VERSION 5.8 ;
BUSBITCHARS "[]" ;
DIVIDERCHAR "/" ;
UNITS
    DATABASE MICRONS 1000 ;
END UNITS

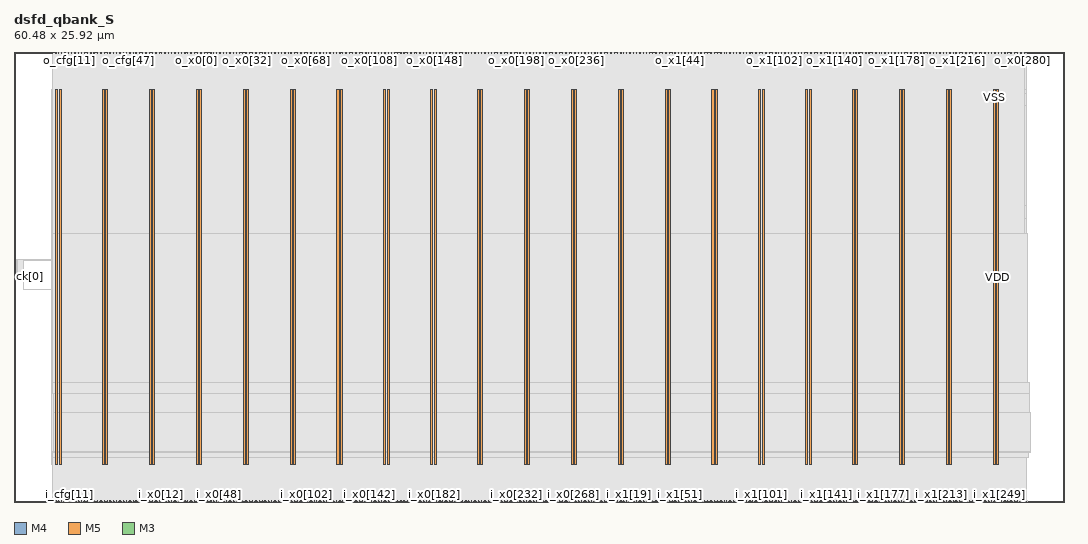
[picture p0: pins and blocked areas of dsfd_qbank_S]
MACRO dsfd_qbank_S
  FOREIGN dsfd_qbank_S 0 0 ;
  CLASS BLOCK ;
  SIZE 60.48 BY 25.92 ;
  PIN ck[0]
    DIRECTION INPUT ;
    USE SIGNAL ;
    PORT
      LAYER M4 ;
        RECT  0 12.96 0.084 12.984 ;
    END
  END ck[0]
  PIN i_cfg[0]
    DIRECTION INPUT ;
    USE SIGNAL ;
    PORT
      LAYER M5 ;
        RECT  2.208 0 2.232 0.084 ;
    END
  END i_cfg[0]
  PIN i_cfg[10]
    DIRECTION INPUT ;
    USE SIGNAL ;
    PORT
      LAYER M5 ;
        RECT  3.12 0 3.144 0.084 ;
    END
  END i_cfg[10]
  PIN i_cfg[11]
    DIRECTION INPUT ;
    USE SIGNAL ;
    PORT
      LAYER M3 ;
        RECT  3.204 0 3.222 0.038 ;
    END
  END i_cfg[11]
  PIN i_cfg[12]
    DIRECTION INPUT ;
    USE SIGNAL ;
    PORT
      LAYER M5 ;
        RECT  3.312 0 3.336 0.084 ;
    END
  END i_cfg[12]
  PIN i_cfg[13]
    DIRECTION INPUT ;
    USE SIGNAL ;
    PORT
      LAYER M3 ;
        RECT  3.42 0 3.438 0.038 ;
    END
  END i_cfg[13]
  PIN i_cfg[14]
    DIRECTION INPUT ;
    USE SIGNAL ;
    PORT
      LAYER M5 ;
        RECT  3.504 0 3.528 0.084 ;
    END
  END i_cfg[14]
  PIN i_cfg[15]
    DIRECTION INPUT ;
    USE SIGNAL ;
    PORT
      LAYER M3 ;
        RECT  3.6 0 3.618 0.038 ;
    END
  END i_cfg[15]
  PIN i_cfg[16]
    DIRECTION INPUT ;
    USE SIGNAL ;
    PORT
      LAYER M5 ;
        RECT  3.696 0 3.72 0.084 ;
    END
  END i_cfg[16]
  PIN i_cfg[17]
    DIRECTION INPUT ;
    USE SIGNAL ;
    PORT
      LAYER M3 ;
        RECT  3.78 0 3.798 0.038 ;
    END
  END i_cfg[17]
  PIN i_cfg[18]
    DIRECTION INPUT ;
    USE SIGNAL ;
    PORT
      LAYER M5 ;
        RECT  3.888 0 3.912 0.084 ;
    END
  END i_cfg[18]
  PIN i_cfg[19]
    DIRECTION INPUT ;
    USE SIGNAL ;
    PORT
      LAYER M3 ;
        RECT  3.996 0 4.014 0.038 ;
    END
  END i_cfg[19]
  PIN i_cfg[1]
    DIRECTION INPUT ;
    USE SIGNAL ;
    PORT
      LAYER M3 ;
        RECT  2.304 0 2.322 0.038 ;
    END
  END i_cfg[1]
  PIN i_cfg[20]
    DIRECTION INPUT ;
    USE SIGNAL ;
    PORT
      LAYER M5 ;
        RECT  4.032 0 4.056 0.084 ;
    END
  END i_cfg[20]
  PIN i_cfg[21]
    DIRECTION INPUT ;
    USE SIGNAL ;
    PORT
      LAYER M3 ;
        RECT  4.14 0 4.158 0.038 ;
    END
  END i_cfg[21]
  PIN i_cfg[22]
    DIRECTION INPUT ;
    USE SIGNAL ;
    PORT
      LAYER M5 ;
        RECT  4.224 0 4.248 0.084 ;
    END
  END i_cfg[22]
  PIN i_cfg[23]
    DIRECTION INPUT ;
    USE SIGNAL ;
    PORT
      LAYER M3 ;
        RECT  4.32 0 4.338 0.038 ;
    END
  END i_cfg[23]
  PIN i_cfg[24]
    DIRECTION INPUT ;
    USE SIGNAL ;
    PORT
      LAYER M5 ;
        RECT  4.416 0 4.44 0.084 ;
    END
  END i_cfg[24]
  PIN i_cfg[25]
    DIRECTION INPUT ;
    USE SIGNAL ;
    PORT
      LAYER M3 ;
        RECT  4.5 0 4.518 0.038 ;
    END
  END i_cfg[25]
  PIN i_cfg[26]
    DIRECTION INPUT ;
    USE SIGNAL ;
    PORT
      LAYER M5 ;
        RECT  4.608 0 4.632 0.084 ;
    END
  END i_cfg[26]
  PIN i_cfg[27]
    DIRECTION INPUT ;
    USE SIGNAL ;
    PORT
      LAYER M3 ;
        RECT  4.716 0 4.734 0.038 ;
    END
  END i_cfg[27]
  PIN i_cfg[28]
    DIRECTION INPUT ;
    USE SIGNAL ;
    PORT
      LAYER M5 ;
        RECT  4.8 0 4.824 0.084 ;
    END
  END i_cfg[28]
  PIN i_cfg[29]
    DIRECTION INPUT ;
    USE SIGNAL ;
    PORT
      LAYER M3 ;
        RECT  4.896 0 4.914 0.038 ;
    END
  END i_cfg[29]
  PIN i_cfg[2]
    DIRECTION INPUT ;
    USE SIGNAL ;
    PORT
      LAYER M5 ;
        RECT  2.4 0 2.424 0.084 ;
    END
  END i_cfg[2]
  PIN i_cfg[30]
    DIRECTION INPUT ;
    USE SIGNAL ;
    PORT
      LAYER M5 ;
        RECT  4.992 0 5.016 0.084 ;
    END
  END i_cfg[30]
  PIN i_cfg[31]
    DIRECTION INPUT ;
    USE SIGNAL ;
    PORT
      LAYER M3 ;
        RECT  5.076 0 5.094 0.038 ;
    END
  END i_cfg[31]
  PIN i_cfg[32]
    DIRECTION INPUT ;
    USE SIGNAL ;
    PORT
      LAYER M5 ;
        RECT  5.184 0 5.208 0.084 ;
    END
  END i_cfg[32]
  PIN i_cfg[33]
    DIRECTION INPUT ;
    USE SIGNAL ;
    PORT
      LAYER M3 ;
        RECT  5.292 0 5.31 0.038 ;
    END
  END i_cfg[33]
  PIN i_cfg[34]
    DIRECTION INPUT ;
    USE SIGNAL ;
    PORT
      LAYER M5 ;
        RECT  5.376 0 5.4 0.084 ;
    END
  END i_cfg[34]
  PIN i_cfg[35]
    DIRECTION INPUT ;
    USE SIGNAL ;
    PORT
      LAYER M3 ;
        RECT  5.472 0 5.49 0.038 ;
    END
  END i_cfg[35]
  PIN i_cfg[36]
    DIRECTION INPUT ;
    USE SIGNAL ;
    PORT
      LAYER M5 ;
        RECT  5.52 0 5.544 0.084 ;
    END
  END i_cfg[36]
  PIN i_cfg[37]
    DIRECTION INPUT ;
    USE SIGNAL ;
    PORT
      LAYER M3 ;
        RECT  5.616 0 5.634 0.038 ;
    END
  END i_cfg[37]
  PIN i_cfg[38]
    DIRECTION INPUT ;
    USE SIGNAL ;
    PORT
      LAYER M5 ;
        RECT  5.712 0 5.736 0.084 ;
    END
  END i_cfg[38]
  PIN i_cfg[39]
    DIRECTION INPUT ;
    USE SIGNAL ;
    PORT
      LAYER M3 ;
        RECT  5.796 0 5.814 0.038 ;
    END
  END i_cfg[39]
  PIN i_cfg[3]
    DIRECTION INPUT ;
    USE SIGNAL ;
    PORT
      LAYER M3 ;
        RECT  2.484 0 2.502 0.038 ;
    END
  END i_cfg[3]
  PIN i_cfg[40]
    DIRECTION INPUT ;
    USE SIGNAL ;
    PORT
      LAYER M5 ;
        RECT  5.904 0 5.928 0.084 ;
    END
  END i_cfg[40]
  PIN i_cfg[41]
    DIRECTION INPUT ;
    USE SIGNAL ;
    PORT
      LAYER M3 ;
        RECT  6.012 0 6.03 0.038 ;
    END
  END i_cfg[41]
  PIN i_cfg[42]
    DIRECTION INPUT ;
    USE SIGNAL ;
    PORT
      LAYER M5 ;
        RECT  6.096 0 6.12 0.084 ;
    END
  END i_cfg[42]
  PIN i_cfg[43]
    DIRECTION INPUT ;
    USE SIGNAL ;
    PORT
      LAYER M3 ;
        RECT  6.192 0 6.21 0.038 ;
    END
  END i_cfg[43]
  PIN i_cfg[44]
    DIRECTION INPUT ;
    USE SIGNAL ;
    PORT
      LAYER M5 ;
        RECT  6.288 0 6.312 0.084 ;
    END
  END i_cfg[44]
  PIN i_cfg[45]
    DIRECTION INPUT ;
    USE SIGNAL ;
    PORT
      LAYER M3 ;
        RECT  6.372 0 6.39 0.038 ;
    END
  END i_cfg[45]
  PIN i_cfg[46]
    DIRECTION INPUT ;
    USE SIGNAL ;
    PORT
      LAYER M5 ;
        RECT  6.48 0 6.504 0.084 ;
    END
  END i_cfg[46]
  PIN i_cfg[47]
    DIRECTION INPUT ;
    USE SIGNAL ;
    PORT
      LAYER M3 ;
        RECT  6.588 0 6.606 0.038 ;
    END
  END i_cfg[47]
  PIN i_cfg[48]
    DIRECTION INPUT ;
    USE SIGNAL ;
    PORT
      LAYER M5 ;
        RECT  6.672 0 6.696 0.084 ;
    END
  END i_cfg[48]
  PIN i_cfg[49]
    DIRECTION INPUT ;
    USE SIGNAL ;
    PORT
      LAYER M3 ;
        RECT  6.768 0 6.786 0.038 ;
    END
  END i_cfg[49]
  PIN i_cfg[4]
    DIRECTION INPUT ;
    USE SIGNAL ;
    PORT
      LAYER M5 ;
        RECT  2.544 0 2.568 0.084 ;
    END
  END i_cfg[4]
  PIN i_cfg[50]
    DIRECTION INPUT ;
    USE SIGNAL ;
    PORT
      LAYER M5 ;
        RECT  6.864 0 6.888 0.084 ;
    END
  END i_cfg[50]
  PIN i_cfg[51]
    DIRECTION INPUT ;
    USE SIGNAL ;
    PORT
      LAYER M3 ;
        RECT  6.948 0 6.966 0.038 ;
    END
  END i_cfg[51]
  PIN i_cfg[52]
    DIRECTION INPUT ;
    USE SIGNAL ;
    PORT
      LAYER M5 ;
        RECT  7.008 0 7.032 0.084 ;
    END
  END i_cfg[52]
  PIN i_cfg[53]
    DIRECTION INPUT ;
    USE SIGNAL ;
    PORT
      LAYER M3 ;
        RECT  7.092 0 7.11 0.038 ;
    END
  END i_cfg[53]
  PIN i_cfg[5]
    DIRECTION INPUT ;
    USE SIGNAL ;
    PORT
      LAYER M3 ;
        RECT  2.628 0 2.646 0.038 ;
    END
  END i_cfg[5]
  PIN i_cfg[6]
    DIRECTION INPUT ;
    USE SIGNAL ;
    PORT
      LAYER M5 ;
        RECT  2.736 0 2.76 0.084 ;
    END
  END i_cfg[6]
  PIN i_cfg[7]
    DIRECTION INPUT ;
    USE SIGNAL ;
    PORT
      LAYER M3 ;
        RECT  2.844 0 2.862 0.038 ;
    END
  END i_cfg[7]
  PIN i_cfg[8]
    DIRECTION INPUT ;
    USE SIGNAL ;
    PORT
      LAYER M5 ;
        RECT  2.928 0 2.952 0.084 ;
    END
  END i_cfg[8]
  PIN i_cfg[9]
    DIRECTION INPUT ;
    USE SIGNAL ;
    PORT
      LAYER M3 ;
        RECT  3.024 0 3.042 0.038 ;
    END
  END i_cfg[9]
  PIN i_go[0]
    DIRECTION INPUT ;
    USE SIGNAL ;
    PORT
      LAYER M5 ;
        RECT  7.2 0 7.224 0.084 ;
    END
  END i_go[0]
  PIN i_x0[0]
    DIRECTION INPUT ;
    USE SIGNAL ;
    PORT
      LAYER M3 ;
        RECT  7.308 0 7.326 0.038 ;
    END
  END i_x0[0]
  PIN i_x0[100]
    DIRECTION INPUT ;
    USE SIGNAL ;
    PORT
      LAYER M3 ;
        RECT  16.596 0 16.614 0.038 ;
    END
  END i_x0[100]
  PIN i_x0[101]
    DIRECTION INPUT ;
    USE SIGNAL ;
    PORT
      LAYER M5 ;
        RECT  16.704 0 16.728 0.084 ;
    END
  END i_x0[101]
  PIN i_x0[102]
    DIRECTION INPUT ;
    USE SIGNAL ;
    PORT
      LAYER M3 ;
        RECT  16.812 0 16.83 0.038 ;
    END
  END i_x0[102]
  PIN i_x0[103]
    DIRECTION INPUT ;
    USE SIGNAL ;
    PORT
      LAYER M5 ;
        RECT  16.896 0 16.92 0.084 ;
    END
  END i_x0[103]
  PIN i_x0[104]
    DIRECTION INPUT ;
    USE SIGNAL ;
    PORT
      LAYER M3 ;
        RECT  16.992 0 17.01 0.038 ;
    END
  END i_x0[104]
  PIN i_x0[105]
    DIRECTION INPUT ;
    USE SIGNAL ;
    PORT
      LAYER M5 ;
        RECT  17.088 0 17.112 0.084 ;
    END
  END i_x0[105]
  PIN i_x0[106]
    DIRECTION INPUT ;
    USE SIGNAL ;
    PORT
      LAYER M3 ;
        RECT  17.172 0 17.19 0.038 ;
    END
  END i_x0[106]
  PIN i_x0[107]
    DIRECTION INPUT ;
    USE SIGNAL ;
    PORT
      LAYER M5 ;
        RECT  17.28 0 17.304 0.084 ;
    END
  END i_x0[107]
  PIN i_x0[108]
    DIRECTION INPUT ;
    USE SIGNAL ;
    PORT
      LAYER M3 ;
        RECT  17.316 0 17.334 0.038 ;
    END
  END i_x0[108]
  PIN i_x0[109]
    DIRECTION INPUT ;
    USE SIGNAL ;
    PORT
      LAYER M5 ;
        RECT  17.424 0 17.448 0.084 ;
    END
  END i_x0[109]
  PIN i_x0[10]
    DIRECTION INPUT ;
    USE SIGNAL ;
    PORT
      LAYER M3 ;
        RECT  8.244 0 8.262 0.038 ;
    END
  END i_x0[10]
  PIN i_x0[110]
    DIRECTION INPUT ;
    USE SIGNAL ;
    PORT
      LAYER M3 ;
        RECT  17.532 0 17.55 0.038 ;
    END
  END i_x0[110]
  PIN i_x0[111]
    DIRECTION INPUT ;
    USE SIGNAL ;
    PORT
      LAYER M5 ;
        RECT  17.616 0 17.64 0.084 ;
    END
  END i_x0[111]
  PIN i_x0[112]
    DIRECTION INPUT ;
    USE SIGNAL ;
    PORT
      LAYER M3 ;
        RECT  17.712 0 17.73 0.038 ;
    END
  END i_x0[112]
  PIN i_x0[113]
    DIRECTION INPUT ;
    USE SIGNAL ;
    PORT
      LAYER M5 ;
        RECT  17.808 0 17.832 0.084 ;
    END
  END i_x0[113]
  PIN i_x0[114]
    DIRECTION INPUT ;
    USE SIGNAL ;
    PORT
      LAYER M3 ;
        RECT  17.892 0 17.91 0.038 ;
    END
  END i_x0[114]
  PIN i_x0[115]
    DIRECTION INPUT ;
    USE SIGNAL ;
    PORT
      LAYER M5 ;
        RECT  18 0 18.024 0.084 ;
    END
  END i_x0[115]
  PIN i_x0[116]
    DIRECTION INPUT ;
    USE SIGNAL ;
    PORT
      LAYER M3 ;
        RECT  18.108 0 18.126 0.038 ;
    END
  END i_x0[116]
  PIN i_x0[117]
    DIRECTION INPUT ;
    USE SIGNAL ;
    PORT
      LAYER M5 ;
        RECT  18.192 0 18.216 0.084 ;
    END
  END i_x0[117]
  PIN i_x0[118]
    DIRECTION INPUT ;
    USE SIGNAL ;
    PORT
      LAYER M3 ;
        RECT  18.288 0 18.306 0.038 ;
    END
  END i_x0[118]
  PIN i_x0[119]
    DIRECTION INPUT ;
    USE SIGNAL ;
    PORT
      LAYER M5 ;
        RECT  18.384 0 18.408 0.084 ;
    END
  END i_x0[119]
  PIN i_x0[11]
    DIRECTION INPUT ;
    USE SIGNAL ;
    PORT
      LAYER M5 ;
        RECT  8.352 0 8.376 0.084 ;
    END
  END i_x0[11]
  PIN i_x0[120]
    DIRECTION INPUT ;
    USE SIGNAL ;
    PORT
      LAYER M3 ;
        RECT  18.468 0 18.486 0.038 ;
    END
  END i_x0[120]
  PIN i_x0[121]
    DIRECTION INPUT ;
    USE SIGNAL ;
    PORT
      LAYER M5 ;
        RECT  18.576 0 18.6 0.084 ;
    END
  END i_x0[121]
  PIN i_x0[122]
    DIRECTION INPUT ;
    USE SIGNAL ;
    PORT
      LAYER M3 ;
        RECT  18.684 0 18.702 0.038 ;
    END
  END i_x0[122]
  PIN i_x0[123]
    DIRECTION INPUT ;
    USE SIGNAL ;
    PORT
      LAYER M5 ;
        RECT  18.768 0 18.792 0.084 ;
    END
  END i_x0[123]
  PIN i_x0[124]
    DIRECTION INPUT ;
    USE SIGNAL ;
    PORT
      LAYER M3 ;
        RECT  18.828 0 18.846 0.038 ;
    END
  END i_x0[124]
  PIN i_x0[125]
    DIRECTION INPUT ;
    USE SIGNAL ;
    PORT
      LAYER M5 ;
        RECT  18.912 0 18.936 0.084 ;
    END
  END i_x0[125]
  PIN i_x0[126]
    DIRECTION INPUT ;
    USE SIGNAL ;
    PORT
      LAYER M3 ;
        RECT  19.008 0 19.026 0.038 ;
    END
  END i_x0[126]
  PIN i_x0[127]
    DIRECTION INPUT ;
    USE SIGNAL ;
    PORT
      LAYER M5 ;
        RECT  19.104 0 19.128 0.084 ;
    END
  END i_x0[127]
  PIN i_x0[128]
    DIRECTION INPUT ;
    USE SIGNAL ;
    PORT
      LAYER M3 ;
        RECT  19.188 0 19.206 0.038 ;
    END
  END i_x0[128]
  PIN i_x0[129]
    DIRECTION INPUT ;
    USE SIGNAL ;
    PORT
      LAYER M5 ;
        RECT  19.296 0 19.32 0.084 ;
    END
  END i_x0[129]
  PIN i_x0[12]
    DIRECTION INPUT ;
    USE SIGNAL ;
    PORT
      LAYER M3 ;
        RECT  8.46 0 8.478 0.038 ;
    END
  END i_x0[12]
  PIN i_x0[130]
    DIRECTION INPUT ;
    USE SIGNAL ;
    PORT
      LAYER M3 ;
        RECT  19.404 0 19.422 0.038 ;
    END
  END i_x0[130]
  PIN i_x0[131]
    DIRECTION INPUT ;
    USE SIGNAL ;
    PORT
      LAYER M5 ;
        RECT  19.488 0 19.512 0.084 ;
    END
  END i_x0[131]
  PIN i_x0[132]
    DIRECTION INPUT ;
    USE SIGNAL ;
    PORT
      LAYER M3 ;
        RECT  19.584 0 19.602 0.038 ;
    END
  END i_x0[132]
  PIN i_x0[133]
    DIRECTION INPUT ;
    USE SIGNAL ;
    PORT
      LAYER M5 ;
        RECT  19.68 0 19.704 0.084 ;
    END
  END i_x0[133]
  PIN i_x0[134]
    DIRECTION INPUT ;
    USE SIGNAL ;
    PORT
      LAYER M3 ;
        RECT  19.764 0 19.782 0.038 ;
    END
  END i_x0[134]
  PIN i_x0[135]
    DIRECTION INPUT ;
    USE SIGNAL ;
    PORT
      LAYER M5 ;
        RECT  19.872 0 19.896 0.084 ;
    END
  END i_x0[135]
  PIN i_x0[136]
    DIRECTION INPUT ;
    USE SIGNAL ;
    PORT
      LAYER M3 ;
        RECT  19.98 0 19.998 0.038 ;
    END
  END i_x0[136]
  PIN i_x0[137]
    DIRECTION INPUT ;
    USE SIGNAL ;
    PORT
      LAYER M5 ;
        RECT  20.064 0 20.088 0.084 ;
    END
  END i_x0[137]
  PIN i_x0[138]
    DIRECTION INPUT ;
    USE SIGNAL ;
    PORT
      LAYER M3 ;
        RECT  20.16 0 20.178 0.038 ;
    END
  END i_x0[138]
  PIN i_x0[139]
    DIRECTION INPUT ;
    USE SIGNAL ;
    PORT
      LAYER M5 ;
        RECT  20.256 0 20.28 0.084 ;
    END
  END i_x0[139]
  PIN i_x0[13]
    DIRECTION INPUT ;
    USE SIGNAL ;
    PORT
      LAYER M5 ;
        RECT  8.496 0 8.52 0.084 ;
    END
  END i_x0[13]
  PIN i_x0[140]
    DIRECTION INPUT ;
    USE SIGNAL ;
    PORT
      LAYER M3 ;
        RECT  20.304 0 20.322 0.038 ;
    END
  END i_x0[140]
  PIN i_x0[141]
    DIRECTION INPUT ;
    USE SIGNAL ;
    PORT
      LAYER M5 ;
        RECT  20.4 0 20.424 0.084 ;
    END
  END i_x0[141]
  PIN i_x0[142]
    DIRECTION INPUT ;
    USE SIGNAL ;
    PORT
      LAYER M3 ;
        RECT  20.484 0 20.502 0.038 ;
    END
  END i_x0[142]
  PIN i_x0[143]
    DIRECTION INPUT ;
    USE SIGNAL ;
    PORT
      LAYER M5 ;
        RECT  20.592 0 20.616 0.084 ;
    END
  END i_x0[143]
  PIN i_x0[144]
    DIRECTION INPUT ;
    USE SIGNAL ;
    PORT
      LAYER M3 ;
        RECT  20.7 0 20.718 0.038 ;
    END
  END i_x0[144]
  PIN i_x0[145]
    DIRECTION INPUT ;
    USE SIGNAL ;
    PORT
      LAYER M5 ;
        RECT  20.784 0 20.808 0.084 ;
    END
  END i_x0[145]
  PIN i_x0[146]
    DIRECTION INPUT ;
    USE SIGNAL ;
    PORT
      LAYER M3 ;
        RECT  20.88 0 20.898 0.038 ;
    END
  END i_x0[146]
  PIN i_x0[147]
    DIRECTION INPUT ;
    USE SIGNAL ;
    PORT
      LAYER M5 ;
        RECT  20.976 0 21 0.084 ;
    END
  END i_x0[147]
  PIN i_x0[148]
    DIRECTION INPUT ;
    USE SIGNAL ;
    PORT
      LAYER M3 ;
        RECT  21.06 0 21.078 0.038 ;
    END
  END i_x0[148]
  PIN i_x0[149]
    DIRECTION INPUT ;
    USE SIGNAL ;
    PORT
      LAYER M5 ;
        RECT  21.168 0 21.192 0.084 ;
    END
  END i_x0[149]
  PIN i_x0[14]
    DIRECTION INPUT ;
    USE SIGNAL ;
    PORT
      LAYER M3 ;
        RECT  8.604 0 8.622 0.038 ;
    END
  END i_x0[14]
  PIN i_x0[150]
    DIRECTION INPUT ;
    USE SIGNAL ;
    PORT
      LAYER M3 ;
        RECT  21.276 0 21.294 0.038 ;
    END
  END i_x0[150]
  PIN i_x0[151]
    DIRECTION INPUT ;
    USE SIGNAL ;
    PORT
      LAYER M5 ;
        RECT  21.36 0 21.384 0.084 ;
    END
  END i_x0[151]
  PIN i_x0[152]
    DIRECTION INPUT ;
    USE SIGNAL ;
    PORT
      LAYER M3 ;
        RECT  21.456 0 21.474 0.038 ;
    END
  END i_x0[152]
  PIN i_x0[153]
    DIRECTION INPUT ;
    USE SIGNAL ;
    PORT
      LAYER M5 ;
        RECT  21.552 0 21.576 0.084 ;
    END
  END i_x0[153]
  PIN i_x0[154]
    DIRECTION INPUT ;
    USE SIGNAL ;
    PORT
      LAYER M3 ;
        RECT  21.636 0 21.654 0.038 ;
    END
  END i_x0[154]
  PIN i_x0[155]
    DIRECTION INPUT ;
    USE SIGNAL ;
    PORT
      LAYER M5 ;
        RECT  21.744 0 21.768 0.084 ;
    END
  END i_x0[155]
  PIN i_x0[156]
    DIRECTION INPUT ;
    USE SIGNAL ;
    PORT
      LAYER M3 ;
        RECT  21.78 0 21.798 0.038 ;
    END
  END i_x0[156]
  PIN i_x0[157]
    DIRECTION INPUT ;
    USE SIGNAL ;
    PORT
      LAYER M5 ;
        RECT  21.888 0 21.912 0.084 ;
    END
  END i_x0[157]
  PIN i_x0[158]
    DIRECTION INPUT ;
    USE SIGNAL ;
    PORT
      LAYER M3 ;
        RECT  21.996 0 22.014 0.038 ;
    END
  END i_x0[158]
  PIN i_x0[159]
    DIRECTION INPUT ;
    USE SIGNAL ;
    PORT
      LAYER M5 ;
        RECT  22.08 0 22.104 0.084 ;
    END
  END i_x0[159]
  PIN i_x0[15]
    DIRECTION INPUT ;
    USE SIGNAL ;
    PORT
      LAYER M5 ;
        RECT  8.688 0 8.712 0.084 ;
    END
  END i_x0[15]
  PIN i_x0[160]
    DIRECTION INPUT ;
    USE SIGNAL ;
    PORT
      LAYER M3 ;
        RECT  22.176 0 22.194 0.038 ;
    END
  END i_x0[160]
  PIN i_x0[161]
    DIRECTION INPUT ;
    USE SIGNAL ;
    PORT
      LAYER M5 ;
        RECT  22.272 0 22.296 0.084 ;
    END
  END i_x0[161]
  PIN i_x0[162]
    DIRECTION INPUT ;
    USE SIGNAL ;
    PORT
      LAYER M3 ;
        RECT  22.356 0 22.374 0.038 ;
    END
  END i_x0[162]
  PIN i_x0[163]
    DIRECTION INPUT ;
    USE SIGNAL ;
    PORT
      LAYER M5 ;
        RECT  22.464 0 22.488 0.084 ;
    END
  END i_x0[163]
  PIN i_x0[164]
    DIRECTION INPUT ;
    USE SIGNAL ;
    PORT
      LAYER M3 ;
        RECT  22.572 0 22.59 0.038 ;
    END
  END i_x0[164]
  PIN i_x0[165]
    DIRECTION INPUT ;
    USE SIGNAL ;
    PORT
      LAYER M5 ;
        RECT  22.656 0 22.68 0.084 ;
    END
  END i_x0[165]
  PIN i_x0[166]
    DIRECTION INPUT ;
    USE SIGNAL ;
    PORT
      LAYER M3 ;
        RECT  22.752 0 22.77 0.038 ;
    END
  END i_x0[166]
  PIN i_x0[167]
    DIRECTION INPUT ;
    USE SIGNAL ;
    PORT
      LAYER M5 ;
        RECT  22.848 0 22.872 0.084 ;
    END
  END i_x0[167]
  PIN i_x0[168]
    DIRECTION INPUT ;
    USE SIGNAL ;
    PORT
      LAYER M3 ;
        RECT  22.932 0 22.95 0.038 ;
    END
  END i_x0[168]
  PIN i_x0[169]
    DIRECTION INPUT ;
    USE SIGNAL ;
    PORT
      LAYER M5 ;
        RECT  23.04 0 23.064 0.084 ;
    END
  END i_x0[169]
  PIN i_x0[16]
    DIRECTION INPUT ;
    USE SIGNAL ;
    PORT
      LAYER M3 ;
        RECT  8.784 0 8.802 0.038 ;
    END
  END i_x0[16]
  PIN i_x0[170]
    DIRECTION INPUT ;
    USE SIGNAL ;
    PORT
      LAYER M3 ;
        RECT  23.148 0 23.166 0.038 ;
    END
  END i_x0[170]
  PIN i_x0[171]
    DIRECTION INPUT ;
    USE SIGNAL ;
    PORT
      LAYER M5 ;
        RECT  23.184 0 23.208 0.084 ;
    END
  END i_x0[171]
  PIN i_x0[172]
    DIRECTION INPUT ;
    USE SIGNAL ;
    PORT
      LAYER M3 ;
        RECT  23.292 0 23.31 0.038 ;
    END
  END i_x0[172]
  PIN i_x0[173]
    DIRECTION INPUT ;
    USE SIGNAL ;
    PORT
      LAYER M5 ;
        RECT  23.376 0 23.4 0.084 ;
    END
  END i_x0[173]
  PIN i_x0[174]
    DIRECTION INPUT ;
    USE SIGNAL ;
    PORT
      LAYER M3 ;
        RECT  23.472 0 23.49 0.038 ;
    END
  END i_x0[174]
  PIN i_x0[175]
    DIRECTION INPUT ;
    USE SIGNAL ;
    PORT
      LAYER M5 ;
        RECT  23.568 0 23.592 0.084 ;
    END
  END i_x0[175]
  PIN i_x0[176]
    DIRECTION INPUT ;
    USE SIGNAL ;
    PORT
      LAYER M3 ;
        RECT  23.652 0 23.67 0.038 ;
    END
  END i_x0[176]
  PIN i_x0[177]
    DIRECTION INPUT ;
    USE SIGNAL ;
    PORT
      LAYER M5 ;
        RECT  23.76 0 23.784 0.084 ;
    END
  END i_x0[177]
  PIN i_x0[178]
    DIRECTION INPUT ;
    USE SIGNAL ;
    PORT
      LAYER M3 ;
        RECT  23.868 0 23.886 0.038 ;
    END
  END i_x0[178]
  PIN i_x0[179]
    DIRECTION INPUT ;
    USE SIGNAL ;
    PORT
      LAYER M5 ;
        RECT  23.952 0 23.976 0.084 ;
    END
  END i_x0[179]
  PIN i_x0[17]
    DIRECTION INPUT ;
    USE SIGNAL ;
    PORT
      LAYER M5 ;
        RECT  8.88 0 8.904 0.084 ;
    END
  END i_x0[17]
  PIN i_x0[180]
    DIRECTION INPUT ;
    USE SIGNAL ;
    PORT
      LAYER M3 ;
        RECT  24.048 0 24.066 0.038 ;
    END
  END i_x0[180]
  PIN i_x0[181]
    DIRECTION INPUT ;
    USE SIGNAL ;
    PORT
      LAYER M5 ;
        RECT  24.144 0 24.168 0.084 ;
    END
  END i_x0[181]
  PIN i_x0[182]
    DIRECTION INPUT ;
    USE SIGNAL ;
    PORT
      LAYER M3 ;
        RECT  24.228 0 24.246 0.038 ;
    END
  END i_x0[182]
  PIN i_x0[183]
    DIRECTION INPUT ;
    USE SIGNAL ;
    PORT
      LAYER M5 ;
        RECT  24.336 0 24.36 0.084 ;
    END
  END i_x0[183]
  PIN i_x0[184]
    DIRECTION INPUT ;
    USE SIGNAL ;
    PORT
      LAYER M3 ;
        RECT  24.444 0 24.462 0.038 ;
    END
  END i_x0[184]
  PIN i_x0[185]
    DIRECTION INPUT ;
    USE SIGNAL ;
    PORT
      LAYER M5 ;
        RECT  24.528 0 24.552 0.084 ;
    END
  END i_x0[185]
  PIN i_x0[186]
    DIRECTION INPUT ;
    USE SIGNAL ;
    PORT
      LAYER M3 ;
        RECT  24.624 0 24.642 0.038 ;
    END
  END i_x0[186]
  PIN i_x0[187]
    DIRECTION INPUT ;
    USE SIGNAL ;
    PORT
      LAYER M5 ;
        RECT  24.672 0 24.696 0.084 ;
    END
  END i_x0[187]
  PIN i_x0[188]
    DIRECTION INPUT ;
    USE SIGNAL ;
    PORT
      LAYER M3 ;
        RECT  24.768 0 24.786 0.038 ;
    END
  END i_x0[188]
  PIN i_x0[189]
    DIRECTION INPUT ;
    USE SIGNAL ;
    PORT
      LAYER M5 ;
        RECT  24.864 0 24.888 0.084 ;
    END
  END i_x0[189]
  PIN i_x0[18]
    DIRECTION INPUT ;
    USE SIGNAL ;
    PORT
      LAYER M3 ;
        RECT  8.964 0 8.982 0.038 ;
    END
  END i_x0[18]
  PIN i_x0[190]
    DIRECTION INPUT ;
    USE SIGNAL ;
    PORT
      LAYER M3 ;
        RECT  24.948 0 24.966 0.038 ;
    END
  END i_x0[190]
  PIN i_x0[191]
    DIRECTION INPUT ;
    USE SIGNAL ;
    PORT
      LAYER M5 ;
        RECT  25.056 0 25.08 0.084 ;
    END
  END i_x0[191]
  PIN i_x0[192]
    DIRECTION INPUT ;
    USE SIGNAL ;
    PORT
      LAYER M3 ;
        RECT  25.164 0 25.182 0.038 ;
    END
  END i_x0[192]
  PIN i_x0[193]
    DIRECTION INPUT ;
    USE SIGNAL ;
    PORT
      LAYER M5 ;
        RECT  25.248 0 25.272 0.084 ;
    END
  END i_x0[193]
  PIN i_x0[194]
    DIRECTION INPUT ;
    USE SIGNAL ;
    PORT
      LAYER M3 ;
        RECT  25.344 0 25.362 0.038 ;
    END
  END i_x0[194]
  PIN i_x0[195]
    DIRECTION INPUT ;
    USE SIGNAL ;
    PORT
      LAYER M5 ;
        RECT  25.44 0 25.464 0.084 ;
    END
  END i_x0[195]
  PIN i_x0[196]
    DIRECTION INPUT ;
    USE SIGNAL ;
    PORT
      LAYER M3 ;
        RECT  25.524 0 25.542 0.038 ;
    END
  END i_x0[196]
  PIN i_x0[197]
    DIRECTION INPUT ;
    USE SIGNAL ;
    PORT
      LAYER M5 ;
        RECT  25.632 0 25.656 0.084 ;
    END
  END i_x0[197]
  PIN i_x0[198]
    DIRECTION INPUT ;
    USE SIGNAL ;
    PORT
      LAYER M3 ;
        RECT  25.74 0 25.758 0.038 ;
    END
  END i_x0[198]
  PIN i_x0[199]
    DIRECTION INPUT ;
    USE SIGNAL ;
    PORT
      LAYER M5 ;
        RECT  25.824 0 25.848 0.084 ;
    END
  END i_x0[199]
  PIN i_x0[19]
    DIRECTION INPUT ;
    USE SIGNAL ;
    PORT
      LAYER M5 ;
        RECT  9.072 0 9.096 0.084 ;
    END
  END i_x0[19]
  PIN i_x0[1]
    DIRECTION INPUT ;
    USE SIGNAL ;
    PORT
      LAYER M5 ;
        RECT  7.392 0 7.416 0.084 ;
    END
  END i_x0[1]
  PIN i_x0[200]
    DIRECTION INPUT ;
    USE SIGNAL ;
    PORT
      LAYER M3 ;
        RECT  25.92 0 25.938 0.038 ;
    END
  END i_x0[200]
  PIN i_x0[201]
    DIRECTION INPUT ;
    USE SIGNAL ;
    PORT
      LAYER M5 ;
        RECT  26.016 0 26.04 0.084 ;
    END
  END i_x0[201]
  PIN i_x0[202]
    DIRECTION INPUT ;
    USE SIGNAL ;
    PORT
      LAYER M3 ;
        RECT  26.1 0 26.118 0.038 ;
    END
  END i_x0[202]
  PIN i_x0[203]
    DIRECTION INPUT ;
    USE SIGNAL ;
    PORT
      LAYER M5 ;
        RECT  26.16 0 26.184 0.084 ;
    END
  END i_x0[203]
  PIN i_x0[204]
    DIRECTION INPUT ;
    USE SIGNAL ;
    PORT
      LAYER M3 ;
        RECT  26.244 0 26.262 0.038 ;
    END
  END i_x0[204]
  PIN i_x0[205]
    DIRECTION INPUT ;
    USE SIGNAL ;
    PORT
      LAYER M5 ;
        RECT  26.352 0 26.376 0.084 ;
    END
  END i_x0[205]
  PIN i_x0[206]
    DIRECTION INPUT ;
    USE SIGNAL ;
    PORT
      LAYER M3 ;
        RECT  26.46 0 26.478 0.038 ;
    END
  END i_x0[206]
  PIN i_x0[207]
    DIRECTION INPUT ;
    USE SIGNAL ;
    PORT
      LAYER M5 ;
        RECT  26.544 0 26.568 0.084 ;
    END
  END i_x0[207]
  PIN i_x0[208]
    DIRECTION INPUT ;
    USE SIGNAL ;
    PORT
      LAYER M3 ;
        RECT  26.64 0 26.658 0.038 ;
    END
  END i_x0[208]
  PIN i_x0[209]
    DIRECTION INPUT ;
    USE SIGNAL ;
    PORT
      LAYER M5 ;
        RECT  26.736 0 26.76 0.084 ;
    END
  END i_x0[209]
  PIN i_x0[20]
    DIRECTION INPUT ;
    USE SIGNAL ;
    PORT
      LAYER M3 ;
        RECT  9.18 0 9.198 0.038 ;
    END
  END i_x0[20]
  PIN i_x0[210]
    DIRECTION INPUT ;
    USE SIGNAL ;
    PORT
      LAYER M3 ;
        RECT  26.82 0 26.838 0.038 ;
    END
  END i_x0[210]
  PIN i_x0[211]
    DIRECTION INPUT ;
    USE SIGNAL ;
    PORT
      LAYER M5 ;
        RECT  26.928 0 26.952 0.084 ;
    END
  END i_x0[211]
  PIN i_x0[212]
    DIRECTION INPUT ;
    USE SIGNAL ;
    PORT
      LAYER M3 ;
        RECT  27.036 0 27.054 0.038 ;
    END
  END i_x0[212]
  PIN i_x0[213]
    DIRECTION INPUT ;
    USE SIGNAL ;
    PORT
      LAYER M5 ;
        RECT  27.12 0 27.144 0.084 ;
    END
  END i_x0[213]
  PIN i_x0[214]
    DIRECTION INPUT ;
    USE SIGNAL ;
    PORT
      LAYER M3 ;
        RECT  27.216 0 27.234 0.038 ;
    END
  END i_x0[214]
  PIN i_x0[215]
    DIRECTION INPUT ;
    USE SIGNAL ;
    PORT
      LAYER M5 ;
        RECT  27.312 0 27.336 0.084 ;
    END
  END i_x0[215]
  PIN i_x0[216]
    DIRECTION INPUT ;
    USE SIGNAL ;
    PORT
      LAYER M3 ;
        RECT  27.396 0 27.414 0.038 ;
    END
  END i_x0[216]
  PIN i_x0[217]
    DIRECTION INPUT ;
    USE SIGNAL ;
    PORT
      LAYER M5 ;
        RECT  27.504 0 27.528 0.084 ;
    END
  END i_x0[217]
  PIN i_x0[218]
    DIRECTION INPUT ;
    USE SIGNAL ;
    PORT
      LAYER M3 ;
        RECT  27.612 0 27.63 0.038 ;
    END
  END i_x0[218]
  PIN i_x0[219]
    DIRECTION INPUT ;
    USE SIGNAL ;
    PORT
      LAYER M5 ;
        RECT  27.648 0 27.672 0.084 ;
    END
  END i_x0[219]
  PIN i_x0[21]
    DIRECTION INPUT ;
    USE SIGNAL ;
    PORT
      LAYER M5 ;
        RECT  9.264 0 9.288 0.084 ;
    END
  END i_x0[21]
  PIN i_x0[220]
    DIRECTION INPUT ;
    USE SIGNAL ;
    PORT
      LAYER M3 ;
        RECT  27.756 0 27.774 0.038 ;
    END
  END i_x0[220]
  PIN i_x0[221]
    DIRECTION INPUT ;
    USE SIGNAL ;
    PORT
      LAYER M5 ;
        RECT  27.84 0 27.864 0.084 ;
    END
  END i_x0[221]
  PIN i_x0[222]
    DIRECTION INPUT ;
    USE SIGNAL ;
    PORT
      LAYER M3 ;
        RECT  27.936 0 27.954 0.038 ;
    END
  END i_x0[222]
  PIN i_x0[223]
    DIRECTION INPUT ;
    USE SIGNAL ;
    PORT
      LAYER M5 ;
        RECT  28.032 0 28.056 0.084 ;
    END
  END i_x0[223]
  PIN i_x0[224]
    DIRECTION INPUT ;
    USE SIGNAL ;
    PORT
      LAYER M3 ;
        RECT  28.116 0 28.134 0.038 ;
    END
  END i_x0[224]
  PIN i_x0[225]
    DIRECTION INPUT ;
    USE SIGNAL ;
    PORT
      LAYER M5 ;
        RECT  28.224 0 28.248 0.084 ;
    END
  END i_x0[225]
  PIN i_x0[226]
    DIRECTION INPUT ;
    USE SIGNAL ;
    PORT
      LAYER M3 ;
        RECT  28.332 0 28.35 0.038 ;
    END
  END i_x0[226]
  PIN i_x0[227]
    DIRECTION INPUT ;
    USE SIGNAL ;
    PORT
      LAYER M5 ;
        RECT  28.416 0 28.44 0.084 ;
    END
  END i_x0[227]
  PIN i_x0[228]
    DIRECTION INPUT ;
    USE SIGNAL ;
    PORT
      LAYER M3 ;
        RECT  28.512 0 28.53 0.038 ;
    END
  END i_x0[228]
  PIN i_x0[229]
    DIRECTION INPUT ;
    USE SIGNAL ;
    PORT
      LAYER M5 ;
        RECT  28.608 0 28.632 0.084 ;
    END
  END i_x0[229]
  PIN i_x0[22]
    DIRECTION INPUT ;
    USE SIGNAL ;
    PORT
      LAYER M3 ;
        RECT  9.36 0 9.378 0.038 ;
    END
  END i_x0[22]
  PIN i_x0[230]
    DIRECTION INPUT ;
    USE SIGNAL ;
    PORT
      LAYER M3 ;
        RECT  28.692 0 28.71 0.038 ;
    END
  END i_x0[230]
  PIN i_x0[231]
    DIRECTION INPUT ;
    USE SIGNAL ;
    PORT
      LAYER M5 ;
        RECT  28.8 0 28.824 0.084 ;
    END
  END i_x0[231]
  PIN i_x0[232]
    DIRECTION INPUT ;
    USE SIGNAL ;
    PORT
      LAYER M3 ;
        RECT  28.908 0 28.926 0.038 ;
    END
  END i_x0[232]
  PIN i_x0[233]
    DIRECTION INPUT ;
    USE SIGNAL ;
    PORT
      LAYER M5 ;
        RECT  28.992 0 29.016 0.084 ;
    END
  END i_x0[233]
  PIN i_x0[234]
    DIRECTION INPUT ;
    USE SIGNAL ;
    PORT
      LAYER M3 ;
        RECT  29.088 0 29.106 0.038 ;
    END
  END i_x0[234]
  PIN i_x0[235]
    DIRECTION INPUT ;
    USE SIGNAL ;
    PORT
      LAYER M5 ;
        RECT  29.136 0 29.16 0.084 ;
    END
  END i_x0[235]
  PIN i_x0[236]
    DIRECTION INPUT ;
    USE SIGNAL ;
    PORT
      LAYER M3 ;
        RECT  29.232 0 29.25 0.038 ;
    END
  END i_x0[236]
  PIN i_x0[237]
    DIRECTION INPUT ;
    USE SIGNAL ;
    PORT
      LAYER M5 ;
        RECT  29.328 0 29.352 0.084 ;
    END
  END i_x0[237]
  PIN i_x0[238]
    DIRECTION INPUT ;
    USE SIGNAL ;
    PORT
      LAYER M3 ;
        RECT  29.412 0 29.43 0.038 ;
    END
  END i_x0[238]
  PIN i_x0[239]
    DIRECTION INPUT ;
    USE SIGNAL ;
    PORT
      LAYER M5 ;
        RECT  29.52 0 29.544 0.084 ;
    END
  END i_x0[239]
  PIN i_x0[23]
    DIRECTION INPUT ;
    USE SIGNAL ;
    PORT
      LAYER M5 ;
        RECT  9.456 0 9.48 0.084 ;
    END
  END i_x0[23]
  PIN i_x0[240]
    DIRECTION INPUT ;
    USE SIGNAL ;
    PORT
      LAYER M3 ;
        RECT  29.628 0 29.646 0.038 ;
    END
  END i_x0[240]
  PIN i_x0[241]
    DIRECTION INPUT ;
    USE SIGNAL ;
    PORT
      LAYER M5 ;
        RECT  29.712 0 29.736 0.084 ;
    END
  END i_x0[241]
  PIN i_x0[242]
    DIRECTION INPUT ;
    USE SIGNAL ;
    PORT
      LAYER M3 ;
        RECT  29.808 0 29.826 0.038 ;
    END
  END i_x0[242]
  PIN i_x0[243]
    DIRECTION INPUT ;
    USE SIGNAL ;
    PORT
      LAYER M5 ;
        RECT  29.904 0 29.928 0.084 ;
    END
  END i_x0[243]
  PIN i_x0[244]
    DIRECTION INPUT ;
    USE SIGNAL ;
    PORT
      LAYER M3 ;
        RECT  29.988 0 30.006 0.038 ;
    END
  END i_x0[244]
  PIN i_x0[245]
    DIRECTION INPUT ;
    USE SIGNAL ;
    PORT
      LAYER M5 ;
        RECT  30.096 0 30.12 0.084 ;
    END
  END i_x0[245]
  PIN i_x0[246]
    DIRECTION INPUT ;
    USE SIGNAL ;
    PORT
      LAYER M3 ;
        RECT  30.204 0 30.222 0.038 ;
    END
  END i_x0[246]
  PIN i_x0[247]
    DIRECTION INPUT ;
    USE SIGNAL ;
    PORT
      LAYER M5 ;
        RECT  30.288 0 30.312 0.084 ;
    END
  END i_x0[247]
  PIN i_x0[248]
    DIRECTION INPUT ;
    USE SIGNAL ;
    PORT
      LAYER M3 ;
        RECT  30.384 0 30.402 0.038 ;
    END
  END i_x0[248]
  PIN i_x0[249]
    DIRECTION INPUT ;
    USE SIGNAL ;
    PORT
      LAYER M5 ;
        RECT  30.48 0 30.504 0.084 ;
    END
  END i_x0[249]
  PIN i_x0[24]
    DIRECTION INPUT ;
    USE SIGNAL ;
    PORT
      LAYER M3 ;
        RECT  9.54 0 9.558 0.038 ;
    END
  END i_x0[24]
  PIN i_x0[250]
    DIRECTION INPUT ;
    USE SIGNAL ;
    PORT
      LAYER M3 ;
        RECT  30.564 0 30.582 0.038 ;
    END
  END i_x0[250]
  PIN i_x0[251]
    DIRECTION INPUT ;
    USE SIGNAL ;
    PORT
      LAYER M5 ;
        RECT  30.624 0 30.648 0.084 ;
    END
  END i_x0[251]
  PIN i_x0[252]
    DIRECTION INPUT ;
    USE SIGNAL ;
    PORT
      LAYER M3 ;
        RECT  30.708 0 30.726 0.038 ;
    END
  END i_x0[252]
  PIN i_x0[253]
    DIRECTION INPUT ;
    USE SIGNAL ;
    PORT
      LAYER M5 ;
        RECT  30.816 0 30.84 0.084 ;
    END
  END i_x0[253]
  PIN i_x0[254]
    DIRECTION INPUT ;
    USE SIGNAL ;
    PORT
      LAYER M3 ;
        RECT  30.924 0 30.942 0.038 ;
    END
  END i_x0[254]
  PIN i_x0[255]
    DIRECTION INPUT ;
    USE SIGNAL ;
    PORT
      LAYER M5 ;
        RECT  31.008 0 31.032 0.084 ;
    END
  END i_x0[255]
  PIN i_x0[256]
    DIRECTION INPUT ;
    USE SIGNAL ;
    PORT
      LAYER M3 ;
        RECT  31.104 0 31.122 0.038 ;
    END
  END i_x0[256]
  PIN i_x0[257]
    DIRECTION INPUT ;
    USE SIGNAL ;
    PORT
      LAYER M5 ;
        RECT  31.2 0 31.224 0.084 ;
    END
  END i_x0[257]
  PIN i_x0[258]
    DIRECTION INPUT ;
    USE SIGNAL ;
    PORT
      LAYER M3 ;
        RECT  31.284 0 31.302 0.038 ;
    END
  END i_x0[258]
  PIN i_x0[259]
    DIRECTION INPUT ;
    USE SIGNAL ;
    PORT
      LAYER M5 ;
        RECT  31.392 0 31.416 0.084 ;
    END
  END i_x0[259]
  PIN i_x0[25]
    DIRECTION INPUT ;
    USE SIGNAL ;
    PORT
      LAYER M5 ;
        RECT  9.648 0 9.672 0.084 ;
    END
  END i_x0[25]
  PIN i_x0[260]
    DIRECTION INPUT ;
    USE SIGNAL ;
    PORT
      LAYER M3 ;
        RECT  31.5 0 31.518 0.038 ;
    END
  END i_x0[260]
  PIN i_x0[261]
    DIRECTION INPUT ;
    USE SIGNAL ;
    PORT
      LAYER M5 ;
        RECT  31.584 0 31.608 0.084 ;
    END
  END i_x0[261]
  PIN i_x0[262]
    DIRECTION INPUT ;
    USE SIGNAL ;
    PORT
      LAYER M3 ;
        RECT  31.68 0 31.698 0.038 ;
    END
  END i_x0[262]
  PIN i_x0[263]
    DIRECTION INPUT ;
    USE SIGNAL ;
    PORT
      LAYER M5 ;
        RECT  31.776 0 31.8 0.084 ;
    END
  END i_x0[263]
  PIN i_x0[264]
    DIRECTION INPUT ;
    USE SIGNAL ;
    PORT
      LAYER M3 ;
        RECT  31.86 0 31.878 0.038 ;
    END
  END i_x0[264]
  PIN i_x0[265]
    DIRECTION INPUT ;
    USE SIGNAL ;
    PORT
      LAYER M5 ;
        RECT  31.968 0 31.992 0.084 ;
    END
  END i_x0[265]
  PIN i_x0[266]
    DIRECTION INPUT ;
    USE SIGNAL ;
    PORT
      LAYER M3 ;
        RECT  32.076 0 32.094 0.038 ;
    END
  END i_x0[266]
  PIN i_x0[267]
    DIRECTION INPUT ;
    USE SIGNAL ;
    PORT
      LAYER M5 ;
        RECT  32.112 0 32.136 0.084 ;
    END
  END i_x0[267]
  PIN i_x0[268]
    DIRECTION INPUT ;
    USE SIGNAL ;
    PORT
      LAYER M3 ;
        RECT  32.22 0 32.238 0.038 ;
    END
  END i_x0[268]
  PIN i_x0[269]
    DIRECTION INPUT ;
    USE SIGNAL ;
    PORT
      LAYER M5 ;
        RECT  32.304 0 32.328 0.084 ;
    END
  END i_x0[269]
  PIN i_x0[26]
    DIRECTION INPUT ;
    USE SIGNAL ;
    PORT
      LAYER M3 ;
        RECT  9.756 0 9.774 0.038 ;
    END
  END i_x0[26]
  PIN i_x0[270]
    DIRECTION INPUT ;
    USE SIGNAL ;
    PORT
      LAYER M3 ;
        RECT  32.4 0 32.418 0.038 ;
    END
  END i_x0[270]
  PIN i_x0[271]
    DIRECTION INPUT ;
    USE SIGNAL ;
    PORT
      LAYER M5 ;
        RECT  32.496 0 32.52 0.084 ;
    END
  END i_x0[271]
  PIN i_x0[272]
    DIRECTION INPUT ;
    USE SIGNAL ;
    PORT
      LAYER M3 ;
        RECT  32.58 0 32.598 0.038 ;
    END
  END i_x0[272]
  PIN i_x0[273]
    DIRECTION INPUT ;
    USE SIGNAL ;
    PORT
      LAYER M5 ;
        RECT  32.688 0 32.712 0.084 ;
    END
  END i_x0[273]
  PIN i_x0[274]
    DIRECTION INPUT ;
    USE SIGNAL ;
    PORT
      LAYER M3 ;
        RECT  32.796 0 32.814 0.038 ;
    END
  END i_x0[274]
  PIN i_x0[275]
    DIRECTION INPUT ;
    USE SIGNAL ;
    PORT
      LAYER M5 ;
        RECT  32.88 0 32.904 0.084 ;
    END
  END i_x0[275]
  PIN i_x0[276]
    DIRECTION INPUT ;
    USE SIGNAL ;
    PORT
      LAYER M3 ;
        RECT  32.976 0 32.994 0.038 ;
    END
  END i_x0[276]
  PIN i_x0[277]
    DIRECTION INPUT ;
    USE SIGNAL ;
    PORT
      LAYER M5 ;
        RECT  33.072 0 33.096 0.084 ;
    END
  END i_x0[277]
  PIN i_x0[278]
    DIRECTION INPUT ;
    USE SIGNAL ;
    PORT
      LAYER M3 ;
        RECT  33.156 0 33.174 0.038 ;
    END
  END i_x0[278]
  PIN i_x0[279]
    DIRECTION INPUT ;
    USE SIGNAL ;
    PORT
      LAYER M5 ;
        RECT  33.264 0 33.288 0.084 ;
    END
  END i_x0[279]
  PIN i_x0[27]
    DIRECTION INPUT ;
    USE SIGNAL ;
    PORT
      LAYER M5 ;
        RECT  9.84 0 9.864 0.084 ;
    END
  END i_x0[27]
  PIN i_x0[280]
    DIRECTION INPUT ;
    USE SIGNAL ;
    PORT
      LAYER M3 ;
        RECT  33.372 0 33.39 0.038 ;
    END
  END i_x0[280]
  PIN i_x0[281]
    DIRECTION INPUT ;
    USE SIGNAL ;
    PORT
      LAYER M5 ;
        RECT  33.456 0 33.48 0.084 ;
    END
  END i_x0[281]
  PIN i_x0[282]
    DIRECTION INPUT ;
    USE SIGNAL ;
    PORT
      LAYER M3 ;
        RECT  33.552 0 33.57 0.038 ;
    END
  END i_x0[282]
  PIN i_x0[28]
    DIRECTION INPUT ;
    USE SIGNAL ;
    PORT
      LAYER M3 ;
        RECT  9.9 0 9.918 0.038 ;
    END
  END i_x0[28]
  PIN i_x0[29]
    DIRECTION INPUT ;
    USE SIGNAL ;
    PORT
      LAYER M5 ;
        RECT  9.984 0 10.008 0.084 ;
    END
  END i_x0[29]
  PIN i_x0[2]
    DIRECTION INPUT ;
    USE SIGNAL ;
    PORT
      LAYER M3 ;
        RECT  7.488 0 7.506 0.038 ;
    END
  END i_x0[2]
  PIN i_x0[30]
    DIRECTION INPUT ;
    USE SIGNAL ;
    PORT
      LAYER M3 ;
        RECT  10.08 0 10.098 0.038 ;
    END
  END i_x0[30]
  PIN i_x0[31]
    DIRECTION INPUT ;
    USE SIGNAL ;
    PORT
      LAYER M5 ;
        RECT  10.176 0 10.2 0.084 ;
    END
  END i_x0[31]
  PIN i_x0[32]
    DIRECTION INPUT ;
    USE SIGNAL ;
    PORT
      LAYER M3 ;
        RECT  10.26 0 10.278 0.038 ;
    END
  END i_x0[32]
  PIN i_x0[33]
    DIRECTION INPUT ;
    USE SIGNAL ;
    PORT
      LAYER M5 ;
        RECT  10.368 0 10.392 0.084 ;
    END
  END i_x0[33]
  PIN i_x0[34]
    DIRECTION INPUT ;
    USE SIGNAL ;
    PORT
      LAYER M3 ;
        RECT  10.476 0 10.494 0.038 ;
    END
  END i_x0[34]
  PIN i_x0[35]
    DIRECTION INPUT ;
    USE SIGNAL ;
    PORT
      LAYER M5 ;
        RECT  10.56 0 10.584 0.084 ;
    END
  END i_x0[35]
  PIN i_x0[36]
    DIRECTION INPUT ;
    USE SIGNAL ;
    PORT
      LAYER M3 ;
        RECT  10.656 0 10.674 0.038 ;
    END
  END i_x0[36]
  PIN i_x0[37]
    DIRECTION INPUT ;
    USE SIGNAL ;
    PORT
      LAYER M5 ;
        RECT  10.752 0 10.776 0.084 ;
    END
  END i_x0[37]
  PIN i_x0[38]
    DIRECTION INPUT ;
    USE SIGNAL ;
    PORT
      LAYER M3 ;
        RECT  10.836 0 10.854 0.038 ;
    END
  END i_x0[38]
  PIN i_x0[39]
    DIRECTION INPUT ;
    USE SIGNAL ;
    PORT
      LAYER M5 ;
        RECT  10.944 0 10.968 0.084 ;
    END
  END i_x0[39]
  PIN i_x0[3]
    DIRECTION INPUT ;
    USE SIGNAL ;
    PORT
      LAYER M5 ;
        RECT  7.584 0 7.608 0.084 ;
    END
  END i_x0[3]
  PIN i_x0[40]
    DIRECTION INPUT ;
    USE SIGNAL ;
    PORT
      LAYER M3 ;
        RECT  11.052 0 11.07 0.038 ;
    END
  END i_x0[40]
  PIN i_x0[41]
    DIRECTION INPUT ;
    USE SIGNAL ;
    PORT
      LAYER M5 ;
        RECT  11.136 0 11.16 0.084 ;
    END
  END i_x0[41]
  PIN i_x0[42]
    DIRECTION INPUT ;
    USE SIGNAL ;
    PORT
      LAYER M3 ;
        RECT  11.232 0 11.25 0.038 ;
    END
  END i_x0[42]
  PIN i_x0[43]
    DIRECTION INPUT ;
    USE SIGNAL ;
    PORT
      LAYER M5 ;
        RECT  11.328 0 11.352 0.084 ;
    END
  END i_x0[43]
  PIN i_x0[44]
    DIRECTION INPUT ;
    USE SIGNAL ;
    PORT
      LAYER M3 ;
        RECT  11.376 0 11.394 0.038 ;
    END
  END i_x0[44]
  PIN i_x0[45]
    DIRECTION INPUT ;
    USE SIGNAL ;
    PORT
      LAYER M5 ;
        RECT  11.472 0 11.496 0.084 ;
    END
  END i_x0[45]
  PIN i_x0[46]
    DIRECTION INPUT ;
    USE SIGNAL ;
    PORT
      LAYER M3 ;
        RECT  11.556 0 11.574 0.038 ;
    END
  END i_x0[46]
  PIN i_x0[47]
    DIRECTION INPUT ;
    USE SIGNAL ;
    PORT
      LAYER M5 ;
        RECT  11.664 0 11.688 0.084 ;
    END
  END i_x0[47]
  PIN i_x0[48]
    DIRECTION INPUT ;
    USE SIGNAL ;
    PORT
      LAYER M3 ;
        RECT  11.772 0 11.79 0.038 ;
    END
  END i_x0[48]
  PIN i_x0[49]
    DIRECTION INPUT ;
    USE SIGNAL ;
    PORT
      LAYER M5 ;
        RECT  11.856 0 11.88 0.084 ;
    END
  END i_x0[49]
  PIN i_x0[4]
    DIRECTION INPUT ;
    USE SIGNAL ;
    PORT
      LAYER M3 ;
        RECT  7.668 0 7.686 0.038 ;
    END
  END i_x0[4]
  PIN i_x0[50]
    DIRECTION INPUT ;
    USE SIGNAL ;
    PORT
      LAYER M3 ;
        RECT  11.952 0 11.97 0.038 ;
    END
  END i_x0[50]
  PIN i_x0[51]
    DIRECTION INPUT ;
    USE SIGNAL ;
    PORT
      LAYER M5 ;
        RECT  12.048 0 12.072 0.084 ;
    END
  END i_x0[51]
  PIN i_x0[52]
    DIRECTION INPUT ;
    USE SIGNAL ;
    PORT
      LAYER M3 ;
        RECT  12.132 0 12.15 0.038 ;
    END
  END i_x0[52]
  PIN i_x0[53]
    DIRECTION INPUT ;
    USE SIGNAL ;
    PORT
      LAYER M5 ;
        RECT  12.24 0 12.264 0.084 ;
    END
  END i_x0[53]
  PIN i_x0[54]
    DIRECTION INPUT ;
    USE SIGNAL ;
    PORT
      LAYER M3 ;
        RECT  12.348 0 12.366 0.038 ;
    END
  END i_x0[54]
  PIN i_x0[55]
    DIRECTION INPUT ;
    USE SIGNAL ;
    PORT
      LAYER M5 ;
        RECT  12.432 0 12.456 0.084 ;
    END
  END i_x0[55]
  PIN i_x0[56]
    DIRECTION INPUT ;
    USE SIGNAL ;
    PORT
      LAYER M3 ;
        RECT  12.528 0 12.546 0.038 ;
    END
  END i_x0[56]
  PIN i_x0[57]
    DIRECTION INPUT ;
    USE SIGNAL ;
    PORT
      LAYER M5 ;
        RECT  12.624 0 12.648 0.084 ;
    END
  END i_x0[57]
  PIN i_x0[58]
    DIRECTION INPUT ;
    USE SIGNAL ;
    PORT
      LAYER M3 ;
        RECT  12.708 0 12.726 0.038 ;
    END
  END i_x0[58]
  PIN i_x0[59]
    DIRECTION INPUT ;
    USE SIGNAL ;
    PORT
      LAYER M5 ;
        RECT  12.816 0 12.84 0.084 ;
    END
  END i_x0[59]
  PIN i_x0[5]
    DIRECTION INPUT ;
    USE SIGNAL ;
    PORT
      LAYER M5 ;
        RECT  7.776 0 7.8 0.084 ;
    END
  END i_x0[5]
  PIN i_x0[60]
    DIRECTION INPUT ;
    USE SIGNAL ;
    PORT
      LAYER M3 ;
        RECT  12.852 0 12.87 0.038 ;
    END
  END i_x0[60]
  PIN i_x0[61]
    DIRECTION INPUT ;
    USE SIGNAL ;
    PORT
      LAYER M5 ;
        RECT  12.96 0 12.984 0.084 ;
    END
  END i_x0[61]
  PIN i_x0[62]
    DIRECTION INPUT ;
    USE SIGNAL ;
    PORT
      LAYER M3 ;
        RECT  13.068 0 13.086 0.038 ;
    END
  END i_x0[62]
  PIN i_x0[63]
    DIRECTION INPUT ;
    USE SIGNAL ;
    PORT
      LAYER M5 ;
        RECT  13.152 0 13.176 0.084 ;
    END
  END i_x0[63]
  PIN i_x0[64]
    DIRECTION INPUT ;
    USE SIGNAL ;
    PORT
      LAYER M3 ;
        RECT  13.248 0 13.266 0.038 ;
    END
  END i_x0[64]
  PIN i_x0[65]
    DIRECTION INPUT ;
    USE SIGNAL ;
    PORT
      LAYER M5 ;
        RECT  13.344 0 13.368 0.084 ;
    END
  END i_x0[65]
  PIN i_x0[66]
    DIRECTION INPUT ;
    USE SIGNAL ;
    PORT
      LAYER M3 ;
        RECT  13.428 0 13.446 0.038 ;
    END
  END i_x0[66]
  PIN i_x0[67]
    DIRECTION INPUT ;
    USE SIGNAL ;
    PORT
      LAYER M5 ;
        RECT  13.536 0 13.56 0.084 ;
    END
  END i_x0[67]
  PIN i_x0[68]
    DIRECTION INPUT ;
    USE SIGNAL ;
    PORT
      LAYER M3 ;
        RECT  13.644 0 13.662 0.038 ;
    END
  END i_x0[68]
  PIN i_x0[69]
    DIRECTION INPUT ;
    USE SIGNAL ;
    PORT
      LAYER M5 ;
        RECT  13.728 0 13.752 0.084 ;
    END
  END i_x0[69]
  PIN i_x0[6]
    DIRECTION INPUT ;
    USE SIGNAL ;
    PORT
      LAYER M3 ;
        RECT  7.884 0 7.902 0.038 ;
    END
  END i_x0[6]
  PIN i_x0[70]
    DIRECTION INPUT ;
    USE SIGNAL ;
    PORT
      LAYER M3 ;
        RECT  13.824 0 13.842 0.038 ;
    END
  END i_x0[70]
  PIN i_x0[71]
    DIRECTION INPUT ;
    USE SIGNAL ;
    PORT
      LAYER M5 ;
        RECT  13.92 0 13.944 0.084 ;
    END
  END i_x0[71]
  PIN i_x0[72]
    DIRECTION INPUT ;
    USE SIGNAL ;
    PORT
      LAYER M3 ;
        RECT  14.004 0 14.022 0.038 ;
    END
  END i_x0[72]
  PIN i_x0[73]
    DIRECTION INPUT ;
    USE SIGNAL ;
    PORT
      LAYER M5 ;
        RECT  14.112 0 14.136 0.084 ;
    END
  END i_x0[73]
  PIN i_x0[74]
    DIRECTION INPUT ;
    USE SIGNAL ;
    PORT
      LAYER M3 ;
        RECT  14.22 0 14.238 0.038 ;
    END
  END i_x0[74]
  PIN i_x0[75]
    DIRECTION INPUT ;
    USE SIGNAL ;
    PORT
      LAYER M5 ;
        RECT  14.304 0 14.328 0.084 ;
    END
  END i_x0[75]
  PIN i_x0[76]
    DIRECTION INPUT ;
    USE SIGNAL ;
    PORT
      LAYER M3 ;
        RECT  14.364 0 14.382 0.038 ;
    END
  END i_x0[76]
  PIN i_x0[77]
    DIRECTION INPUT ;
    USE SIGNAL ;
    PORT
      LAYER M5 ;
        RECT  14.448 0 14.472 0.084 ;
    END
  END i_x0[77]
  PIN i_x0[78]
    DIRECTION INPUT ;
    USE SIGNAL ;
    PORT
      LAYER M3 ;
        RECT  14.544 0 14.562 0.038 ;
    END
  END i_x0[78]
  PIN i_x0[79]
    DIRECTION INPUT ;
    USE SIGNAL ;
    PORT
      LAYER M5 ;
        RECT  14.64 0 14.664 0.084 ;
    END
  END i_x0[79]
  PIN i_x0[7]
    DIRECTION INPUT ;
    USE SIGNAL ;
    PORT
      LAYER M5 ;
        RECT  7.968 0 7.992 0.084 ;
    END
  END i_x0[7]
  PIN i_x0[80]
    DIRECTION INPUT ;
    USE SIGNAL ;
    PORT
      LAYER M3 ;
        RECT  14.724 0 14.742 0.038 ;
    END
  END i_x0[80]
  PIN i_x0[81]
    DIRECTION INPUT ;
    USE SIGNAL ;
    PORT
      LAYER M5 ;
        RECT  14.832 0 14.856 0.084 ;
    END
  END i_x0[81]
  PIN i_x0[82]
    DIRECTION INPUT ;
    USE SIGNAL ;
    PORT
      LAYER M3 ;
        RECT  14.94 0 14.958 0.038 ;
    END
  END i_x0[82]
  PIN i_x0[83]
    DIRECTION INPUT ;
    USE SIGNAL ;
    PORT
      LAYER M5 ;
        RECT  15.024 0 15.048 0.084 ;
    END
  END i_x0[83]
  PIN i_x0[84]
    DIRECTION INPUT ;
    USE SIGNAL ;
    PORT
      LAYER M3 ;
        RECT  15.12 0 15.138 0.038 ;
    END
  END i_x0[84]
  PIN i_x0[85]
    DIRECTION INPUT ;
    USE SIGNAL ;
    PORT
      LAYER M5 ;
        RECT  15.216 0 15.24 0.084 ;
    END
  END i_x0[85]
  PIN i_x0[86]
    DIRECTION INPUT ;
    USE SIGNAL ;
    PORT
      LAYER M3 ;
        RECT  15.3 0 15.318 0.038 ;
    END
  END i_x0[86]
  PIN i_x0[87]
    DIRECTION INPUT ;
    USE SIGNAL ;
    PORT
      LAYER M5 ;
        RECT  15.408 0 15.432 0.084 ;
    END
  END i_x0[87]
  PIN i_x0[88]
    DIRECTION INPUT ;
    USE SIGNAL ;
    PORT
      LAYER M3 ;
        RECT  15.516 0 15.534 0.038 ;
    END
  END i_x0[88]
  PIN i_x0[89]
    DIRECTION INPUT ;
    USE SIGNAL ;
    PORT
      LAYER M5 ;
        RECT  15.6 0 15.624 0.084 ;
    END
  END i_x0[89]
  PIN i_x0[8]
    DIRECTION INPUT ;
    USE SIGNAL ;
    PORT
      LAYER M3 ;
        RECT  8.064 0 8.082 0.038 ;
    END
  END i_x0[8]
  PIN i_x0[90]
    DIRECTION INPUT ;
    USE SIGNAL ;
    PORT
      LAYER M3 ;
        RECT  15.696 0 15.714 0.038 ;
    END
  END i_x0[90]
  PIN i_x0[91]
    DIRECTION INPUT ;
    USE SIGNAL ;
    PORT
      LAYER M5 ;
        RECT  15.792 0 15.816 0.084 ;
    END
  END i_x0[91]
  PIN i_x0[92]
    DIRECTION INPUT ;
    USE SIGNAL ;
    PORT
      LAYER M3 ;
        RECT  15.84 0 15.858 0.038 ;
    END
  END i_x0[92]
  PIN i_x0[93]
    DIRECTION INPUT ;
    USE SIGNAL ;
    PORT
      LAYER M5 ;
        RECT  15.936 0 15.96 0.084 ;
    END
  END i_x0[93]
  PIN i_x0[94]
    DIRECTION INPUT ;
    USE SIGNAL ;
    PORT
      LAYER M3 ;
        RECT  16.02 0 16.038 0.038 ;
    END
  END i_x0[94]
  PIN i_x0[95]
    DIRECTION INPUT ;
    USE SIGNAL ;
    PORT
      LAYER M5 ;
        RECT  16.128 0 16.152 0.084 ;
    END
  END i_x0[95]
  PIN i_x0[96]
    DIRECTION INPUT ;
    USE SIGNAL ;
    PORT
      LAYER M3 ;
        RECT  16.236 0 16.254 0.038 ;
    END
  END i_x0[96]
  PIN i_x0[97]
    DIRECTION INPUT ;
    USE SIGNAL ;
    PORT
      LAYER M5 ;
        RECT  16.32 0 16.344 0.084 ;
    END
  END i_x0[97]
  PIN i_x0[98]
    DIRECTION INPUT ;
    USE SIGNAL ;
    PORT
      LAYER M3 ;
        RECT  16.416 0 16.434 0.038 ;
    END
  END i_x0[98]
  PIN i_x0[99]
    DIRECTION INPUT ;
    USE SIGNAL ;
    PORT
      LAYER M5 ;
        RECT  16.512 0 16.536 0.084 ;
    END
  END i_x0[99]
  PIN i_x0[9]
    DIRECTION INPUT ;
    USE SIGNAL ;
    PORT
      LAYER M5 ;
        RECT  8.16 0 8.184 0.084 ;
    END
  END i_x0[9]
  PIN i_x1[0]
    DIRECTION INPUT ;
    USE SIGNAL ;
    PORT
      LAYER M5 ;
        RECT  33.6 0 33.624 0.084 ;
    END
  END i_x1[0]
  PIN i_x1[100]
    DIRECTION INPUT ;
    USE SIGNAL ;
    PORT
      LAYER M5 ;
        RECT  42.912 0 42.936 0.084 ;
    END
  END i_x1[100]
  PIN i_x1[101]
    DIRECTION INPUT ;
    USE SIGNAL ;
    PORT
      LAYER M3 ;
        RECT  43.02 0 43.038 0.038 ;
    END
  END i_x1[101]
  PIN i_x1[102]
    DIRECTION INPUT ;
    USE SIGNAL ;
    PORT
      LAYER M5 ;
        RECT  43.104 0 43.128 0.084 ;
    END
  END i_x1[102]
  PIN i_x1[103]
    DIRECTION INPUT ;
    USE SIGNAL ;
    PORT
      LAYER M3 ;
        RECT  43.2 0 43.218 0.038 ;
    END
  END i_x1[103]
  PIN i_x1[104]
    DIRECTION INPUT ;
    USE SIGNAL ;
    PORT
      LAYER M5 ;
        RECT  43.296 0 43.32 0.084 ;
    END
  END i_x1[104]
  PIN i_x1[105]
    DIRECTION INPUT ;
    USE SIGNAL ;
    PORT
      LAYER M3 ;
        RECT  43.38 0 43.398 0.038 ;
    END
  END i_x1[105]
  PIN i_x1[106]
    DIRECTION INPUT ;
    USE SIGNAL ;
    PORT
      LAYER M5 ;
        RECT  43.488 0 43.512 0.084 ;
    END
  END i_x1[106]
  PIN i_x1[107]
    DIRECTION INPUT ;
    USE SIGNAL ;
    PORT
      LAYER M3 ;
        RECT  43.596 0 43.614 0.038 ;
    END
  END i_x1[107]
  PIN i_x1[108]
    DIRECTION INPUT ;
    USE SIGNAL ;
    PORT
      LAYER M5 ;
        RECT  43.68 0 43.704 0.084 ;
    END
  END i_x1[108]
  PIN i_x1[109]
    DIRECTION INPUT ;
    USE SIGNAL ;
    PORT
      LAYER M3 ;
        RECT  43.776 0 43.794 0.038 ;
    END
  END i_x1[109]
  PIN i_x1[10]
    DIRECTION INPUT ;
    USE SIGNAL ;
    PORT
      LAYER M5 ;
        RECT  34.56 0 34.584 0.084 ;
    END
  END i_x1[10]
  PIN i_x1[110]
    DIRECTION INPUT ;
    USE SIGNAL ;
    PORT
      LAYER M5 ;
        RECT  43.872 0 43.896 0.084 ;
    END
  END i_x1[110]
  PIN i_x1[111]
    DIRECTION INPUT ;
    USE SIGNAL ;
    PORT
      LAYER M3 ;
        RECT  43.92 0 43.938 0.038 ;
    END
  END i_x1[111]
  PIN i_x1[112]
    DIRECTION INPUT ;
    USE SIGNAL ;
    PORT
      LAYER M5 ;
        RECT  44.016 0 44.04 0.084 ;
    END
  END i_x1[112]
  PIN i_x1[113]
    DIRECTION INPUT ;
    USE SIGNAL ;
    PORT
      LAYER M3 ;
        RECT  44.1 0 44.118 0.038 ;
    END
  END i_x1[113]
  PIN i_x1[114]
    DIRECTION INPUT ;
    USE SIGNAL ;
    PORT
      LAYER M5 ;
        RECT  44.208 0 44.232 0.084 ;
    END
  END i_x1[114]
  PIN i_x1[115]
    DIRECTION INPUT ;
    USE SIGNAL ;
    PORT
      LAYER M3 ;
        RECT  44.316 0 44.334 0.038 ;
    END
  END i_x1[115]
  PIN i_x1[116]
    DIRECTION INPUT ;
    USE SIGNAL ;
    PORT
      LAYER M5 ;
        RECT  44.4 0 44.424 0.084 ;
    END
  END i_x1[116]
  PIN i_x1[117]
    DIRECTION INPUT ;
    USE SIGNAL ;
    PORT
      LAYER M3 ;
        RECT  44.496 0 44.514 0.038 ;
    END
  END i_x1[117]
  PIN i_x1[118]
    DIRECTION INPUT ;
    USE SIGNAL ;
    PORT
      LAYER M5 ;
        RECT  44.592 0 44.616 0.084 ;
    END
  END i_x1[118]
  PIN i_x1[119]
    DIRECTION INPUT ;
    USE SIGNAL ;
    PORT
      LAYER M3 ;
        RECT  44.676 0 44.694 0.038 ;
    END
  END i_x1[119]
  PIN i_x1[11]
    DIRECTION INPUT ;
    USE SIGNAL ;
    PORT
      LAYER M3 ;
        RECT  34.668 0 34.686 0.038 ;
    END
  END i_x1[11]
  PIN i_x1[120]
    DIRECTION INPUT ;
    USE SIGNAL ;
    PORT
      LAYER M5 ;
        RECT  44.784 0 44.808 0.084 ;
    END
  END i_x1[120]
  PIN i_x1[121]
    DIRECTION INPUT ;
    USE SIGNAL ;
    PORT
      LAYER M3 ;
        RECT  44.892 0 44.91 0.038 ;
    END
  END i_x1[121]
  PIN i_x1[122]
    DIRECTION INPUT ;
    USE SIGNAL ;
    PORT
      LAYER M5 ;
        RECT  44.976 0 45 0.084 ;
    END
  END i_x1[122]
  PIN i_x1[123]
    DIRECTION INPUT ;
    USE SIGNAL ;
    PORT
      LAYER M3 ;
        RECT  45.072 0 45.09 0.038 ;
    END
  END i_x1[123]
  PIN i_x1[124]
    DIRECTION INPUT ;
    USE SIGNAL ;
    PORT
      LAYER M5 ;
        RECT  45.168 0 45.192 0.084 ;
    END
  END i_x1[124]
  PIN i_x1[125]
    DIRECTION INPUT ;
    USE SIGNAL ;
    PORT
      LAYER M3 ;
        RECT  45.252 0 45.27 0.038 ;
    END
  END i_x1[125]
  PIN i_x1[126]
    DIRECTION INPUT ;
    USE SIGNAL ;
    PORT
      LAYER M5 ;
        RECT  45.36 0 45.384 0.084 ;
    END
  END i_x1[126]
  PIN i_x1[127]
    DIRECTION INPUT ;
    USE SIGNAL ;
    PORT
      LAYER M3 ;
        RECT  45.396 0 45.414 0.038 ;
    END
  END i_x1[127]
  PIN i_x1[128]
    DIRECTION INPUT ;
    USE SIGNAL ;
    PORT
      LAYER M5 ;
        RECT  45.504 0 45.528 0.084 ;
    END
  END i_x1[128]
  PIN i_x1[129]
    DIRECTION INPUT ;
    USE SIGNAL ;
    PORT
      LAYER M3 ;
        RECT  45.612 0 45.63 0.038 ;
    END
  END i_x1[129]
  PIN i_x1[12]
    DIRECTION INPUT ;
    USE SIGNAL ;
    PORT
      LAYER M5 ;
        RECT  34.752 0 34.776 0.084 ;
    END
  END i_x1[12]
  PIN i_x1[130]
    DIRECTION INPUT ;
    USE SIGNAL ;
    PORT
      LAYER M5 ;
        RECT  45.696 0 45.72 0.084 ;
    END
  END i_x1[130]
  PIN i_x1[131]
    DIRECTION INPUT ;
    USE SIGNAL ;
    PORT
      LAYER M3 ;
        RECT  45.792 0 45.81 0.038 ;
    END
  END i_x1[131]
  PIN i_x1[132]
    DIRECTION INPUT ;
    USE SIGNAL ;
    PORT
      LAYER M5 ;
        RECT  45.888 0 45.912 0.084 ;
    END
  END i_x1[132]
  PIN i_x1[133]
    DIRECTION INPUT ;
    USE SIGNAL ;
    PORT
      LAYER M3 ;
        RECT  45.972 0 45.99 0.038 ;
    END
  END i_x1[133]
  PIN i_x1[134]
    DIRECTION INPUT ;
    USE SIGNAL ;
    PORT
      LAYER M5 ;
        RECT  46.08 0 46.104 0.084 ;
    END
  END i_x1[134]
  PIN i_x1[135]
    DIRECTION INPUT ;
    USE SIGNAL ;
    PORT
      LAYER M3 ;
        RECT  46.188 0 46.206 0.038 ;
    END
  END i_x1[135]
  PIN i_x1[136]
    DIRECTION INPUT ;
    USE SIGNAL ;
    PORT
      LAYER M5 ;
        RECT  46.272 0 46.296 0.084 ;
    END
  END i_x1[136]
  PIN i_x1[137]
    DIRECTION INPUT ;
    USE SIGNAL ;
    PORT
      LAYER M3 ;
        RECT  46.368 0 46.386 0.038 ;
    END
  END i_x1[137]
  PIN i_x1[138]
    DIRECTION INPUT ;
    USE SIGNAL ;
    PORT
      LAYER M5 ;
        RECT  46.464 0 46.488 0.084 ;
    END
  END i_x1[138]
  PIN i_x1[139]
    DIRECTION INPUT ;
    USE SIGNAL ;
    PORT
      LAYER M3 ;
        RECT  46.548 0 46.566 0.038 ;
    END
  END i_x1[139]
  PIN i_x1[13]
    DIRECTION INPUT ;
    USE SIGNAL ;
    PORT
      LAYER M3 ;
        RECT  34.848 0 34.866 0.038 ;
    END
  END i_x1[13]
  PIN i_x1[140]
    DIRECTION INPUT ;
    USE SIGNAL ;
    PORT
      LAYER M5 ;
        RECT  46.656 0 46.68 0.084 ;
    END
  END i_x1[140]
  PIN i_x1[141]
    DIRECTION INPUT ;
    USE SIGNAL ;
    PORT
      LAYER M3 ;
        RECT  46.764 0 46.782 0.038 ;
    END
  END i_x1[141]
  PIN i_x1[142]
    DIRECTION INPUT ;
    USE SIGNAL ;
    PORT
      LAYER M5 ;
        RECT  46.848 0 46.872 0.084 ;
    END
  END i_x1[142]
  PIN i_x1[143]
    DIRECTION INPUT ;
    USE SIGNAL ;
    PORT
      LAYER M3 ;
        RECT  46.908 0 46.926 0.038 ;
    END
  END i_x1[143]
  PIN i_x1[144]
    DIRECTION INPUT ;
    USE SIGNAL ;
    PORT
      LAYER M5 ;
        RECT  46.992 0 47.016 0.084 ;
    END
  END i_x1[144]
  PIN i_x1[145]
    DIRECTION INPUT ;
    USE SIGNAL ;
    PORT
      LAYER M3 ;
        RECT  47.088 0 47.106 0.038 ;
    END
  END i_x1[145]
  PIN i_x1[146]
    DIRECTION INPUT ;
    USE SIGNAL ;
    PORT
      LAYER M5 ;
        RECT  47.184 0 47.208 0.084 ;
    END
  END i_x1[146]
  PIN i_x1[147]
    DIRECTION INPUT ;
    USE SIGNAL ;
    PORT
      LAYER M3 ;
        RECT  47.268 0 47.286 0.038 ;
    END
  END i_x1[147]
  PIN i_x1[148]
    DIRECTION INPUT ;
    USE SIGNAL ;
    PORT
      LAYER M5 ;
        RECT  47.376 0 47.4 0.084 ;
    END
  END i_x1[148]
  PIN i_x1[149]
    DIRECTION INPUT ;
    USE SIGNAL ;
    PORT
      LAYER M3 ;
        RECT  47.484 0 47.502 0.038 ;
    END
  END i_x1[149]
  PIN i_x1[14]
    DIRECTION INPUT ;
    USE SIGNAL ;
    PORT
      LAYER M5 ;
        RECT  34.944 0 34.968 0.084 ;
    END
  END i_x1[14]
  PIN i_x1[150]
    DIRECTION INPUT ;
    USE SIGNAL ;
    PORT
      LAYER M5 ;
        RECT  47.568 0 47.592 0.084 ;
    END
  END i_x1[150]
  PIN i_x1[151]
    DIRECTION INPUT ;
    USE SIGNAL ;
    PORT
      LAYER M3 ;
        RECT  47.664 0 47.682 0.038 ;
    END
  END i_x1[151]
  PIN i_x1[152]
    DIRECTION INPUT ;
    USE SIGNAL ;
    PORT
      LAYER M5 ;
        RECT  47.76 0 47.784 0.084 ;
    END
  END i_x1[152]
  PIN i_x1[153]
    DIRECTION INPUT ;
    USE SIGNAL ;
    PORT
      LAYER M3 ;
        RECT  47.844 0 47.862 0.038 ;
    END
  END i_x1[153]
  PIN i_x1[154]
    DIRECTION INPUT ;
    USE SIGNAL ;
    PORT
      LAYER M5 ;
        RECT  47.952 0 47.976 0.084 ;
    END
  END i_x1[154]
  PIN i_x1[155]
    DIRECTION INPUT ;
    USE SIGNAL ;
    PORT
      LAYER M3 ;
        RECT  48.06 0 48.078 0.038 ;
    END
  END i_x1[155]
  PIN i_x1[156]
    DIRECTION INPUT ;
    USE SIGNAL ;
    PORT
      LAYER M5 ;
        RECT  48.144 0 48.168 0.084 ;
    END
  END i_x1[156]
  PIN i_x1[157]
    DIRECTION INPUT ;
    USE SIGNAL ;
    PORT
      LAYER M3 ;
        RECT  48.24 0 48.258 0.038 ;
    END
  END i_x1[157]
  PIN i_x1[158]
    DIRECTION INPUT ;
    USE SIGNAL ;
    PORT
      LAYER M5 ;
        RECT  48.336 0 48.36 0.084 ;
    END
  END i_x1[158]
  PIN i_x1[159]
    DIRECTION INPUT ;
    USE SIGNAL ;
    PORT
      LAYER M3 ;
        RECT  48.384 0 48.402 0.038 ;
    END
  END i_x1[159]
  PIN i_x1[15]
    DIRECTION INPUT ;
    USE SIGNAL ;
    PORT
      LAYER M3 ;
        RECT  35.028 0 35.046 0.038 ;
    END
  END i_x1[15]
  PIN i_x1[160]
    DIRECTION INPUT ;
    USE SIGNAL ;
    PORT
      LAYER M5 ;
        RECT  48.48 0 48.504 0.084 ;
    END
  END i_x1[160]
  PIN i_x1[161]
    DIRECTION INPUT ;
    USE SIGNAL ;
    PORT
      LAYER M3 ;
        RECT  48.564 0 48.582 0.038 ;
    END
  END i_x1[161]
  PIN i_x1[162]
    DIRECTION INPUT ;
    USE SIGNAL ;
    PORT
      LAYER M5 ;
        RECT  48.672 0 48.696 0.084 ;
    END
  END i_x1[162]
  PIN i_x1[163]
    DIRECTION INPUT ;
    USE SIGNAL ;
    PORT
      LAYER M3 ;
        RECT  48.78 0 48.798 0.038 ;
    END
  END i_x1[163]
  PIN i_x1[164]
    DIRECTION INPUT ;
    USE SIGNAL ;
    PORT
      LAYER M5 ;
        RECT  48.864 0 48.888 0.084 ;
    END
  END i_x1[164]
  PIN i_x1[165]
    DIRECTION INPUT ;
    USE SIGNAL ;
    PORT
      LAYER M3 ;
        RECT  48.96 0 48.978 0.038 ;
    END
  END i_x1[165]
  PIN i_x1[166]
    DIRECTION INPUT ;
    USE SIGNAL ;
    PORT
      LAYER M5 ;
        RECT  49.056 0 49.08 0.084 ;
    END
  END i_x1[166]
  PIN i_x1[167]
    DIRECTION INPUT ;
    USE SIGNAL ;
    PORT
      LAYER M3 ;
        RECT  49.14 0 49.158 0.038 ;
    END
  END i_x1[167]
  PIN i_x1[168]
    DIRECTION INPUT ;
    USE SIGNAL ;
    PORT
      LAYER M5 ;
        RECT  49.248 0 49.272 0.084 ;
    END
  END i_x1[168]
  PIN i_x1[169]
    DIRECTION INPUT ;
    USE SIGNAL ;
    PORT
      LAYER M3 ;
        RECT  49.356 0 49.374 0.038 ;
    END
  END i_x1[169]
  PIN i_x1[16]
    DIRECTION INPUT ;
    USE SIGNAL ;
    PORT
      LAYER M5 ;
        RECT  35.088 0 35.112 0.084 ;
    END
  END i_x1[16]
  PIN i_x1[170]
    DIRECTION INPUT ;
    USE SIGNAL ;
    PORT
      LAYER M5 ;
        RECT  49.44 0 49.464 0.084 ;
    END
  END i_x1[170]
  PIN i_x1[171]
    DIRECTION INPUT ;
    USE SIGNAL ;
    PORT
      LAYER M3 ;
        RECT  49.536 0 49.554 0.038 ;
    END
  END i_x1[171]
  PIN i_x1[172]
    DIRECTION INPUT ;
    USE SIGNAL ;
    PORT
      LAYER M5 ;
        RECT  49.632 0 49.656 0.084 ;
    END
  END i_x1[172]
  PIN i_x1[173]
    DIRECTION INPUT ;
    USE SIGNAL ;
    PORT
      LAYER M3 ;
        RECT  49.716 0 49.734 0.038 ;
    END
  END i_x1[173]
  PIN i_x1[174]
    DIRECTION INPUT ;
    USE SIGNAL ;
    PORT
      LAYER M5 ;
        RECT  49.824 0 49.848 0.084 ;
    END
  END i_x1[174]
  PIN i_x1[175]
    DIRECTION INPUT ;
    USE SIGNAL ;
    PORT
      LAYER M3 ;
        RECT  49.86 0 49.878 0.038 ;
    END
  END i_x1[175]
  PIN i_x1[176]
    DIRECTION INPUT ;
    USE SIGNAL ;
    PORT
      LAYER M5 ;
        RECT  49.968 0 49.992 0.084 ;
    END
  END i_x1[176]
  PIN i_x1[177]
    DIRECTION INPUT ;
    USE SIGNAL ;
    PORT
      LAYER M3 ;
        RECT  50.076 0 50.094 0.038 ;
    END
  END i_x1[177]
  PIN i_x1[178]
    DIRECTION INPUT ;
    USE SIGNAL ;
    PORT
      LAYER M5 ;
        RECT  50.16 0 50.184 0.084 ;
    END
  END i_x1[178]
  PIN i_x1[179]
    DIRECTION INPUT ;
    USE SIGNAL ;
    PORT
      LAYER M3 ;
        RECT  50.256 0 50.274 0.038 ;
    END
  END i_x1[179]
  PIN i_x1[17]
    DIRECTION INPUT ;
    USE SIGNAL ;
    PORT
      LAYER M3 ;
        RECT  35.172 0 35.19 0.038 ;
    END
  END i_x1[17]
  PIN i_x1[180]
    DIRECTION INPUT ;
    USE SIGNAL ;
    PORT
      LAYER M5 ;
        RECT  50.352 0 50.376 0.084 ;
    END
  END i_x1[180]
  PIN i_x1[181]
    DIRECTION INPUT ;
    USE SIGNAL ;
    PORT
      LAYER M3 ;
        RECT  50.436 0 50.454 0.038 ;
    END
  END i_x1[181]
  PIN i_x1[182]
    DIRECTION INPUT ;
    USE SIGNAL ;
    PORT
      LAYER M5 ;
        RECT  50.544 0 50.568 0.084 ;
    END
  END i_x1[182]
  PIN i_x1[183]
    DIRECTION INPUT ;
    USE SIGNAL ;
    PORT
      LAYER M3 ;
        RECT  50.652 0 50.67 0.038 ;
    END
  END i_x1[183]
  PIN i_x1[184]
    DIRECTION INPUT ;
    USE SIGNAL ;
    PORT
      LAYER M5 ;
        RECT  50.736 0 50.76 0.084 ;
    END
  END i_x1[184]
  PIN i_x1[185]
    DIRECTION INPUT ;
    USE SIGNAL ;
    PORT
      LAYER M3 ;
        RECT  50.832 0 50.85 0.038 ;
    END
  END i_x1[185]
  PIN i_x1[186]
    DIRECTION INPUT ;
    USE SIGNAL ;
    PORT
      LAYER M5 ;
        RECT  50.928 0 50.952 0.084 ;
    END
  END i_x1[186]
  PIN i_x1[187]
    DIRECTION INPUT ;
    USE SIGNAL ;
    PORT
      LAYER M3 ;
        RECT  51.012 0 51.03 0.038 ;
    END
  END i_x1[187]
  PIN i_x1[188]
    DIRECTION INPUT ;
    USE SIGNAL ;
    PORT
      LAYER M5 ;
        RECT  51.12 0 51.144 0.084 ;
    END
  END i_x1[188]
  PIN i_x1[189]
    DIRECTION INPUT ;
    USE SIGNAL ;
    PORT
      LAYER M3 ;
        RECT  51.228 0 51.246 0.038 ;
    END
  END i_x1[189]
  PIN i_x1[18]
    DIRECTION INPUT ;
    USE SIGNAL ;
    PORT
      LAYER M5 ;
        RECT  35.28 0 35.304 0.084 ;
    END
  END i_x1[18]
  PIN i_x1[190]
    DIRECTION INPUT ;
    USE SIGNAL ;
    PORT
      LAYER M5 ;
        RECT  51.264 0 51.288 0.084 ;
    END
  END i_x1[190]
  PIN i_x1[191]
    DIRECTION INPUT ;
    USE SIGNAL ;
    PORT
      LAYER M3 ;
        RECT  51.372 0 51.39 0.038 ;
    END
  END i_x1[191]
  PIN i_x1[192]
    DIRECTION INPUT ;
    USE SIGNAL ;
    PORT
      LAYER M5 ;
        RECT  51.456 0 51.48 0.084 ;
    END
  END i_x1[192]
  PIN i_x1[193]
    DIRECTION INPUT ;
    USE SIGNAL ;
    PORT
      LAYER M3 ;
        RECT  51.552 0 51.57 0.038 ;
    END
  END i_x1[193]
  PIN i_x1[194]
    DIRECTION INPUT ;
    USE SIGNAL ;
    PORT
      LAYER M5 ;
        RECT  51.648 0 51.672 0.084 ;
    END
  END i_x1[194]
  PIN i_x1[195]
    DIRECTION INPUT ;
    USE SIGNAL ;
    PORT
      LAYER M3 ;
        RECT  51.732 0 51.75 0.038 ;
    END
  END i_x1[195]
  PIN i_x1[196]
    DIRECTION INPUT ;
    USE SIGNAL ;
    PORT
      LAYER M5 ;
        RECT  51.84 0 51.864 0.084 ;
    END
  END i_x1[196]
  PIN i_x1[197]
    DIRECTION INPUT ;
    USE SIGNAL ;
    PORT
      LAYER M3 ;
        RECT  51.948 0 51.966 0.038 ;
    END
  END i_x1[197]
  PIN i_x1[198]
    DIRECTION INPUT ;
    USE SIGNAL ;
    PORT
      LAYER M5 ;
        RECT  52.032 0 52.056 0.084 ;
    END
  END i_x1[198]
  PIN i_x1[199]
    DIRECTION INPUT ;
    USE SIGNAL ;
    PORT
      LAYER M3 ;
        RECT  52.128 0 52.146 0.038 ;
    END
  END i_x1[199]
  PIN i_x1[19]
    DIRECTION INPUT ;
    USE SIGNAL ;
    PORT
      LAYER M3 ;
        RECT  35.388 0 35.406 0.038 ;
    END
  END i_x1[19]
  PIN i_x1[1]
    DIRECTION INPUT ;
    USE SIGNAL ;
    PORT
      LAYER M3 ;
        RECT  33.696 0 33.714 0.038 ;
    END
  END i_x1[1]
  PIN i_x1[200]
    DIRECTION INPUT ;
    USE SIGNAL ;
    PORT
      LAYER M5 ;
        RECT  52.224 0 52.248 0.084 ;
    END
  END i_x1[200]
  PIN i_x1[201]
    DIRECTION INPUT ;
    USE SIGNAL ;
    PORT
      LAYER M3 ;
        RECT  52.308 0 52.326 0.038 ;
    END
  END i_x1[201]
  PIN i_x1[202]
    DIRECTION INPUT ;
    USE SIGNAL ;
    PORT
      LAYER M5 ;
        RECT  52.416 0 52.44 0.084 ;
    END
  END i_x1[202]
  PIN i_x1[203]
    DIRECTION INPUT ;
    USE SIGNAL ;
    PORT
      LAYER M3 ;
        RECT  52.524 0 52.542 0.038 ;
    END
  END i_x1[203]
  PIN i_x1[204]
    DIRECTION INPUT ;
    USE SIGNAL ;
    PORT
      LAYER M5 ;
        RECT  52.608 0 52.632 0.084 ;
    END
  END i_x1[204]
  PIN i_x1[205]
    DIRECTION INPUT ;
    USE SIGNAL ;
    PORT
      LAYER M3 ;
        RECT  52.704 0 52.722 0.038 ;
    END
  END i_x1[205]
  PIN i_x1[206]
    DIRECTION INPUT ;
    USE SIGNAL ;
    PORT
      LAYER M5 ;
        RECT  52.752 0 52.776 0.084 ;
    END
  END i_x1[206]
  PIN i_x1[207]
    DIRECTION INPUT ;
    USE SIGNAL ;
    PORT
      LAYER M3 ;
        RECT  52.848 0 52.866 0.038 ;
    END
  END i_x1[207]
  PIN i_x1[208]
    DIRECTION INPUT ;
    USE SIGNAL ;
    PORT
      LAYER M5 ;
        RECT  52.944 0 52.968 0.084 ;
    END
  END i_x1[208]
  PIN i_x1[209]
    DIRECTION INPUT ;
    USE SIGNAL ;
    PORT
      LAYER M3 ;
        RECT  53.028 0 53.046 0.038 ;
    END
  END i_x1[209]
  PIN i_x1[20]
    DIRECTION INPUT ;
    USE SIGNAL ;
    PORT
      LAYER M5 ;
        RECT  35.472 0 35.496 0.084 ;
    END
  END i_x1[20]
  PIN i_x1[210]
    DIRECTION INPUT ;
    USE SIGNAL ;
    PORT
      LAYER M5 ;
        RECT  53.136 0 53.16 0.084 ;
    END
  END i_x1[210]
  PIN i_x1[211]
    DIRECTION INPUT ;
    USE SIGNAL ;
    PORT
      LAYER M3 ;
        RECT  53.244 0 53.262 0.038 ;
    END
  END i_x1[211]
  PIN i_x1[212]
    DIRECTION INPUT ;
    USE SIGNAL ;
    PORT
      LAYER M5 ;
        RECT  53.328 0 53.352 0.084 ;
    END
  END i_x1[212]
  PIN i_x1[213]
    DIRECTION INPUT ;
    USE SIGNAL ;
    PORT
      LAYER M3 ;
        RECT  53.424 0 53.442 0.038 ;
    END
  END i_x1[213]
  PIN i_x1[214]
    DIRECTION INPUT ;
    USE SIGNAL ;
    PORT
      LAYER M5 ;
        RECT  53.52 0 53.544 0.084 ;
    END
  END i_x1[214]
  PIN i_x1[215]
    DIRECTION INPUT ;
    USE SIGNAL ;
    PORT
      LAYER M3 ;
        RECT  53.604 0 53.622 0.038 ;
    END
  END i_x1[215]
  PIN i_x1[216]
    DIRECTION INPUT ;
    USE SIGNAL ;
    PORT
      LAYER M5 ;
        RECT  53.712 0 53.736 0.084 ;
    END
  END i_x1[216]
  PIN i_x1[217]
    DIRECTION INPUT ;
    USE SIGNAL ;
    PORT
      LAYER M3 ;
        RECT  53.82 0 53.838 0.038 ;
    END
  END i_x1[217]
  PIN i_x1[218]
    DIRECTION INPUT ;
    USE SIGNAL ;
    PORT
      LAYER M5 ;
        RECT  53.904 0 53.928 0.084 ;
    END
  END i_x1[218]
  PIN i_x1[219]
    DIRECTION INPUT ;
    USE SIGNAL ;
    PORT
      LAYER M3 ;
        RECT  54 0 54.018 0.038 ;
    END
  END i_x1[219]
  PIN i_x1[21]
    DIRECTION INPUT ;
    USE SIGNAL ;
    PORT
      LAYER M3 ;
        RECT  35.568 0 35.586 0.038 ;
    END
  END i_x1[21]
  PIN i_x1[220]
    DIRECTION INPUT ;
    USE SIGNAL ;
    PORT
      LAYER M5 ;
        RECT  54.096 0 54.12 0.084 ;
    END
  END i_x1[220]
  PIN i_x1[221]
    DIRECTION INPUT ;
    USE SIGNAL ;
    PORT
      LAYER M3 ;
        RECT  54.18 0 54.198 0.038 ;
    END
  END i_x1[221]
  PIN i_x1[222]
    DIRECTION INPUT ;
    USE SIGNAL ;
    PORT
      LAYER M5 ;
        RECT  54.24 0 54.264 0.084 ;
    END
  END i_x1[222]
  PIN i_x1[223]
    DIRECTION INPUT ;
    USE SIGNAL ;
    PORT
      LAYER M3 ;
        RECT  54.324 0 54.342 0.038 ;
    END
  END i_x1[223]
  PIN i_x1[224]
    DIRECTION INPUT ;
    USE SIGNAL ;
    PORT
      LAYER M5 ;
        RECT  54.432 0 54.456 0.084 ;
    END
  END i_x1[224]
  PIN i_x1[225]
    DIRECTION INPUT ;
    USE SIGNAL ;
    PORT
      LAYER M3 ;
        RECT  54.54 0 54.558 0.038 ;
    END
  END i_x1[225]
  PIN i_x1[226]
    DIRECTION INPUT ;
    USE SIGNAL ;
    PORT
      LAYER M5 ;
        RECT  54.624 0 54.648 0.084 ;
    END
  END i_x1[226]
  PIN i_x1[227]
    DIRECTION INPUT ;
    USE SIGNAL ;
    PORT
      LAYER M3 ;
        RECT  54.72 0 54.738 0.038 ;
    END
  END i_x1[227]
  PIN i_x1[228]
    DIRECTION INPUT ;
    USE SIGNAL ;
    PORT
      LAYER M5 ;
        RECT  54.816 0 54.84 0.084 ;
    END
  END i_x1[228]
  PIN i_x1[229]
    DIRECTION INPUT ;
    USE SIGNAL ;
    PORT
      LAYER M3 ;
        RECT  54.9 0 54.918 0.038 ;
    END
  END i_x1[229]
  PIN i_x1[22]
    DIRECTION INPUT ;
    USE SIGNAL ;
    PORT
      LAYER M5 ;
        RECT  35.664 0 35.688 0.084 ;
    END
  END i_x1[22]
  PIN i_x1[230]
    DIRECTION INPUT ;
    USE SIGNAL ;
    PORT
      LAYER M5 ;
        RECT  55.008 0 55.032 0.084 ;
    END
  END i_x1[230]
  PIN i_x1[231]
    DIRECTION INPUT ;
    USE SIGNAL ;
    PORT
      LAYER M3 ;
        RECT  55.116 0 55.134 0.038 ;
    END
  END i_x1[231]
  PIN i_x1[232]
    DIRECTION INPUT ;
    USE SIGNAL ;
    PORT
      LAYER M5 ;
        RECT  55.2 0 55.224 0.084 ;
    END
  END i_x1[232]
  PIN i_x1[233]
    DIRECTION INPUT ;
    USE SIGNAL ;
    PORT
      LAYER M3 ;
        RECT  55.296 0 55.314 0.038 ;
    END
  END i_x1[233]
  PIN i_x1[234]
    DIRECTION INPUT ;
    USE SIGNAL ;
    PORT
      LAYER M5 ;
        RECT  55.392 0 55.416 0.084 ;
    END
  END i_x1[234]
  PIN i_x1[235]
    DIRECTION INPUT ;
    USE SIGNAL ;
    PORT
      LAYER M3 ;
        RECT  55.476 0 55.494 0.038 ;
    END
  END i_x1[235]
  PIN i_x1[236]
    DIRECTION INPUT ;
    USE SIGNAL ;
    PORT
      LAYER M5 ;
        RECT  55.584 0 55.608 0.084 ;
    END
  END i_x1[236]
  PIN i_x1[237]
    DIRECTION INPUT ;
    USE SIGNAL ;
    PORT
      LAYER M3 ;
        RECT  55.692 0 55.71 0.038 ;
    END
  END i_x1[237]
  PIN i_x1[238]
    DIRECTION INPUT ;
    USE SIGNAL ;
    PORT
      LAYER M5 ;
        RECT  55.728 0 55.752 0.084 ;
    END
  END i_x1[238]
  PIN i_x1[239]
    DIRECTION INPUT ;
    USE SIGNAL ;
    PORT
      LAYER M3 ;
        RECT  55.836 0 55.854 0.038 ;
    END
  END i_x1[239]
  PIN i_x1[23]
    DIRECTION INPUT ;
    USE SIGNAL ;
    PORT
      LAYER M3 ;
        RECT  35.748 0 35.766 0.038 ;
    END
  END i_x1[23]
  PIN i_x1[240]
    DIRECTION INPUT ;
    USE SIGNAL ;
    PORT
      LAYER M5 ;
        RECT  55.92 0 55.944 0.084 ;
    END
  END i_x1[240]
  PIN i_x1[241]
    DIRECTION INPUT ;
    USE SIGNAL ;
    PORT
      LAYER M3 ;
        RECT  56.016 0 56.034 0.038 ;
    END
  END i_x1[241]
  PIN i_x1[242]
    DIRECTION INPUT ;
    USE SIGNAL ;
    PORT
      LAYER M5 ;
        RECT  56.112 0 56.136 0.084 ;
    END
  END i_x1[242]
  PIN i_x1[243]
    DIRECTION INPUT ;
    USE SIGNAL ;
    PORT
      LAYER M3 ;
        RECT  56.196 0 56.214 0.038 ;
    END
  END i_x1[243]
  PIN i_x1[244]
    DIRECTION INPUT ;
    USE SIGNAL ;
    PORT
      LAYER M5 ;
        RECT  56.304 0 56.328 0.084 ;
    END
  END i_x1[244]
  PIN i_x1[245]
    DIRECTION INPUT ;
    USE SIGNAL ;
    PORT
      LAYER M3 ;
        RECT  56.412 0 56.43 0.038 ;
    END
  END i_x1[245]
  PIN i_x1[246]
    DIRECTION INPUT ;
    USE SIGNAL ;
    PORT
      LAYER M5 ;
        RECT  56.496 0 56.52 0.084 ;
    END
  END i_x1[246]
  PIN i_x1[247]
    DIRECTION INPUT ;
    USE SIGNAL ;
    PORT
      LAYER M3 ;
        RECT  56.592 0 56.61 0.038 ;
    END
  END i_x1[247]
  PIN i_x1[248]
    DIRECTION INPUT ;
    USE SIGNAL ;
    PORT
      LAYER M5 ;
        RECT  56.688 0 56.712 0.084 ;
    END
  END i_x1[248]
  PIN i_x1[249]
    DIRECTION INPUT ;
    USE SIGNAL ;
    PORT
      LAYER M3 ;
        RECT  56.772 0 56.79 0.038 ;
    END
  END i_x1[249]
  PIN i_x1[24]
    DIRECTION INPUT ;
    USE SIGNAL ;
    PORT
      LAYER M5 ;
        RECT  35.856 0 35.88 0.084 ;
    END
  END i_x1[24]
  PIN i_x1[250]
    DIRECTION INPUT ;
    USE SIGNAL ;
    PORT
      LAYER M5 ;
        RECT  56.88 0 56.904 0.084 ;
    END
  END i_x1[250]
  PIN i_x1[251]
    DIRECTION INPUT ;
    USE SIGNAL ;
    PORT
      LAYER M3 ;
        RECT  56.988 0 57.006 0.038 ;
    END
  END i_x1[251]
  PIN i_x1[252]
    DIRECTION INPUT ;
    USE SIGNAL ;
    PORT
      LAYER M5 ;
        RECT  57.072 0 57.096 0.084 ;
    END
  END i_x1[252]
  PIN i_x1[253]
    DIRECTION INPUT ;
    USE SIGNAL ;
    PORT
      LAYER M3 ;
        RECT  57.168 0 57.186 0.038 ;
    END
  END i_x1[253]
  PIN i_x1[254]
    DIRECTION INPUT ;
    USE SIGNAL ;
    PORT
      LAYER M5 ;
        RECT  57.216 0 57.24 0.084 ;
    END
  END i_x1[254]
  PIN i_x1[255]
    DIRECTION INPUT ;
    USE SIGNAL ;
    PORT
      LAYER M3 ;
        RECT  57.312 0 57.33 0.038 ;
    END
  END i_x1[255]
  PIN i_x1[256]
    DIRECTION INPUT ;
    USE SIGNAL ;
    PORT
      LAYER M5 ;
        RECT  57.408 0 57.432 0.084 ;
    END
  END i_x1[256]
  PIN i_x1[257]
    DIRECTION INPUT ;
    USE SIGNAL ;
    PORT
      LAYER M3 ;
        RECT  57.492 0 57.51 0.038 ;
    END
  END i_x1[257]
  PIN i_x1[258]
    DIRECTION INPUT ;
    USE SIGNAL ;
    PORT
      LAYER M5 ;
        RECT  57.6 0 57.624 0.084 ;
    END
  END i_x1[258]
  PIN i_x1[259]
    DIRECTION INPUT ;
    USE SIGNAL ;
    PORT
      LAYER M3 ;
        RECT  57.708 0 57.726 0.038 ;
    END
  END i_x1[259]
  PIN i_x1[25]
    DIRECTION INPUT ;
    USE SIGNAL ;
    PORT
      LAYER M3 ;
        RECT  35.964 0 35.982 0.038 ;
    END
  END i_x1[25]
  PIN i_x1[260]
    DIRECTION INPUT ;
    USE SIGNAL ;
    PORT
      LAYER M5 ;
        RECT  57.792 0 57.816 0.084 ;
    END
  END i_x1[260]
  PIN i_x1[261]
    DIRECTION INPUT ;
    USE SIGNAL ;
    PORT
      LAYER M3 ;
        RECT  57.888 0 57.906 0.038 ;
    END
  END i_x1[261]
  PIN i_x1[262]
    DIRECTION INPUT ;
    USE SIGNAL ;
    PORT
      LAYER M5 ;
        RECT  57.984 0 58.008 0.084 ;
    END
  END i_x1[262]
  PIN i_x1[263]
    DIRECTION INPUT ;
    USE SIGNAL ;
    PORT
      LAYER M3 ;
        RECT  58.068 0 58.086 0.038 ;
    END
  END i_x1[263]
  PIN i_x1[264]
    DIRECTION INPUT ;
    USE SIGNAL ;
    PORT
      LAYER M5 ;
        RECT  58.176 0 58.2 0.084 ;
    END
  END i_x1[264]
  PIN i_x1[265]
    DIRECTION INPUT ;
    USE SIGNAL ;
    PORT
      LAYER M3 ;
        RECT  58.284 0 58.302 0.038 ;
    END
  END i_x1[265]
  PIN i_x1[26]
    DIRECTION INPUT ;
    USE SIGNAL ;
    PORT
      LAYER M5 ;
        RECT  36.048 0 36.072 0.084 ;
    END
  END i_x1[26]
  PIN i_x1[27]
    DIRECTION INPUT ;
    USE SIGNAL ;
    PORT
      LAYER M3 ;
        RECT  36.144 0 36.162 0.038 ;
    END
  END i_x1[27]
  PIN i_x1[28]
    DIRECTION INPUT ;
    USE SIGNAL ;
    PORT
      LAYER M5 ;
        RECT  36.24 0 36.264 0.084 ;
    END
  END i_x1[28]
  PIN i_x1[29]
    DIRECTION INPUT ;
    USE SIGNAL ;
    PORT
      LAYER M3 ;
        RECT  36.324 0 36.342 0.038 ;
    END
  END i_x1[29]
  PIN i_x1[2]
    DIRECTION INPUT ;
    USE SIGNAL ;
    PORT
      LAYER M5 ;
        RECT  33.792 0 33.816 0.084 ;
    END
  END i_x1[2]
  PIN i_x1[30]
    DIRECTION INPUT ;
    USE SIGNAL ;
    PORT
      LAYER M5 ;
        RECT  36.432 0 36.456 0.084 ;
    END
  END i_x1[30]
  PIN i_x1[31]
    DIRECTION INPUT ;
    USE SIGNAL ;
    PORT
      LAYER M3 ;
        RECT  36.54 0 36.558 0.038 ;
    END
  END i_x1[31]
  PIN i_x1[32]
    DIRECTION INPUT ;
    USE SIGNAL ;
    PORT
      LAYER M5 ;
        RECT  36.576 0 36.6 0.084 ;
    END
  END i_x1[32]
  PIN i_x1[33]
    DIRECTION INPUT ;
    USE SIGNAL ;
    PORT
      LAYER M3 ;
        RECT  36.684 0 36.702 0.038 ;
    END
  END i_x1[33]
  PIN i_x1[34]
    DIRECTION INPUT ;
    USE SIGNAL ;
    PORT
      LAYER M5 ;
        RECT  36.768 0 36.792 0.084 ;
    END
  END i_x1[34]
  PIN i_x1[35]
    DIRECTION INPUT ;
    USE SIGNAL ;
    PORT
      LAYER M3 ;
        RECT  36.864 0 36.882 0.038 ;
    END
  END i_x1[35]
  PIN i_x1[36]
    DIRECTION INPUT ;
    USE SIGNAL ;
    PORT
      LAYER M5 ;
        RECT  36.96 0 36.984 0.084 ;
    END
  END i_x1[36]
  PIN i_x1[37]
    DIRECTION INPUT ;
    USE SIGNAL ;
    PORT
      LAYER M3 ;
        RECT  37.044 0 37.062 0.038 ;
    END
  END i_x1[37]
  PIN i_x1[38]
    DIRECTION INPUT ;
    USE SIGNAL ;
    PORT
      LAYER M5 ;
        RECT  37.152 0 37.176 0.084 ;
    END
  END i_x1[38]
  PIN i_x1[39]
    DIRECTION INPUT ;
    USE SIGNAL ;
    PORT
      LAYER M3 ;
        RECT  37.26 0 37.278 0.038 ;
    END
  END i_x1[39]
  PIN i_x1[3]
    DIRECTION INPUT ;
    USE SIGNAL ;
    PORT
      LAYER M3 ;
        RECT  33.876 0 33.894 0.038 ;
    END
  END i_x1[3]
  PIN i_x1[40]
    DIRECTION INPUT ;
    USE SIGNAL ;
    PORT
      LAYER M5 ;
        RECT  37.344 0 37.368 0.084 ;
    END
  END i_x1[40]
  PIN i_x1[41]
    DIRECTION INPUT ;
    USE SIGNAL ;
    PORT
      LAYER M3 ;
        RECT  37.44 0 37.458 0.038 ;
    END
  END i_x1[41]
  PIN i_x1[42]
    DIRECTION INPUT ;
    USE SIGNAL ;
    PORT
      LAYER M5 ;
        RECT  37.536 0 37.56 0.084 ;
    END
  END i_x1[42]
  PIN i_x1[43]
    DIRECTION INPUT ;
    USE SIGNAL ;
    PORT
      LAYER M3 ;
        RECT  37.62 0 37.638 0.038 ;
    END
  END i_x1[43]
  PIN i_x1[44]
    DIRECTION INPUT ;
    USE SIGNAL ;
    PORT
      LAYER M5 ;
        RECT  37.728 0 37.752 0.084 ;
    END
  END i_x1[44]
  PIN i_x1[45]
    DIRECTION INPUT ;
    USE SIGNAL ;
    PORT
      LAYER M3 ;
        RECT  37.836 0 37.854 0.038 ;
    END
  END i_x1[45]
  PIN i_x1[46]
    DIRECTION INPUT ;
    USE SIGNAL ;
    PORT
      LAYER M5 ;
        RECT  37.92 0 37.944 0.084 ;
    END
  END i_x1[46]
  PIN i_x1[47]
    DIRECTION INPUT ;
    USE SIGNAL ;
    PORT
      LAYER M3 ;
        RECT  37.98 0 37.998 0.038 ;
    END
  END i_x1[47]
  PIN i_x1[48]
    DIRECTION INPUT ;
    USE SIGNAL ;
    PORT
      LAYER M5 ;
        RECT  38.064 0 38.088 0.084 ;
    END
  END i_x1[48]
  PIN i_x1[49]
    DIRECTION INPUT ;
    USE SIGNAL ;
    PORT
      LAYER M3 ;
        RECT  38.16 0 38.178 0.038 ;
    END
  END i_x1[49]
  PIN i_x1[4]
    DIRECTION INPUT ;
    USE SIGNAL ;
    PORT
      LAYER M5 ;
        RECT  33.984 0 34.008 0.084 ;
    END
  END i_x1[4]
  PIN i_x1[50]
    DIRECTION INPUT ;
    USE SIGNAL ;
    PORT
      LAYER M5 ;
        RECT  38.256 0 38.28 0.084 ;
    END
  END i_x1[50]
  PIN i_x1[51]
    DIRECTION INPUT ;
    USE SIGNAL ;
    PORT
      LAYER M3 ;
        RECT  38.34 0 38.358 0.038 ;
    END
  END i_x1[51]
  PIN i_x1[52]
    DIRECTION INPUT ;
    USE SIGNAL ;
    PORT
      LAYER M5 ;
        RECT  38.448 0 38.472 0.084 ;
    END
  END i_x1[52]
  PIN i_x1[53]
    DIRECTION INPUT ;
    USE SIGNAL ;
    PORT
      LAYER M3 ;
        RECT  38.556 0 38.574 0.038 ;
    END
  END i_x1[53]
  PIN i_x1[54]
    DIRECTION INPUT ;
    USE SIGNAL ;
    PORT
      LAYER M5 ;
        RECT  38.64 0 38.664 0.084 ;
    END
  END i_x1[54]
  PIN i_x1[55]
    DIRECTION INPUT ;
    USE SIGNAL ;
    PORT
      LAYER M3 ;
        RECT  38.736 0 38.754 0.038 ;
    END
  END i_x1[55]
  PIN i_x1[56]
    DIRECTION INPUT ;
    USE SIGNAL ;
    PORT
      LAYER M5 ;
        RECT  38.832 0 38.856 0.084 ;
    END
  END i_x1[56]
  PIN i_x1[57]
    DIRECTION INPUT ;
    USE SIGNAL ;
    PORT
      LAYER M3 ;
        RECT  38.916 0 38.934 0.038 ;
    END
  END i_x1[57]
  PIN i_x1[58]
    DIRECTION INPUT ;
    USE SIGNAL ;
    PORT
      LAYER M5 ;
        RECT  39.024 0 39.048 0.084 ;
    END
  END i_x1[58]
  PIN i_x1[59]
    DIRECTION INPUT ;
    USE SIGNAL ;
    PORT
      LAYER M3 ;
        RECT  39.132 0 39.15 0.038 ;
    END
  END i_x1[59]
  PIN i_x1[5]
    DIRECTION INPUT ;
    USE SIGNAL ;
    PORT
      LAYER M3 ;
        RECT  34.092 0 34.11 0.038 ;
    END
  END i_x1[5]
  PIN i_x1[60]
    DIRECTION INPUT ;
    USE SIGNAL ;
    PORT
      LAYER M5 ;
        RECT  39.216 0 39.24 0.084 ;
    END
  END i_x1[60]
  PIN i_x1[61]
    DIRECTION INPUT ;
    USE SIGNAL ;
    PORT
      LAYER M3 ;
        RECT  39.312 0 39.33 0.038 ;
    END
  END i_x1[61]
  PIN i_x1[62]
    DIRECTION INPUT ;
    USE SIGNAL ;
    PORT
      LAYER M5 ;
        RECT  39.408 0 39.432 0.084 ;
    END
  END i_x1[62]
  PIN i_x1[63]
    DIRECTION INPUT ;
    USE SIGNAL ;
    PORT
      LAYER M3 ;
        RECT  39.456 0 39.474 0.038 ;
    END
  END i_x1[63]
  PIN i_x1[64]
    DIRECTION INPUT ;
    USE SIGNAL ;
    PORT
      LAYER M5 ;
        RECT  39.552 0 39.576 0.084 ;
    END
  END i_x1[64]
  PIN i_x1[65]
    DIRECTION INPUT ;
    USE SIGNAL ;
    PORT
      LAYER M3 ;
        RECT  39.636 0 39.654 0.038 ;
    END
  END i_x1[65]
  PIN i_x1[66]
    DIRECTION INPUT ;
    USE SIGNAL ;
    PORT
      LAYER M5 ;
        RECT  39.744 0 39.768 0.084 ;
    END
  END i_x1[66]
  PIN i_x1[67]
    DIRECTION INPUT ;
    USE SIGNAL ;
    PORT
      LAYER M3 ;
        RECT  39.852 0 39.87 0.038 ;
    END
  END i_x1[67]
  PIN i_x1[68]
    DIRECTION INPUT ;
    USE SIGNAL ;
    PORT
      LAYER M5 ;
        RECT  39.936 0 39.96 0.084 ;
    END
  END i_x1[68]
  PIN i_x1[69]
    DIRECTION INPUT ;
    USE SIGNAL ;
    PORT
      LAYER M3 ;
        RECT  40.032 0 40.05 0.038 ;
    END
  END i_x1[69]
  PIN i_x1[6]
    DIRECTION INPUT ;
    USE SIGNAL ;
    PORT
      LAYER M5 ;
        RECT  34.176 0 34.2 0.084 ;
    END
  END i_x1[6]
  PIN i_x1[70]
    DIRECTION INPUT ;
    USE SIGNAL ;
    PORT
      LAYER M5 ;
        RECT  40.128 0 40.152 0.084 ;
    END
  END i_x1[70]
  PIN i_x1[71]
    DIRECTION INPUT ;
    USE SIGNAL ;
    PORT
      LAYER M3 ;
        RECT  40.212 0 40.23 0.038 ;
    END
  END i_x1[71]
  PIN i_x1[72]
    DIRECTION INPUT ;
    USE SIGNAL ;
    PORT
      LAYER M5 ;
        RECT  40.32 0 40.344 0.084 ;
    END
  END i_x1[72]
  PIN i_x1[73]
    DIRECTION INPUT ;
    USE SIGNAL ;
    PORT
      LAYER M3 ;
        RECT  40.428 0 40.446 0.038 ;
    END
  END i_x1[73]
  PIN i_x1[74]
    DIRECTION INPUT ;
    USE SIGNAL ;
    PORT
      LAYER M5 ;
        RECT  40.512 0 40.536 0.084 ;
    END
  END i_x1[74]
  PIN i_x1[75]
    DIRECTION INPUT ;
    USE SIGNAL ;
    PORT
      LAYER M3 ;
        RECT  40.608 0 40.626 0.038 ;
    END
  END i_x1[75]
  PIN i_x1[76]
    DIRECTION INPUT ;
    USE SIGNAL ;
    PORT
      LAYER M5 ;
        RECT  40.704 0 40.728 0.084 ;
    END
  END i_x1[76]
  PIN i_x1[77]
    DIRECTION INPUT ;
    USE SIGNAL ;
    PORT
      LAYER M3 ;
        RECT  40.788 0 40.806 0.038 ;
    END
  END i_x1[77]
  PIN i_x1[78]
    DIRECTION INPUT ;
    USE SIGNAL ;
    PORT
      LAYER M5 ;
        RECT  40.896 0 40.92 0.084 ;
    END
  END i_x1[78]
  PIN i_x1[79]
    DIRECTION INPUT ;
    USE SIGNAL ;
    PORT
      LAYER M3 ;
        RECT  40.932 0 40.95 0.038 ;
    END
  END i_x1[79]
  PIN i_x1[7]
    DIRECTION INPUT ;
    USE SIGNAL ;
    PORT
      LAYER M3 ;
        RECT  34.272 0 34.29 0.038 ;
    END
  END i_x1[7]
  PIN i_x1[80]
    DIRECTION INPUT ;
    USE SIGNAL ;
    PORT
      LAYER M5 ;
        RECT  41.04 0 41.064 0.084 ;
    END
  END i_x1[80]
  PIN i_x1[81]
    DIRECTION INPUT ;
    USE SIGNAL ;
    PORT
      LAYER M3 ;
        RECT  41.148 0 41.166 0.038 ;
    END
  END i_x1[81]
  PIN i_x1[82]
    DIRECTION INPUT ;
    USE SIGNAL ;
    PORT
      LAYER M5 ;
        RECT  41.232 0 41.256 0.084 ;
    END
  END i_x1[82]
  PIN i_x1[83]
    DIRECTION INPUT ;
    USE SIGNAL ;
    PORT
      LAYER M3 ;
        RECT  41.328 0 41.346 0.038 ;
    END
  END i_x1[83]
  PIN i_x1[84]
    DIRECTION INPUT ;
    USE SIGNAL ;
    PORT
      LAYER M5 ;
        RECT  41.424 0 41.448 0.084 ;
    END
  END i_x1[84]
  PIN i_x1[85]
    DIRECTION INPUT ;
    USE SIGNAL ;
    PORT
      LAYER M3 ;
        RECT  41.508 0 41.526 0.038 ;
    END
  END i_x1[85]
  PIN i_x1[86]
    DIRECTION INPUT ;
    USE SIGNAL ;
    PORT
      LAYER M5 ;
        RECT  41.616 0 41.64 0.084 ;
    END
  END i_x1[86]
  PIN i_x1[87]
    DIRECTION INPUT ;
    USE SIGNAL ;
    PORT
      LAYER M3 ;
        RECT  41.724 0 41.742 0.038 ;
    END
  END i_x1[87]
  PIN i_x1[88]
    DIRECTION INPUT ;
    USE SIGNAL ;
    PORT
      LAYER M5 ;
        RECT  41.808 0 41.832 0.084 ;
    END
  END i_x1[88]
  PIN i_x1[89]
    DIRECTION INPUT ;
    USE SIGNAL ;
    PORT
      LAYER M3 ;
        RECT  41.904 0 41.922 0.038 ;
    END
  END i_x1[89]
  PIN i_x1[8]
    DIRECTION INPUT ;
    USE SIGNAL ;
    PORT
      LAYER M5 ;
        RECT  34.368 0 34.392 0.084 ;
    END
  END i_x1[8]
  PIN i_x1[90]
    DIRECTION INPUT ;
    USE SIGNAL ;
    PORT
      LAYER M5 ;
        RECT  42 0 42.024 0.084 ;
    END
  END i_x1[90]
  PIN i_x1[91]
    DIRECTION INPUT ;
    USE SIGNAL ;
    PORT
      LAYER M3 ;
        RECT  42.084 0 42.102 0.038 ;
    END
  END i_x1[91]
  PIN i_x1[92]
    DIRECTION INPUT ;
    USE SIGNAL ;
    PORT
      LAYER M5 ;
        RECT  42.192 0 42.216 0.084 ;
    END
  END i_x1[92]
  PIN i_x1[93]
    DIRECTION INPUT ;
    USE SIGNAL ;
    PORT
      LAYER M3 ;
        RECT  42.3 0 42.318 0.038 ;
    END
  END i_x1[93]
  PIN i_x1[94]
    DIRECTION INPUT ;
    USE SIGNAL ;
    PORT
      LAYER M5 ;
        RECT  42.384 0 42.408 0.084 ;
    END
  END i_x1[94]
  PIN i_x1[95]
    DIRECTION INPUT ;
    USE SIGNAL ;
    PORT
      LAYER M3 ;
        RECT  42.444 0 42.462 0.038 ;
    END
  END i_x1[95]
  PIN i_x1[96]
    DIRECTION INPUT ;
    USE SIGNAL ;
    PORT
      LAYER M5 ;
        RECT  42.528 0 42.552 0.084 ;
    END
  END i_x1[96]
  PIN i_x1[97]
    DIRECTION INPUT ;
    USE SIGNAL ;
    PORT
      LAYER M3 ;
        RECT  42.624 0 42.642 0.038 ;
    END
  END i_x1[97]
  PIN i_x1[98]
    DIRECTION INPUT ;
    USE SIGNAL ;
    PORT
      LAYER M5 ;
        RECT  42.72 0 42.744 0.084 ;
    END
  END i_x1[98]
  PIN i_x1[99]
    DIRECTION INPUT ;
    USE SIGNAL ;
    PORT
      LAYER M3 ;
        RECT  42.804 0 42.822 0.038 ;
    END
  END i_x1[99]
  PIN i_x1[9]
    DIRECTION INPUT ;
    USE SIGNAL ;
    PORT
      LAYER M3 ;
        RECT  34.452 0 34.47 0.038 ;
    END
  END i_x1[9]
  PIN o_cfg[0]
    DIRECTION OUTPUT ;
    USE SIGNAL ;
    PORT
      LAYER M5 ;
        RECT  2.208 25.836 2.232 25.92 ;
    END
  END o_cfg[0]
  PIN o_cfg[10]
    DIRECTION OUTPUT ;
    USE SIGNAL ;
    PORT
      LAYER M5 ;
        RECT  3.12 25.836 3.144 25.92 ;
    END
  END o_cfg[10]
  PIN o_cfg[11]
    DIRECTION OUTPUT ;
    USE SIGNAL ;
    PORT
      LAYER M3 ;
        RECT  3.204 25.882 3.222 25.92 ;
    END
  END o_cfg[11]
  PIN o_cfg[12]
    DIRECTION OUTPUT ;
    USE SIGNAL ;
    PORT
      LAYER M5 ;
        RECT  3.312 25.836 3.336 25.92 ;
    END
  END o_cfg[12]
  PIN o_cfg[13]
    DIRECTION OUTPUT ;
    USE SIGNAL ;
    PORT
      LAYER M3 ;
        RECT  3.42 25.882 3.438 25.92 ;
    END
  END o_cfg[13]
  PIN o_cfg[14]
    DIRECTION OUTPUT ;
    USE SIGNAL ;
    PORT
      LAYER M5 ;
        RECT  3.504 25.836 3.528 25.92 ;
    END
  END o_cfg[14]
  PIN o_cfg[15]
    DIRECTION OUTPUT ;
    USE SIGNAL ;
    PORT
      LAYER M3 ;
        RECT  3.6 25.882 3.618 25.92 ;
    END
  END o_cfg[15]
  PIN o_cfg[16]
    DIRECTION OUTPUT ;
    USE SIGNAL ;
    PORT
      LAYER M5 ;
        RECT  3.696 25.836 3.72 25.92 ;
    END
  END o_cfg[16]
  PIN o_cfg[17]
    DIRECTION OUTPUT ;
    USE SIGNAL ;
    PORT
      LAYER M3 ;
        RECT  3.78 25.882 3.798 25.92 ;
    END
  END o_cfg[17]
  PIN o_cfg[18]
    DIRECTION OUTPUT ;
    USE SIGNAL ;
    PORT
      LAYER M5 ;
        RECT  3.888 25.836 3.912 25.92 ;
    END
  END o_cfg[18]
  PIN o_cfg[19]
    DIRECTION OUTPUT ;
    USE SIGNAL ;
    PORT
      LAYER M3 ;
        RECT  3.996 25.882 4.014 25.92 ;
    END
  END o_cfg[19]
  PIN o_cfg[1]
    DIRECTION OUTPUT ;
    USE SIGNAL ;
    PORT
      LAYER M3 ;
        RECT  2.304 25.882 2.322 25.92 ;
    END
  END o_cfg[1]
  PIN o_cfg[20]
    DIRECTION OUTPUT ;
    USE SIGNAL ;
    PORT
      LAYER M5 ;
        RECT  4.032 25.836 4.056 25.92 ;
    END
  END o_cfg[20]
  PIN o_cfg[21]
    DIRECTION OUTPUT ;
    USE SIGNAL ;
    PORT
      LAYER M3 ;
        RECT  4.14 25.882 4.158 25.92 ;
    END
  END o_cfg[21]
  PIN o_cfg[22]
    DIRECTION OUTPUT ;
    USE SIGNAL ;
    PORT
      LAYER M5 ;
        RECT  4.224 25.836 4.248 25.92 ;
    END
  END o_cfg[22]
  PIN o_cfg[23]
    DIRECTION OUTPUT ;
    USE SIGNAL ;
    PORT
      LAYER M3 ;
        RECT  4.32 25.882 4.338 25.92 ;
    END
  END o_cfg[23]
  PIN o_cfg[24]
    DIRECTION OUTPUT ;
    USE SIGNAL ;
    PORT
      LAYER M5 ;
        RECT  4.416 25.836 4.44 25.92 ;
    END
  END o_cfg[24]
  PIN o_cfg[25]
    DIRECTION OUTPUT ;
    USE SIGNAL ;
    PORT
      LAYER M3 ;
        RECT  4.5 25.882 4.518 25.92 ;
    END
  END o_cfg[25]
  PIN o_cfg[26]
    DIRECTION OUTPUT ;
    USE SIGNAL ;
    PORT
      LAYER M5 ;
        RECT  4.608 25.836 4.632 25.92 ;
    END
  END o_cfg[26]
  PIN o_cfg[27]
    DIRECTION OUTPUT ;
    USE SIGNAL ;
    PORT
      LAYER M3 ;
        RECT  4.716 25.882 4.734 25.92 ;
    END
  END o_cfg[27]
  PIN o_cfg[28]
    DIRECTION OUTPUT ;
    USE SIGNAL ;
    PORT
      LAYER M5 ;
        RECT  4.8 25.836 4.824 25.92 ;
    END
  END o_cfg[28]
  PIN o_cfg[29]
    DIRECTION OUTPUT ;
    USE SIGNAL ;
    PORT
      LAYER M3 ;
        RECT  4.896 25.882 4.914 25.92 ;
    END
  END o_cfg[29]
  PIN o_cfg[2]
    DIRECTION OUTPUT ;
    USE SIGNAL ;
    PORT
      LAYER M5 ;
        RECT  2.4 25.836 2.424 25.92 ;
    END
  END o_cfg[2]
  PIN o_cfg[30]
    DIRECTION OUTPUT ;
    USE SIGNAL ;
    PORT
      LAYER M5 ;
        RECT  4.992 25.836 5.016 25.92 ;
    END
  END o_cfg[30]
  PIN o_cfg[31]
    DIRECTION OUTPUT ;
    USE SIGNAL ;
    PORT
      LAYER M3 ;
        RECT  5.076 25.882 5.094 25.92 ;
    END
  END o_cfg[31]
  PIN o_cfg[32]
    DIRECTION OUTPUT ;
    USE SIGNAL ;
    PORT
      LAYER M5 ;
        RECT  5.184 25.836 5.208 25.92 ;
    END
  END o_cfg[32]
  PIN o_cfg[33]
    DIRECTION OUTPUT ;
    USE SIGNAL ;
    PORT
      LAYER M3 ;
        RECT  5.292 25.882 5.31 25.92 ;
    END
  END o_cfg[33]
  PIN o_cfg[34]
    DIRECTION OUTPUT ;
    USE SIGNAL ;
    PORT
      LAYER M5 ;
        RECT  5.376 25.836 5.4 25.92 ;
    END
  END o_cfg[34]
  PIN o_cfg[35]
    DIRECTION OUTPUT ;
    USE SIGNAL ;
    PORT
      LAYER M3 ;
        RECT  5.472 25.882 5.49 25.92 ;
    END
  END o_cfg[35]
  PIN o_cfg[36]
    DIRECTION OUTPUT ;
    USE SIGNAL ;
    PORT
      LAYER M5 ;
        RECT  5.52 25.836 5.544 25.92 ;
    END
  END o_cfg[36]
  PIN o_cfg[37]
    DIRECTION OUTPUT ;
    USE SIGNAL ;
    PORT
      LAYER M3 ;
        RECT  5.616 25.882 5.634 25.92 ;
    END
  END o_cfg[37]
  PIN o_cfg[38]
    DIRECTION OUTPUT ;
    USE SIGNAL ;
    PORT
      LAYER M5 ;
        RECT  5.712 25.836 5.736 25.92 ;
    END
  END o_cfg[38]
  PIN o_cfg[39]
    DIRECTION OUTPUT ;
    USE SIGNAL ;
    PORT
      LAYER M3 ;
        RECT  5.796 25.882 5.814 25.92 ;
    END
  END o_cfg[39]
  PIN o_cfg[3]
    DIRECTION OUTPUT ;
    USE SIGNAL ;
    PORT
      LAYER M3 ;
        RECT  2.484 25.882 2.502 25.92 ;
    END
  END o_cfg[3]
  PIN o_cfg[40]
    DIRECTION OUTPUT ;
    USE SIGNAL ;
    PORT
      LAYER M5 ;
        RECT  5.904 25.836 5.928 25.92 ;
    END
  END o_cfg[40]
  PIN o_cfg[41]
    DIRECTION OUTPUT ;
    USE SIGNAL ;
    PORT
      LAYER M3 ;
        RECT  6.012 25.882 6.03 25.92 ;
    END
  END o_cfg[41]
  PIN o_cfg[42]
    DIRECTION OUTPUT ;
    USE SIGNAL ;
    PORT
      LAYER M5 ;
        RECT  6.096 25.836 6.12 25.92 ;
    END
  END o_cfg[42]
  PIN o_cfg[43]
    DIRECTION OUTPUT ;
    USE SIGNAL ;
    PORT
      LAYER M3 ;
        RECT  6.192 25.882 6.21 25.92 ;
    END
  END o_cfg[43]
  PIN o_cfg[44]
    DIRECTION OUTPUT ;
    USE SIGNAL ;
    PORT
      LAYER M5 ;
        RECT  6.288 25.836 6.312 25.92 ;
    END
  END o_cfg[44]
  PIN o_cfg[45]
    DIRECTION OUTPUT ;
    USE SIGNAL ;
    PORT
      LAYER M3 ;
        RECT  6.372 25.882 6.39 25.92 ;
    END
  END o_cfg[45]
  PIN o_cfg[46]
    DIRECTION OUTPUT ;
    USE SIGNAL ;
    PORT
      LAYER M5 ;
        RECT  6.48 25.836 6.504 25.92 ;
    END
  END o_cfg[46]
  PIN o_cfg[47]
    DIRECTION OUTPUT ;
    USE SIGNAL ;
    PORT
      LAYER M3 ;
        RECT  6.588 25.882 6.606 25.92 ;
    END
  END o_cfg[47]
  PIN o_cfg[48]
    DIRECTION OUTPUT ;
    USE SIGNAL ;
    PORT
      LAYER M5 ;
        RECT  6.672 25.836 6.696 25.92 ;
    END
  END o_cfg[48]
  PIN o_cfg[49]
    DIRECTION OUTPUT ;
    USE SIGNAL ;
    PORT
      LAYER M3 ;
        RECT  6.768 25.882 6.786 25.92 ;
    END
  END o_cfg[49]
  PIN o_cfg[4]
    DIRECTION OUTPUT ;
    USE SIGNAL ;
    PORT
      LAYER M5 ;
        RECT  2.544 25.836 2.568 25.92 ;
    END
  END o_cfg[4]
  PIN o_cfg[50]
    DIRECTION OUTPUT ;
    USE SIGNAL ;
    PORT
      LAYER M5 ;
        RECT  6.864 25.836 6.888 25.92 ;
    END
  END o_cfg[50]
  PIN o_cfg[51]
    DIRECTION OUTPUT ;
    USE SIGNAL ;
    PORT
      LAYER M3 ;
        RECT  6.948 25.882 6.966 25.92 ;
    END
  END o_cfg[51]
  PIN o_cfg[52]
    DIRECTION OUTPUT ;
    USE SIGNAL ;
    PORT
      LAYER M5 ;
        RECT  7.008 25.836 7.032 25.92 ;
    END
  END o_cfg[52]
  PIN o_cfg[53]
    DIRECTION OUTPUT ;
    USE SIGNAL ;
    PORT
      LAYER M3 ;
        RECT  7.092 25.882 7.11 25.92 ;
    END
  END o_cfg[53]
  PIN o_cfg[5]
    DIRECTION OUTPUT ;
    USE SIGNAL ;
    PORT
      LAYER M3 ;
        RECT  2.628 25.882 2.646 25.92 ;
    END
  END o_cfg[5]
  PIN o_cfg[6]
    DIRECTION OUTPUT ;
    USE SIGNAL ;
    PORT
      LAYER M5 ;
        RECT  2.736 25.836 2.76 25.92 ;
    END
  END o_cfg[6]
  PIN o_cfg[7]
    DIRECTION OUTPUT ;
    USE SIGNAL ;
    PORT
      LAYER M3 ;
        RECT  2.844 25.882 2.862 25.92 ;
    END
  END o_cfg[7]
  PIN o_cfg[8]
    DIRECTION OUTPUT ;
    USE SIGNAL ;
    PORT
      LAYER M5 ;
        RECT  2.928 25.836 2.952 25.92 ;
    END
  END o_cfg[8]
  PIN o_cfg[9]
    DIRECTION OUTPUT ;
    USE SIGNAL ;
    PORT
      LAYER M3 ;
        RECT  3.024 25.882 3.042 25.92 ;
    END
  END o_cfg[9]
  PIN o_go[0]
    DIRECTION OUTPUT ;
    USE SIGNAL ;
    PORT
      LAYER M5 ;
        RECT  7.2 25.836 7.224 25.92 ;
    END
  END o_go[0]
  PIN o_x0[0]
    DIRECTION OUTPUT ;
    USE SIGNAL ;
    PORT
      LAYER M3 ;
        RECT  10.476 25.882 10.494 25.92 ;
    END
  END o_x0[0]
  PIN o_x0[100]
    DIRECTION OUTPUT ;
    USE SIGNAL ;
    PORT
      LAYER M3 ;
        RECT  19.764 25.882 19.782 25.92 ;
    END
  END o_x0[100]
  PIN o_x0[101]
    DIRECTION OUTPUT ;
    USE SIGNAL ;
    PORT
      LAYER M5 ;
        RECT  19.872 25.836 19.896 25.92 ;
    END
  END o_x0[101]
  PIN o_x0[102]
    DIRECTION OUTPUT ;
    USE SIGNAL ;
    PORT
      LAYER M3 ;
        RECT  19.98 25.882 19.998 25.92 ;
    END
  END o_x0[102]
  PIN o_x0[103]
    DIRECTION OUTPUT ;
    USE SIGNAL ;
    PORT
      LAYER M5 ;
        RECT  20.064 25.836 20.088 25.92 ;
    END
  END o_x0[103]
  PIN o_x0[104]
    DIRECTION OUTPUT ;
    USE SIGNAL ;
    PORT
      LAYER M3 ;
        RECT  20.16 25.882 20.178 25.92 ;
    END
  END o_x0[104]
  PIN o_x0[105]
    DIRECTION OUTPUT ;
    USE SIGNAL ;
    PORT
      LAYER M5 ;
        RECT  20.256 25.836 20.28 25.92 ;
    END
  END o_x0[105]
  PIN o_x0[106]
    DIRECTION OUTPUT ;
    USE SIGNAL ;
    PORT
      LAYER M3 ;
        RECT  20.304 25.882 20.322 25.92 ;
    END
  END o_x0[106]
  PIN o_x0[107]
    DIRECTION OUTPUT ;
    USE SIGNAL ;
    PORT
      LAYER M5 ;
        RECT  20.4 25.836 20.424 25.92 ;
    END
  END o_x0[107]
  PIN o_x0[108]
    DIRECTION OUTPUT ;
    USE SIGNAL ;
    PORT
      LAYER M3 ;
        RECT  20.484 25.882 20.502 25.92 ;
    END
  END o_x0[108]
  PIN o_x0[109]
    DIRECTION OUTPUT ;
    USE SIGNAL ;
    PORT
      LAYER M5 ;
        RECT  20.592 25.836 20.616 25.92 ;
    END
  END o_x0[109]
  PIN o_x0[10]
    DIRECTION OUTPUT ;
    USE SIGNAL ;
    PORT
      LAYER M3 ;
        RECT  11.376 25.882 11.394 25.92 ;
    END
  END o_x0[10]
  PIN o_x0[110]
    DIRECTION OUTPUT ;
    USE SIGNAL ;
    PORT
      LAYER M3 ;
        RECT  20.7 25.882 20.718 25.92 ;
    END
  END o_x0[110]
  PIN o_x0[111]
    DIRECTION OUTPUT ;
    USE SIGNAL ;
    PORT
      LAYER M5 ;
        RECT  20.784 25.836 20.808 25.92 ;
    END
  END o_x0[111]
  PIN o_x0[112]
    DIRECTION OUTPUT ;
    USE SIGNAL ;
    PORT
      LAYER M3 ;
        RECT  20.88 25.882 20.898 25.92 ;
    END
  END o_x0[112]
  PIN o_x0[113]
    DIRECTION OUTPUT ;
    USE SIGNAL ;
    PORT
      LAYER M5 ;
        RECT  20.976 25.836 21 25.92 ;
    END
  END o_x0[113]
  PIN o_x0[114]
    DIRECTION OUTPUT ;
    USE SIGNAL ;
    PORT
      LAYER M3 ;
        RECT  21.06 25.882 21.078 25.92 ;
    END
  END o_x0[114]
  PIN o_x0[115]
    DIRECTION OUTPUT ;
    USE SIGNAL ;
    PORT
      LAYER M5 ;
        RECT  21.168 25.836 21.192 25.92 ;
    END
  END o_x0[115]
  PIN o_x0[116]
    DIRECTION OUTPUT ;
    USE SIGNAL ;
    PORT
      LAYER M3 ;
        RECT  21.276 25.882 21.294 25.92 ;
    END
  END o_x0[116]
  PIN o_x0[117]
    DIRECTION OUTPUT ;
    USE SIGNAL ;
    PORT
      LAYER M5 ;
        RECT  21.36 25.836 21.384 25.92 ;
    END
  END o_x0[117]
  PIN o_x0[118]
    DIRECTION OUTPUT ;
    USE SIGNAL ;
    PORT
      LAYER M3 ;
        RECT  21.456 25.882 21.474 25.92 ;
    END
  END o_x0[118]
  PIN o_x0[119]
    DIRECTION OUTPUT ;
    USE SIGNAL ;
    PORT
      LAYER M5 ;
        RECT  21.552 25.836 21.576 25.92 ;
    END
  END o_x0[119]
  PIN o_x0[11]
    DIRECTION OUTPUT ;
    USE SIGNAL ;
    PORT
      LAYER M5 ;
        RECT  11.472 25.836 11.496 25.92 ;
    END
  END o_x0[11]
  PIN o_x0[120]
    DIRECTION OUTPUT ;
    USE SIGNAL ;
    PORT
      LAYER M3 ;
        RECT  21.636 25.882 21.654 25.92 ;
    END
  END o_x0[120]
  PIN o_x0[121]
    DIRECTION OUTPUT ;
    USE SIGNAL ;
    PORT
      LAYER M5 ;
        RECT  21.744 25.836 21.768 25.92 ;
    END
  END o_x0[121]
  PIN o_x0[122]
    DIRECTION OUTPUT ;
    USE SIGNAL ;
    PORT
      LAYER M3 ;
        RECT  21.78 25.882 21.798 25.92 ;
    END
  END o_x0[122]
  PIN o_x0[123]
    DIRECTION OUTPUT ;
    USE SIGNAL ;
    PORT
      LAYER M5 ;
        RECT  21.888 25.836 21.912 25.92 ;
    END
  END o_x0[123]
  PIN o_x0[124]
    DIRECTION OUTPUT ;
    USE SIGNAL ;
    PORT
      LAYER M3 ;
        RECT  21.996 25.882 22.014 25.92 ;
    END
  END o_x0[124]
  PIN o_x0[125]
    DIRECTION OUTPUT ;
    USE SIGNAL ;
    PORT
      LAYER M5 ;
        RECT  22.08 25.836 22.104 25.92 ;
    END
  END o_x0[125]
  PIN o_x0[126]
    DIRECTION OUTPUT ;
    USE SIGNAL ;
    PORT
      LAYER M3 ;
        RECT  22.176 25.882 22.194 25.92 ;
    END
  END o_x0[126]
  PIN o_x0[127]
    DIRECTION OUTPUT ;
    USE SIGNAL ;
    PORT
      LAYER M5 ;
        RECT  22.272 25.836 22.296 25.92 ;
    END
  END o_x0[127]
  PIN o_x0[128]
    DIRECTION OUTPUT ;
    USE SIGNAL ;
    PORT
      LAYER M3 ;
        RECT  22.356 25.882 22.374 25.92 ;
    END
  END o_x0[128]
  PIN o_x0[129]
    DIRECTION OUTPUT ;
    USE SIGNAL ;
    PORT
      LAYER M5 ;
        RECT  22.464 25.836 22.488 25.92 ;
    END
  END o_x0[129]
  PIN o_x0[12]
    DIRECTION OUTPUT ;
    USE SIGNAL ;
    PORT
      LAYER M3 ;
        RECT  11.556 25.882 11.574 25.92 ;
    END
  END o_x0[12]
  PIN o_x0[130]
    DIRECTION OUTPUT ;
    USE SIGNAL ;
    PORT
      LAYER M3 ;
        RECT  22.572 25.882 22.59 25.92 ;
    END
  END o_x0[130]
  PIN o_x0[131]
    DIRECTION OUTPUT ;
    USE SIGNAL ;
    PORT
      LAYER M5 ;
        RECT  22.656 25.836 22.68 25.92 ;
    END
  END o_x0[131]
  PIN o_x0[132]
    DIRECTION OUTPUT ;
    USE SIGNAL ;
    PORT
      LAYER M3 ;
        RECT  22.752 25.882 22.77 25.92 ;
    END
  END o_x0[132]
  PIN o_x0[133]
    DIRECTION OUTPUT ;
    USE SIGNAL ;
    PORT
      LAYER M5 ;
        RECT  22.848 25.836 22.872 25.92 ;
    END
  END o_x0[133]
  PIN o_x0[134]
    DIRECTION OUTPUT ;
    USE SIGNAL ;
    PORT
      LAYER M3 ;
        RECT  22.932 25.882 22.95 25.92 ;
    END
  END o_x0[134]
  PIN o_x0[135]
    DIRECTION OUTPUT ;
    USE SIGNAL ;
    PORT
      LAYER M5 ;
        RECT  23.04 25.836 23.064 25.92 ;
    END
  END o_x0[135]
  PIN o_x0[136]
    DIRECTION OUTPUT ;
    USE SIGNAL ;
    PORT
      LAYER M3 ;
        RECT  23.148 25.882 23.166 25.92 ;
    END
  END o_x0[136]
  PIN o_x0[137]
    DIRECTION OUTPUT ;
    USE SIGNAL ;
    PORT
      LAYER M5 ;
        RECT  23.184 25.836 23.208 25.92 ;
    END
  END o_x0[137]
  PIN o_x0[138]
    DIRECTION OUTPUT ;
    USE SIGNAL ;
    PORT
      LAYER M3 ;
        RECT  23.292 25.882 23.31 25.92 ;
    END
  END o_x0[138]
  PIN o_x0[139]
    DIRECTION OUTPUT ;
    USE SIGNAL ;
    PORT
      LAYER M5 ;
        RECT  23.376 25.836 23.4 25.92 ;
    END
  END o_x0[139]
  PIN o_x0[13]
    DIRECTION OUTPUT ;
    USE SIGNAL ;
    PORT
      LAYER M5 ;
        RECT  11.664 25.836 11.688 25.92 ;
    END
  END o_x0[13]
  PIN o_x0[140]
    DIRECTION OUTPUT ;
    USE SIGNAL ;
    PORT
      LAYER M3 ;
        RECT  23.472 25.882 23.49 25.92 ;
    END
  END o_x0[140]
  PIN o_x0[141]
    DIRECTION OUTPUT ;
    USE SIGNAL ;
    PORT
      LAYER M5 ;
        RECT  23.568 25.836 23.592 25.92 ;
    END
  END o_x0[141]
  PIN o_x0[142]
    DIRECTION OUTPUT ;
    USE SIGNAL ;
    PORT
      LAYER M3 ;
        RECT  23.652 25.882 23.67 25.92 ;
    END
  END o_x0[142]
  PIN o_x0[143]
    DIRECTION OUTPUT ;
    USE SIGNAL ;
    PORT
      LAYER M5 ;
        RECT  23.76 25.836 23.784 25.92 ;
    END
  END o_x0[143]
  PIN o_x0[144]
    DIRECTION OUTPUT ;
    USE SIGNAL ;
    PORT
      LAYER M3 ;
        RECT  23.868 25.882 23.886 25.92 ;
    END
  END o_x0[144]
  PIN o_x0[145]
    DIRECTION OUTPUT ;
    USE SIGNAL ;
    PORT
      LAYER M5 ;
        RECT  23.952 25.836 23.976 25.92 ;
    END
  END o_x0[145]
  PIN o_x0[146]
    DIRECTION OUTPUT ;
    USE SIGNAL ;
    PORT
      LAYER M3 ;
        RECT  24.048 25.882 24.066 25.92 ;
    END
  END o_x0[146]
  PIN o_x0[147]
    DIRECTION OUTPUT ;
    USE SIGNAL ;
    PORT
      LAYER M5 ;
        RECT  24.144 25.836 24.168 25.92 ;
    END
  END o_x0[147]
  PIN o_x0[148]
    DIRECTION OUTPUT ;
    USE SIGNAL ;
    PORT
      LAYER M3 ;
        RECT  24.228 25.882 24.246 25.92 ;
    END
  END o_x0[148]
  PIN o_x0[149]
    DIRECTION OUTPUT ;
    USE SIGNAL ;
    PORT
      LAYER M5 ;
        RECT  24.336 25.836 24.36 25.92 ;
    END
  END o_x0[149]
  PIN o_x0[14]
    DIRECTION OUTPUT ;
    USE SIGNAL ;
    PORT
      LAYER M3 ;
        RECT  11.772 25.882 11.79 25.92 ;
    END
  END o_x0[14]
  PIN o_x0[150]
    DIRECTION OUTPUT ;
    USE SIGNAL ;
    PORT
      LAYER M3 ;
        RECT  24.444 25.882 24.462 25.92 ;
    END
  END o_x0[150]
  PIN o_x0[151]
    DIRECTION OUTPUT ;
    USE SIGNAL ;
    PORT
      LAYER M5 ;
        RECT  24.528 25.836 24.552 25.92 ;
    END
  END o_x0[151]
  PIN o_x0[152]
    DIRECTION OUTPUT ;
    USE SIGNAL ;
    PORT
      LAYER M3 ;
        RECT  24.624 25.882 24.642 25.92 ;
    END
  END o_x0[152]
  PIN o_x0[153]
    DIRECTION OUTPUT ;
    USE SIGNAL ;
    PORT
      LAYER M5 ;
        RECT  24.672 25.836 24.696 25.92 ;
    END
  END o_x0[153]
  PIN o_x0[154]
    DIRECTION OUTPUT ;
    USE SIGNAL ;
    PORT
      LAYER M3 ;
        RECT  24.768 25.882 24.786 25.92 ;
    END
  END o_x0[154]
  PIN o_x0[155]
    DIRECTION OUTPUT ;
    USE SIGNAL ;
    PORT
      LAYER M5 ;
        RECT  24.864 25.836 24.888 25.92 ;
    END
  END o_x0[155]
  PIN o_x0[156]
    DIRECTION OUTPUT ;
    USE SIGNAL ;
    PORT
      LAYER M3 ;
        RECT  24.948 25.882 24.966 25.92 ;
    END
  END o_x0[156]
  PIN o_x0[157]
    DIRECTION OUTPUT ;
    USE SIGNAL ;
    PORT
      LAYER M5 ;
        RECT  25.056 25.836 25.08 25.92 ;
    END
  END o_x0[157]
  PIN o_x0[158]
    DIRECTION OUTPUT ;
    USE SIGNAL ;
    PORT
      LAYER M3 ;
        RECT  25.164 25.882 25.182 25.92 ;
    END
  END o_x0[158]
  PIN o_x0[159]
    DIRECTION OUTPUT ;
    USE SIGNAL ;
    PORT
      LAYER M5 ;
        RECT  25.248 25.836 25.272 25.92 ;
    END
  END o_x0[159]
  PIN o_x0[15]
    DIRECTION OUTPUT ;
    USE SIGNAL ;
    PORT
      LAYER M5 ;
        RECT  11.856 25.836 11.88 25.92 ;
    END
  END o_x0[15]
  PIN o_x0[160]
    DIRECTION OUTPUT ;
    USE SIGNAL ;
    PORT
      LAYER M3 ;
        RECT  25.344 25.882 25.362 25.92 ;
    END
  END o_x0[160]
  PIN o_x0[161]
    DIRECTION OUTPUT ;
    USE SIGNAL ;
    PORT
      LAYER M5 ;
        RECT  25.44 25.836 25.464 25.92 ;
    END
  END o_x0[161]
  PIN o_x0[162]
    DIRECTION OUTPUT ;
    USE SIGNAL ;
    PORT
      LAYER M3 ;
        RECT  25.524 25.882 25.542 25.92 ;
    END
  END o_x0[162]
  PIN o_x0[163]
    DIRECTION OUTPUT ;
    USE SIGNAL ;
    PORT
      LAYER M5 ;
        RECT  25.632 25.836 25.656 25.92 ;
    END
  END o_x0[163]
  PIN o_x0[164]
    DIRECTION OUTPUT ;
    USE SIGNAL ;
    PORT
      LAYER M3 ;
        RECT  25.74 25.882 25.758 25.92 ;
    END
  END o_x0[164]
  PIN o_x0[165]
    DIRECTION OUTPUT ;
    USE SIGNAL ;
    PORT
      LAYER M5 ;
        RECT  25.824 25.836 25.848 25.92 ;
    END
  END o_x0[165]
  PIN o_x0[166]
    DIRECTION OUTPUT ;
    USE SIGNAL ;
    PORT
      LAYER M3 ;
        RECT  25.92 25.882 25.938 25.92 ;
    END
  END o_x0[166]
  PIN o_x0[167]
    DIRECTION OUTPUT ;
    USE SIGNAL ;
    PORT
      LAYER M5 ;
        RECT  26.016 25.836 26.04 25.92 ;
    END
  END o_x0[167]
  PIN o_x0[168]
    DIRECTION OUTPUT ;
    USE SIGNAL ;
    PORT
      LAYER M3 ;
        RECT  26.1 25.882 26.118 25.92 ;
    END
  END o_x0[168]
  PIN o_x0[169]
    DIRECTION OUTPUT ;
    USE SIGNAL ;
    PORT
      LAYER M5 ;
        RECT  26.16 25.836 26.184 25.92 ;
    END
  END o_x0[169]
  PIN o_x0[16]
    DIRECTION OUTPUT ;
    USE SIGNAL ;
    PORT
      LAYER M3 ;
        RECT  11.952 25.882 11.97 25.92 ;
    END
  END o_x0[16]
  PIN o_x0[170]
    DIRECTION OUTPUT ;
    USE SIGNAL ;
    PORT
      LAYER M3 ;
        RECT  26.244 25.882 26.262 25.92 ;
    END
  END o_x0[170]
  PIN o_x0[171]
    DIRECTION OUTPUT ;
    USE SIGNAL ;
    PORT
      LAYER M5 ;
        RECT  26.352 25.836 26.376 25.92 ;
    END
  END o_x0[171]
  PIN o_x0[172]
    DIRECTION OUTPUT ;
    USE SIGNAL ;
    PORT
      LAYER M3 ;
        RECT  26.46 25.882 26.478 25.92 ;
    END
  END o_x0[172]
  PIN o_x0[173]
    DIRECTION OUTPUT ;
    USE SIGNAL ;
    PORT
      LAYER M5 ;
        RECT  26.544 25.836 26.568 25.92 ;
    END
  END o_x0[173]
  PIN o_x0[174]
    DIRECTION OUTPUT ;
    USE SIGNAL ;
    PORT
      LAYER M3 ;
        RECT  26.64 25.882 26.658 25.92 ;
    END
  END o_x0[174]
  PIN o_x0[175]
    DIRECTION OUTPUT ;
    USE SIGNAL ;
    PORT
      LAYER M5 ;
        RECT  26.736 25.836 26.76 25.92 ;
    END
  END o_x0[175]
  PIN o_x0[176]
    DIRECTION OUTPUT ;
    USE SIGNAL ;
    PORT
      LAYER M3 ;
        RECT  26.82 25.882 26.838 25.92 ;
    END
  END o_x0[176]
  PIN o_x0[177]
    DIRECTION OUTPUT ;
    USE SIGNAL ;
    PORT
      LAYER M5 ;
        RECT  26.928 25.836 26.952 25.92 ;
    END
  END o_x0[177]
  PIN o_x0[178]
    DIRECTION OUTPUT ;
    USE SIGNAL ;
    PORT
      LAYER M3 ;
        RECT  27.036 25.882 27.054 25.92 ;
    END
  END o_x0[178]
  PIN o_x0[179]
    DIRECTION OUTPUT ;
    USE SIGNAL ;
    PORT
      LAYER M5 ;
        RECT  27.12 25.836 27.144 25.92 ;
    END
  END o_x0[179]
  PIN o_x0[17]
    DIRECTION OUTPUT ;
    USE SIGNAL ;
    PORT
      LAYER M5 ;
        RECT  12.048 25.836 12.072 25.92 ;
    END
  END o_x0[17]
  PIN o_x0[180]
    DIRECTION OUTPUT ;
    USE SIGNAL ;
    PORT
      LAYER M3 ;
        RECT  27.216 25.882 27.234 25.92 ;
    END
  END o_x0[180]
  PIN o_x0[181]
    DIRECTION OUTPUT ;
    USE SIGNAL ;
    PORT
      LAYER M5 ;
        RECT  27.312 25.836 27.336 25.92 ;
    END
  END o_x0[181]
  PIN o_x0[182]
    DIRECTION OUTPUT ;
    USE SIGNAL ;
    PORT
      LAYER M3 ;
        RECT  27.396 25.882 27.414 25.92 ;
    END
  END o_x0[182]
  PIN o_x0[183]
    DIRECTION OUTPUT ;
    USE SIGNAL ;
    PORT
      LAYER M5 ;
        RECT  27.504 25.836 27.528 25.92 ;
    END
  END o_x0[183]
  PIN o_x0[184]
    DIRECTION OUTPUT ;
    USE SIGNAL ;
    PORT
      LAYER M3 ;
        RECT  27.612 25.882 27.63 25.92 ;
    END
  END o_x0[184]
  PIN o_x0[185]
    DIRECTION OUTPUT ;
    USE SIGNAL ;
    PORT
      LAYER M5 ;
        RECT  27.648 25.836 27.672 25.92 ;
    END
  END o_x0[185]
  PIN o_x0[186]
    DIRECTION OUTPUT ;
    USE SIGNAL ;
    PORT
      LAYER M3 ;
        RECT  27.756 25.882 27.774 25.92 ;
    END
  END o_x0[186]
  PIN o_x0[187]
    DIRECTION OUTPUT ;
    USE SIGNAL ;
    PORT
      LAYER M5 ;
        RECT  27.84 25.836 27.864 25.92 ;
    END
  END o_x0[187]
  PIN o_x0[188]
    DIRECTION OUTPUT ;
    USE SIGNAL ;
    PORT
      LAYER M3 ;
        RECT  27.936 25.882 27.954 25.92 ;
    END
  END o_x0[188]
  PIN o_x0[189]
    DIRECTION OUTPUT ;
    USE SIGNAL ;
    PORT
      LAYER M5 ;
        RECT  28.032 25.836 28.056 25.92 ;
    END
  END o_x0[189]
  PIN o_x0[18]
    DIRECTION OUTPUT ;
    USE SIGNAL ;
    PORT
      LAYER M3 ;
        RECT  12.132 25.882 12.15 25.92 ;
    END
  END o_x0[18]
  PIN o_x0[190]
    DIRECTION OUTPUT ;
    USE SIGNAL ;
    PORT
      LAYER M3 ;
        RECT  28.116 25.882 28.134 25.92 ;
    END
  END o_x0[190]
  PIN o_x0[191]
    DIRECTION OUTPUT ;
    USE SIGNAL ;
    PORT
      LAYER M5 ;
        RECT  28.224 25.836 28.248 25.92 ;
    END
  END o_x0[191]
  PIN o_x0[192]
    DIRECTION OUTPUT ;
    USE SIGNAL ;
    PORT
      LAYER M3 ;
        RECT  28.332 25.882 28.35 25.92 ;
    END
  END o_x0[192]
  PIN o_x0[193]
    DIRECTION OUTPUT ;
    USE SIGNAL ;
    PORT
      LAYER M5 ;
        RECT  28.416 25.836 28.44 25.92 ;
    END
  END o_x0[193]
  PIN o_x0[194]
    DIRECTION OUTPUT ;
    USE SIGNAL ;
    PORT
      LAYER M3 ;
        RECT  28.512 25.882 28.53 25.92 ;
    END
  END o_x0[194]
  PIN o_x0[195]
    DIRECTION OUTPUT ;
    USE SIGNAL ;
    PORT
      LAYER M5 ;
        RECT  28.608 25.836 28.632 25.92 ;
    END
  END o_x0[195]
  PIN o_x0[196]
    DIRECTION OUTPUT ;
    USE SIGNAL ;
    PORT
      LAYER M3 ;
        RECT  28.692 25.882 28.71 25.92 ;
    END
  END o_x0[196]
  PIN o_x0[197]
    DIRECTION OUTPUT ;
    USE SIGNAL ;
    PORT
      LAYER M5 ;
        RECT  28.8 25.836 28.824 25.92 ;
    END
  END o_x0[197]
  PIN o_x0[198]
    DIRECTION OUTPUT ;
    USE SIGNAL ;
    PORT
      LAYER M3 ;
        RECT  28.908 25.882 28.926 25.92 ;
    END
  END o_x0[198]
  PIN o_x0[199]
    DIRECTION OUTPUT ;
    USE SIGNAL ;
    PORT
      LAYER M5 ;
        RECT  28.992 25.836 29.016 25.92 ;
    END
  END o_x0[199]
  PIN o_x0[19]
    DIRECTION OUTPUT ;
    USE SIGNAL ;
    PORT
      LAYER M5 ;
        RECT  12.24 25.836 12.264 25.92 ;
    END
  END o_x0[19]
  PIN o_x0[1]
    DIRECTION OUTPUT ;
    USE SIGNAL ;
    PORT
      LAYER M5 ;
        RECT  10.56 25.836 10.584 25.92 ;
    END
  END o_x0[1]
  PIN o_x0[200]
    DIRECTION OUTPUT ;
    USE SIGNAL ;
    PORT
      LAYER M3 ;
        RECT  29.088 25.882 29.106 25.92 ;
    END
  END o_x0[200]
  PIN o_x0[201]
    DIRECTION OUTPUT ;
    USE SIGNAL ;
    PORT
      LAYER M5 ;
        RECT  29.136 25.836 29.16 25.92 ;
    END
  END o_x0[201]
  PIN o_x0[202]
    DIRECTION OUTPUT ;
    USE SIGNAL ;
    PORT
      LAYER M3 ;
        RECT  29.232 25.882 29.25 25.92 ;
    END
  END o_x0[202]
  PIN o_x0[203]
    DIRECTION OUTPUT ;
    USE SIGNAL ;
    PORT
      LAYER M5 ;
        RECT  29.328 25.836 29.352 25.92 ;
    END
  END o_x0[203]
  PIN o_x0[204]
    DIRECTION OUTPUT ;
    USE SIGNAL ;
    PORT
      LAYER M3 ;
        RECT  29.412 25.882 29.43 25.92 ;
    END
  END o_x0[204]
  PIN o_x0[205]
    DIRECTION OUTPUT ;
    USE SIGNAL ;
    PORT
      LAYER M5 ;
        RECT  29.52 25.836 29.544 25.92 ;
    END
  END o_x0[205]
  PIN o_x0[206]
    DIRECTION OUTPUT ;
    USE SIGNAL ;
    PORT
      LAYER M3 ;
        RECT  29.628 25.882 29.646 25.92 ;
    END
  END o_x0[206]
  PIN o_x0[207]
    DIRECTION OUTPUT ;
    USE SIGNAL ;
    PORT
      LAYER M5 ;
        RECT  29.712 25.836 29.736 25.92 ;
    END
  END o_x0[207]
  PIN o_x0[208]
    DIRECTION OUTPUT ;
    USE SIGNAL ;
    PORT
      LAYER M3 ;
        RECT  29.808 25.882 29.826 25.92 ;
    END
  END o_x0[208]
  PIN o_x0[209]
    DIRECTION OUTPUT ;
    USE SIGNAL ;
    PORT
      LAYER M5 ;
        RECT  29.904 25.836 29.928 25.92 ;
    END
  END o_x0[209]
  PIN o_x0[20]
    DIRECTION OUTPUT ;
    USE SIGNAL ;
    PORT
      LAYER M3 ;
        RECT  12.348 25.882 12.366 25.92 ;
    END
  END o_x0[20]
  PIN o_x0[210]
    DIRECTION OUTPUT ;
    USE SIGNAL ;
    PORT
      LAYER M3 ;
        RECT  29.988 25.882 30.006 25.92 ;
    END
  END o_x0[210]
  PIN o_x0[211]
    DIRECTION OUTPUT ;
    USE SIGNAL ;
    PORT
      LAYER M5 ;
        RECT  30.096 25.836 30.12 25.92 ;
    END
  END o_x0[211]
  PIN o_x0[212]
    DIRECTION OUTPUT ;
    USE SIGNAL ;
    PORT
      LAYER M3 ;
        RECT  30.204 25.882 30.222 25.92 ;
    END
  END o_x0[212]
  PIN o_x0[213]
    DIRECTION OUTPUT ;
    USE SIGNAL ;
    PORT
      LAYER M5 ;
        RECT  30.288 25.836 30.312 25.92 ;
    END
  END o_x0[213]
  PIN o_x0[214]
    DIRECTION OUTPUT ;
    USE SIGNAL ;
    PORT
      LAYER M3 ;
        RECT  30.384 25.882 30.402 25.92 ;
    END
  END o_x0[214]
  PIN o_x0[215]
    DIRECTION OUTPUT ;
    USE SIGNAL ;
    PORT
      LAYER M5 ;
        RECT  30.48 25.836 30.504 25.92 ;
    END
  END o_x0[215]
  PIN o_x0[216]
    DIRECTION OUTPUT ;
    USE SIGNAL ;
    PORT
      LAYER M3 ;
        RECT  30.564 25.882 30.582 25.92 ;
    END
  END o_x0[216]
  PIN o_x0[217]
    DIRECTION OUTPUT ;
    USE SIGNAL ;
    PORT
      LAYER M5 ;
        RECT  30.624 25.836 30.648 25.92 ;
    END
  END o_x0[217]
  PIN o_x0[218]
    DIRECTION OUTPUT ;
    USE SIGNAL ;
    PORT
      LAYER M3 ;
        RECT  30.708 25.882 30.726 25.92 ;
    END
  END o_x0[218]
  PIN o_x0[219]
    DIRECTION OUTPUT ;
    USE SIGNAL ;
    PORT
      LAYER M5 ;
        RECT  30.816 25.836 30.84 25.92 ;
    END
  END o_x0[219]
  PIN o_x0[21]
    DIRECTION OUTPUT ;
    USE SIGNAL ;
    PORT
      LAYER M5 ;
        RECT  12.432 25.836 12.456 25.92 ;
    END
  END o_x0[21]
  PIN o_x0[220]
    DIRECTION OUTPUT ;
    USE SIGNAL ;
    PORT
      LAYER M3 ;
        RECT  30.924 25.882 30.942 25.92 ;
    END
  END o_x0[220]
  PIN o_x0[221]
    DIRECTION OUTPUT ;
    USE SIGNAL ;
    PORT
      LAYER M5 ;
        RECT  31.008 25.836 31.032 25.92 ;
    END
  END o_x0[221]
  PIN o_x0[222]
    DIRECTION OUTPUT ;
    USE SIGNAL ;
    PORT
      LAYER M3 ;
        RECT  31.104 25.882 31.122 25.92 ;
    END
  END o_x0[222]
  PIN o_x0[223]
    DIRECTION OUTPUT ;
    USE SIGNAL ;
    PORT
      LAYER M5 ;
        RECT  31.2 25.836 31.224 25.92 ;
    END
  END o_x0[223]
  PIN o_x0[224]
    DIRECTION OUTPUT ;
    USE SIGNAL ;
    PORT
      LAYER M3 ;
        RECT  31.284 25.882 31.302 25.92 ;
    END
  END o_x0[224]
  PIN o_x0[225]
    DIRECTION OUTPUT ;
    USE SIGNAL ;
    PORT
      LAYER M5 ;
        RECT  31.392 25.836 31.416 25.92 ;
    END
  END o_x0[225]
  PIN o_x0[226]
    DIRECTION OUTPUT ;
    USE SIGNAL ;
    PORT
      LAYER M3 ;
        RECT  31.5 25.882 31.518 25.92 ;
    END
  END o_x0[226]
  PIN o_x0[227]
    DIRECTION OUTPUT ;
    USE SIGNAL ;
    PORT
      LAYER M5 ;
        RECT  31.584 25.836 31.608 25.92 ;
    END
  END o_x0[227]
  PIN o_x0[228]
    DIRECTION OUTPUT ;
    USE SIGNAL ;
    PORT
      LAYER M3 ;
        RECT  31.68 25.882 31.698 25.92 ;
    END
  END o_x0[228]
  PIN o_x0[229]
    DIRECTION OUTPUT ;
    USE SIGNAL ;
    PORT
      LAYER M5 ;
        RECT  31.776 25.836 31.8 25.92 ;
    END
  END o_x0[229]
  PIN o_x0[22]
    DIRECTION OUTPUT ;
    USE SIGNAL ;
    PORT
      LAYER M3 ;
        RECT  12.528 25.882 12.546 25.92 ;
    END
  END o_x0[22]
  PIN o_x0[230]
    DIRECTION OUTPUT ;
    USE SIGNAL ;
    PORT
      LAYER M3 ;
        RECT  31.86 25.882 31.878 25.92 ;
    END
  END o_x0[230]
  PIN o_x0[231]
    DIRECTION OUTPUT ;
    USE SIGNAL ;
    PORT
      LAYER M5 ;
        RECT  31.968 25.836 31.992 25.92 ;
    END
  END o_x0[231]
  PIN o_x0[232]
    DIRECTION OUTPUT ;
    USE SIGNAL ;
    PORT
      LAYER M3 ;
        RECT  32.076 25.882 32.094 25.92 ;
    END
  END o_x0[232]
  PIN o_x0[233]
    DIRECTION OUTPUT ;
    USE SIGNAL ;
    PORT
      LAYER M5 ;
        RECT  32.112 25.836 32.136 25.92 ;
    END
  END o_x0[233]
  PIN o_x0[234]
    DIRECTION OUTPUT ;
    USE SIGNAL ;
    PORT
      LAYER M3 ;
        RECT  32.22 25.882 32.238 25.92 ;
    END
  END o_x0[234]
  PIN o_x0[235]
    DIRECTION OUTPUT ;
    USE SIGNAL ;
    PORT
      LAYER M5 ;
        RECT  32.304 25.836 32.328 25.92 ;
    END
  END o_x0[235]
  PIN o_x0[236]
    DIRECTION OUTPUT ;
    USE SIGNAL ;
    PORT
      LAYER M3 ;
        RECT  32.4 25.882 32.418 25.92 ;
    END
  END o_x0[236]
  PIN o_x0[237]
    DIRECTION OUTPUT ;
    USE SIGNAL ;
    PORT
      LAYER M5 ;
        RECT  32.496 25.836 32.52 25.92 ;
    END
  END o_x0[237]
  PIN o_x0[238]
    DIRECTION OUTPUT ;
    USE SIGNAL ;
    PORT
      LAYER M3 ;
        RECT  32.58 25.882 32.598 25.92 ;
    END
  END o_x0[238]
  PIN o_x0[239]
    DIRECTION OUTPUT ;
    USE SIGNAL ;
    PORT
      LAYER M5 ;
        RECT  32.688 25.836 32.712 25.92 ;
    END
  END o_x0[239]
  PIN o_x0[23]
    DIRECTION OUTPUT ;
    USE SIGNAL ;
    PORT
      LAYER M5 ;
        RECT  12.624 25.836 12.648 25.92 ;
    END
  END o_x0[23]
  PIN o_x0[240]
    DIRECTION OUTPUT ;
    USE SIGNAL ;
    PORT
      LAYER M3 ;
        RECT  32.796 25.882 32.814 25.92 ;
    END
  END o_x0[240]
  PIN o_x0[241]
    DIRECTION OUTPUT ;
    USE SIGNAL ;
    PORT
      LAYER M5 ;
        RECT  32.88 25.836 32.904 25.92 ;
    END
  END o_x0[241]
  PIN o_x0[242]
    DIRECTION OUTPUT ;
    USE SIGNAL ;
    PORT
      LAYER M3 ;
        RECT  32.976 25.882 32.994 25.92 ;
    END
  END o_x0[242]
  PIN o_x0[243]
    DIRECTION OUTPUT ;
    USE SIGNAL ;
    PORT
      LAYER M5 ;
        RECT  33.072 25.836 33.096 25.92 ;
    END
  END o_x0[243]
  PIN o_x0[244]
    DIRECTION OUTPUT ;
    USE SIGNAL ;
    PORT
      LAYER M3 ;
        RECT  33.156 25.882 33.174 25.92 ;
    END
  END o_x0[244]
  PIN o_x0[245]
    DIRECTION OUTPUT ;
    USE SIGNAL ;
    PORT
      LAYER M5 ;
        RECT  33.264 25.836 33.288 25.92 ;
    END
  END o_x0[245]
  PIN o_x0[246]
    DIRECTION OUTPUT ;
    USE SIGNAL ;
    PORT
      LAYER M3 ;
        RECT  33.372 25.882 33.39 25.92 ;
    END
  END o_x0[246]
  PIN o_x0[247]
    DIRECTION OUTPUT ;
    USE SIGNAL ;
    PORT
      LAYER M5 ;
        RECT  33.456 25.836 33.48 25.92 ;
    END
  END o_x0[247]
  PIN o_x0[248]
    DIRECTION OUTPUT ;
    USE SIGNAL ;
    PORT
      LAYER M3 ;
        RECT  33.552 25.882 33.57 25.92 ;
    END
  END o_x0[248]
  PIN o_x0[249]
    DIRECTION OUTPUT ;
    USE SIGNAL ;
    PORT
      LAYER M5 ;
        RECT  33.6 25.836 33.624 25.92 ;
    END
  END o_x0[249]
  PIN o_x0[24]
    DIRECTION OUTPUT ;
    USE SIGNAL ;
    PORT
      LAYER M3 ;
        RECT  12.708 25.882 12.726 25.92 ;
    END
  END o_x0[24]
  PIN o_x0[250]
    DIRECTION OUTPUT ;
    USE SIGNAL ;
    PORT
      LAYER M3 ;
        RECT  33.696 25.882 33.714 25.92 ;
    END
  END o_x0[250]
  PIN o_x0[251]
    DIRECTION OUTPUT ;
    USE SIGNAL ;
    PORT
      LAYER M5 ;
        RECT  33.792 25.836 33.816 25.92 ;
    END
  END o_x0[251]
  PIN o_x0[252]
    DIRECTION OUTPUT ;
    USE SIGNAL ;
    PORT
      LAYER M3 ;
        RECT  33.876 25.882 33.894 25.92 ;
    END
  END o_x0[252]
  PIN o_x0[253]
    DIRECTION OUTPUT ;
    USE SIGNAL ;
    PORT
      LAYER M5 ;
        RECT  33.984 25.836 34.008 25.92 ;
    END
  END o_x0[253]
  PIN o_x0[254]
    DIRECTION OUTPUT ;
    USE SIGNAL ;
    PORT
      LAYER M3 ;
        RECT  34.092 25.882 34.11 25.92 ;
    END
  END o_x0[254]
  PIN o_x0[255]
    DIRECTION OUTPUT ;
    USE SIGNAL ;
    PORT
      LAYER M5 ;
        RECT  34.176 25.836 34.2 25.92 ;
    END
  END o_x0[255]
  PIN o_x0[256]
    DIRECTION OUTPUT ;
    USE SIGNAL ;
    PORT
      LAYER M5 ;
        RECT  7.584 25.836 7.608 25.92 ;
    END
  END o_x0[256]
  PIN o_x0[257]
    DIRECTION OUTPUT ;
    USE SIGNAL ;
    PORT
      LAYER M3 ;
        RECT  7.668 25.882 7.686 25.92 ;
    END
  END o_x0[257]
  PIN o_x0[258]
    DIRECTION OUTPUT ;
    USE SIGNAL ;
    PORT
      LAYER M5 ;
        RECT  7.776 25.836 7.8 25.92 ;
    END
  END o_x0[258]
  PIN o_x0[259]
    DIRECTION OUTPUT ;
    USE SIGNAL ;
    PORT
      LAYER M3 ;
        RECT  7.884 25.882 7.902 25.92 ;
    END
  END o_x0[259]
  PIN o_x0[25]
    DIRECTION OUTPUT ;
    USE SIGNAL ;
    PORT
      LAYER M5 ;
        RECT  12.816 25.836 12.84 25.92 ;
    END
  END o_x0[25]
  PIN o_x0[260]
    DIRECTION OUTPUT ;
    USE SIGNAL ;
    PORT
      LAYER M5 ;
        RECT  7.968 25.836 7.992 25.92 ;
    END
  END o_x0[260]
  PIN o_x0[261]
    DIRECTION OUTPUT ;
    USE SIGNAL ;
    PORT
      LAYER M3 ;
        RECT  8.064 25.882 8.082 25.92 ;
    END
  END o_x0[261]
  PIN o_x0[262]
    DIRECTION OUTPUT ;
    USE SIGNAL ;
    PORT
      LAYER M5 ;
        RECT  8.16 25.836 8.184 25.92 ;
    END
  END o_x0[262]
  PIN o_x0[263]
    DIRECTION OUTPUT ;
    USE SIGNAL ;
    PORT
      LAYER M3 ;
        RECT  8.244 25.882 8.262 25.92 ;
    END
  END o_x0[263]
  PIN o_x0[264]
    DIRECTION OUTPUT ;
    USE SIGNAL ;
    PORT
      LAYER M5 ;
        RECT  8.352 25.836 8.376 25.92 ;
    END
  END o_x0[264]
  PIN o_x0[265]
    DIRECTION OUTPUT ;
    USE SIGNAL ;
    PORT
      LAYER M3 ;
        RECT  8.46 25.882 8.478 25.92 ;
    END
  END o_x0[265]
  PIN o_x0[266]
    DIRECTION OUTPUT ;
    USE SIGNAL ;
    PORT
      LAYER M3 ;
        RECT  7.308 25.882 7.326 25.92 ;
    END
  END o_x0[266]
  PIN o_x0[267]
    DIRECTION OUTPUT ;
    USE SIGNAL ;
    PORT
      LAYER M5 ;
        RECT  7.392 25.836 7.416 25.92 ;
    END
  END o_x0[267]
  PIN o_x0[268]
    DIRECTION OUTPUT ;
    USE SIGNAL ;
    PORT
      LAYER M3 ;
        RECT  7.488 25.882 7.506 25.92 ;
    END
  END o_x0[268]
  PIN o_x0[269]
    DIRECTION OUTPUT ;
    USE SIGNAL ;
    PORT
      LAYER M5 ;
        RECT  9.456 25.836 9.48 25.92 ;
    END
  END o_x0[269]
  PIN o_x0[26]
    DIRECTION OUTPUT ;
    USE SIGNAL ;
    PORT
      LAYER M3 ;
        RECT  12.852 25.882 12.87 25.92 ;
    END
  END o_x0[26]
  PIN o_x0[270]
    DIRECTION OUTPUT ;
    USE SIGNAL ;
    PORT
      LAYER M3 ;
        RECT  9.54 25.882 9.558 25.92 ;
    END
  END o_x0[270]
  PIN o_x0[271]
    DIRECTION OUTPUT ;
    USE SIGNAL ;
    PORT
      LAYER M5 ;
        RECT  9.648 25.836 9.672 25.92 ;
    END
  END o_x0[271]
  PIN o_x0[272]
    DIRECTION OUTPUT ;
    USE SIGNAL ;
    PORT
      LAYER M3 ;
        RECT  9.756 25.882 9.774 25.92 ;
    END
  END o_x0[272]
  PIN o_x0[273]
    DIRECTION OUTPUT ;
    USE SIGNAL ;
    PORT
      LAYER M5 ;
        RECT  9.84 25.836 9.864 25.92 ;
    END
  END o_x0[273]
  PIN o_x0[274]
    DIRECTION OUTPUT ;
    USE SIGNAL ;
    PORT
      LAYER M3 ;
        RECT  9.9 25.882 9.918 25.92 ;
    END
  END o_x0[274]
  PIN o_x0[275]
    DIRECTION OUTPUT ;
    USE SIGNAL ;
    PORT
      LAYER M5 ;
        RECT  9.984 25.836 10.008 25.92 ;
    END
  END o_x0[275]
  PIN o_x0[276]
    DIRECTION OUTPUT ;
    USE SIGNAL ;
    PORT
      LAYER M3 ;
        RECT  10.08 25.882 10.098 25.92 ;
    END
  END o_x0[276]
  PIN o_x0[277]
    DIRECTION OUTPUT ;
    USE SIGNAL ;
    PORT
      LAYER M5 ;
        RECT  10.176 25.836 10.2 25.92 ;
    END
  END o_x0[277]
  PIN o_x0[278]
    DIRECTION OUTPUT ;
    USE SIGNAL ;
    PORT
      LAYER M3 ;
        RECT  10.26 25.882 10.278 25.92 ;
    END
  END o_x0[278]
  PIN o_x0[279]
    DIRECTION OUTPUT ;
    USE SIGNAL ;
    PORT
      LAYER M5 ;
        RECT  10.368 25.836 10.392 25.92 ;
    END
  END o_x0[279]
  PIN o_x0[27]
    DIRECTION OUTPUT ;
    USE SIGNAL ;
    PORT
      LAYER M5 ;
        RECT  12.96 25.836 12.984 25.92 ;
    END
  END o_x0[27]
  PIN o_x0[280]
    DIRECTION OUTPUT ;
    USE SIGNAL ;
    PORT
      LAYER M3 ;
        RECT  58.068 25.882 58.086 25.92 ;
    END
  END o_x0[280]
  PIN o_x0[281]
    DIRECTION OUTPUT ;
    USE SIGNAL ;
    PORT
      LAYER M5 ;
        RECT  58.176 25.836 58.2 25.92 ;
    END
  END o_x0[281]
  PIN o_x0[282]
    DIRECTION OUTPUT ;
    USE SIGNAL ;
    PORT
      LAYER M3 ;
        RECT  58.284 25.882 58.302 25.92 ;
    END
  END o_x0[282]
  PIN o_x0[28]
    DIRECTION OUTPUT ;
    USE SIGNAL ;
    PORT
      LAYER M3 ;
        RECT  13.068 25.882 13.086 25.92 ;
    END
  END o_x0[28]
  PIN o_x0[29]
    DIRECTION OUTPUT ;
    USE SIGNAL ;
    PORT
      LAYER M5 ;
        RECT  13.152 25.836 13.176 25.92 ;
    END
  END o_x0[29]
  PIN o_x0[2]
    DIRECTION OUTPUT ;
    USE SIGNAL ;
    PORT
      LAYER M3 ;
        RECT  10.656 25.882 10.674 25.92 ;
    END
  END o_x0[2]
  PIN o_x0[30]
    DIRECTION OUTPUT ;
    USE SIGNAL ;
    PORT
      LAYER M3 ;
        RECT  13.248 25.882 13.266 25.92 ;
    END
  END o_x0[30]
  PIN o_x0[31]
    DIRECTION OUTPUT ;
    USE SIGNAL ;
    PORT
      LAYER M5 ;
        RECT  13.344 25.836 13.368 25.92 ;
    END
  END o_x0[31]
  PIN o_x0[32]
    DIRECTION OUTPUT ;
    USE SIGNAL ;
    PORT
      LAYER M3 ;
        RECT  13.428 25.882 13.446 25.92 ;
    END
  END o_x0[32]
  PIN o_x0[33]
    DIRECTION OUTPUT ;
    USE SIGNAL ;
    PORT
      LAYER M5 ;
        RECT  13.536 25.836 13.56 25.92 ;
    END
  END o_x0[33]
  PIN o_x0[34]
    DIRECTION OUTPUT ;
    USE SIGNAL ;
    PORT
      LAYER M3 ;
        RECT  13.644 25.882 13.662 25.92 ;
    END
  END o_x0[34]
  PIN o_x0[35]
    DIRECTION OUTPUT ;
    USE SIGNAL ;
    PORT
      LAYER M5 ;
        RECT  13.728 25.836 13.752 25.92 ;
    END
  END o_x0[35]
  PIN o_x0[36]
    DIRECTION OUTPUT ;
    USE SIGNAL ;
    PORT
      LAYER M3 ;
        RECT  13.824 25.882 13.842 25.92 ;
    END
  END o_x0[36]
  PIN o_x0[37]
    DIRECTION OUTPUT ;
    USE SIGNAL ;
    PORT
      LAYER M5 ;
        RECT  13.92 25.836 13.944 25.92 ;
    END
  END o_x0[37]
  PIN o_x0[38]
    DIRECTION OUTPUT ;
    USE SIGNAL ;
    PORT
      LAYER M3 ;
        RECT  14.004 25.882 14.022 25.92 ;
    END
  END o_x0[38]
  PIN o_x0[39]
    DIRECTION OUTPUT ;
    USE SIGNAL ;
    PORT
      LAYER M5 ;
        RECT  14.112 25.836 14.136 25.92 ;
    END
  END o_x0[39]
  PIN o_x0[3]
    DIRECTION OUTPUT ;
    USE SIGNAL ;
    PORT
      LAYER M5 ;
        RECT  10.752 25.836 10.776 25.92 ;
    END
  END o_x0[3]
  PIN o_x0[40]
    DIRECTION OUTPUT ;
    USE SIGNAL ;
    PORT
      LAYER M3 ;
        RECT  14.22 25.882 14.238 25.92 ;
    END
  END o_x0[40]
  PIN o_x0[41]
    DIRECTION OUTPUT ;
    USE SIGNAL ;
    PORT
      LAYER M5 ;
        RECT  14.304 25.836 14.328 25.92 ;
    END
  END o_x0[41]
  PIN o_x0[42]
    DIRECTION OUTPUT ;
    USE SIGNAL ;
    PORT
      LAYER M3 ;
        RECT  14.364 25.882 14.382 25.92 ;
    END
  END o_x0[42]
  PIN o_x0[43]
    DIRECTION OUTPUT ;
    USE SIGNAL ;
    PORT
      LAYER M5 ;
        RECT  14.448 25.836 14.472 25.92 ;
    END
  END o_x0[43]
  PIN o_x0[44]
    DIRECTION OUTPUT ;
    USE SIGNAL ;
    PORT
      LAYER M3 ;
        RECT  14.544 25.882 14.562 25.92 ;
    END
  END o_x0[44]
  PIN o_x0[45]
    DIRECTION OUTPUT ;
    USE SIGNAL ;
    PORT
      LAYER M5 ;
        RECT  14.64 25.836 14.664 25.92 ;
    END
  END o_x0[45]
  PIN o_x0[46]
    DIRECTION OUTPUT ;
    USE SIGNAL ;
    PORT
      LAYER M3 ;
        RECT  14.724 25.882 14.742 25.92 ;
    END
  END o_x0[46]
  PIN o_x0[47]
    DIRECTION OUTPUT ;
    USE SIGNAL ;
    PORT
      LAYER M5 ;
        RECT  14.832 25.836 14.856 25.92 ;
    END
  END o_x0[47]
  PIN o_x0[48]
    DIRECTION OUTPUT ;
    USE SIGNAL ;
    PORT
      LAYER M3 ;
        RECT  14.94 25.882 14.958 25.92 ;
    END
  END o_x0[48]
  PIN o_x0[49]
    DIRECTION OUTPUT ;
    USE SIGNAL ;
    PORT
      LAYER M5 ;
        RECT  15.024 25.836 15.048 25.92 ;
    END
  END o_x0[49]
  PIN o_x0[4]
    DIRECTION OUTPUT ;
    USE SIGNAL ;
    PORT
      LAYER M3 ;
        RECT  10.836 25.882 10.854 25.92 ;
    END
  END o_x0[4]
  PIN o_x0[50]
    DIRECTION OUTPUT ;
    USE SIGNAL ;
    PORT
      LAYER M3 ;
        RECT  15.12 25.882 15.138 25.92 ;
    END
  END o_x0[50]
  PIN o_x0[51]
    DIRECTION OUTPUT ;
    USE SIGNAL ;
    PORT
      LAYER M5 ;
        RECT  15.216 25.836 15.24 25.92 ;
    END
  END o_x0[51]
  PIN o_x0[52]
    DIRECTION OUTPUT ;
    USE SIGNAL ;
    PORT
      LAYER M3 ;
        RECT  15.3 25.882 15.318 25.92 ;
    END
  END o_x0[52]
  PIN o_x0[53]
    DIRECTION OUTPUT ;
    USE SIGNAL ;
    PORT
      LAYER M5 ;
        RECT  15.408 25.836 15.432 25.92 ;
    END
  END o_x0[53]
  PIN o_x0[54]
    DIRECTION OUTPUT ;
    USE SIGNAL ;
    PORT
      LAYER M3 ;
        RECT  15.516 25.882 15.534 25.92 ;
    END
  END o_x0[54]
  PIN o_x0[55]
    DIRECTION OUTPUT ;
    USE SIGNAL ;
    PORT
      LAYER M5 ;
        RECT  15.6 25.836 15.624 25.92 ;
    END
  END o_x0[55]
  PIN o_x0[56]
    DIRECTION OUTPUT ;
    USE SIGNAL ;
    PORT
      LAYER M3 ;
        RECT  15.696 25.882 15.714 25.92 ;
    END
  END o_x0[56]
  PIN o_x0[57]
    DIRECTION OUTPUT ;
    USE SIGNAL ;
    PORT
      LAYER M5 ;
        RECT  15.792 25.836 15.816 25.92 ;
    END
  END o_x0[57]
  PIN o_x0[58]
    DIRECTION OUTPUT ;
    USE SIGNAL ;
    PORT
      LAYER M3 ;
        RECT  15.84 25.882 15.858 25.92 ;
    END
  END o_x0[58]
  PIN o_x0[59]
    DIRECTION OUTPUT ;
    USE SIGNAL ;
    PORT
      LAYER M5 ;
        RECT  15.936 25.836 15.96 25.92 ;
    END
  END o_x0[59]
  PIN o_x0[5]
    DIRECTION OUTPUT ;
    USE SIGNAL ;
    PORT
      LAYER M5 ;
        RECT  10.944 25.836 10.968 25.92 ;
    END
  END o_x0[5]
  PIN o_x0[60]
    DIRECTION OUTPUT ;
    USE SIGNAL ;
    PORT
      LAYER M3 ;
        RECT  16.02 25.882 16.038 25.92 ;
    END
  END o_x0[60]
  PIN o_x0[61]
    DIRECTION OUTPUT ;
    USE SIGNAL ;
    PORT
      LAYER M5 ;
        RECT  16.128 25.836 16.152 25.92 ;
    END
  END o_x0[61]
  PIN o_x0[62]
    DIRECTION OUTPUT ;
    USE SIGNAL ;
    PORT
      LAYER M3 ;
        RECT  16.236 25.882 16.254 25.92 ;
    END
  END o_x0[62]
  PIN o_x0[63]
    DIRECTION OUTPUT ;
    USE SIGNAL ;
    PORT
      LAYER M5 ;
        RECT  16.32 25.836 16.344 25.92 ;
    END
  END o_x0[63]
  PIN o_x0[64]
    DIRECTION OUTPUT ;
    USE SIGNAL ;
    PORT
      LAYER M3 ;
        RECT  16.416 25.882 16.434 25.92 ;
    END
  END o_x0[64]
  PIN o_x0[65]
    DIRECTION OUTPUT ;
    USE SIGNAL ;
    PORT
      LAYER M5 ;
        RECT  16.512 25.836 16.536 25.92 ;
    END
  END o_x0[65]
  PIN o_x0[66]
    DIRECTION OUTPUT ;
    USE SIGNAL ;
    PORT
      LAYER M3 ;
        RECT  16.596 25.882 16.614 25.92 ;
    END
  END o_x0[66]
  PIN o_x0[67]
    DIRECTION OUTPUT ;
    USE SIGNAL ;
    PORT
      LAYER M5 ;
        RECT  16.704 25.836 16.728 25.92 ;
    END
  END o_x0[67]
  PIN o_x0[68]
    DIRECTION OUTPUT ;
    USE SIGNAL ;
    PORT
      LAYER M3 ;
        RECT  16.812 25.882 16.83 25.92 ;
    END
  END o_x0[68]
  PIN o_x0[69]
    DIRECTION OUTPUT ;
    USE SIGNAL ;
    PORT
      LAYER M5 ;
        RECT  16.896 25.836 16.92 25.92 ;
    END
  END o_x0[69]
  PIN o_x0[6]
    DIRECTION OUTPUT ;
    USE SIGNAL ;
    PORT
      LAYER M3 ;
        RECT  11.052 25.882 11.07 25.92 ;
    END
  END o_x0[6]
  PIN o_x0[70]
    DIRECTION OUTPUT ;
    USE SIGNAL ;
    PORT
      LAYER M3 ;
        RECT  16.992 25.882 17.01 25.92 ;
    END
  END o_x0[70]
  PIN o_x0[71]
    DIRECTION OUTPUT ;
    USE SIGNAL ;
    PORT
      LAYER M5 ;
        RECT  17.088 25.836 17.112 25.92 ;
    END
  END o_x0[71]
  PIN o_x0[72]
    DIRECTION OUTPUT ;
    USE SIGNAL ;
    PORT
      LAYER M3 ;
        RECT  17.172 25.882 17.19 25.92 ;
    END
  END o_x0[72]
  PIN o_x0[73]
    DIRECTION OUTPUT ;
    USE SIGNAL ;
    PORT
      LAYER M5 ;
        RECT  17.28 25.836 17.304 25.92 ;
    END
  END o_x0[73]
  PIN o_x0[74]
    DIRECTION OUTPUT ;
    USE SIGNAL ;
    PORT
      LAYER M3 ;
        RECT  17.316 25.882 17.334 25.92 ;
    END
  END o_x0[74]
  PIN o_x0[75]
    DIRECTION OUTPUT ;
    USE SIGNAL ;
    PORT
      LAYER M5 ;
        RECT  17.424 25.836 17.448 25.92 ;
    END
  END o_x0[75]
  PIN o_x0[76]
    DIRECTION OUTPUT ;
    USE SIGNAL ;
    PORT
      LAYER M3 ;
        RECT  17.532 25.882 17.55 25.92 ;
    END
  END o_x0[76]
  PIN o_x0[77]
    DIRECTION OUTPUT ;
    USE SIGNAL ;
    PORT
      LAYER M5 ;
        RECT  17.616 25.836 17.64 25.92 ;
    END
  END o_x0[77]
  PIN o_x0[78]
    DIRECTION OUTPUT ;
    USE SIGNAL ;
    PORT
      LAYER M3 ;
        RECT  17.712 25.882 17.73 25.92 ;
    END
  END o_x0[78]
  PIN o_x0[79]
    DIRECTION OUTPUT ;
    USE SIGNAL ;
    PORT
      LAYER M5 ;
        RECT  17.808 25.836 17.832 25.92 ;
    END
  END o_x0[79]
  PIN o_x0[7]
    DIRECTION OUTPUT ;
    USE SIGNAL ;
    PORT
      LAYER M5 ;
        RECT  11.136 25.836 11.16 25.92 ;
    END
  END o_x0[7]
  PIN o_x0[80]
    DIRECTION OUTPUT ;
    USE SIGNAL ;
    PORT
      LAYER M3 ;
        RECT  17.892 25.882 17.91 25.92 ;
    END
  END o_x0[80]
  PIN o_x0[81]
    DIRECTION OUTPUT ;
    USE SIGNAL ;
    PORT
      LAYER M5 ;
        RECT  18 25.836 18.024 25.92 ;
    END
  END o_x0[81]
  PIN o_x0[82]
    DIRECTION OUTPUT ;
    USE SIGNAL ;
    PORT
      LAYER M3 ;
        RECT  18.108 25.882 18.126 25.92 ;
    END
  END o_x0[82]
  PIN o_x0[83]
    DIRECTION OUTPUT ;
    USE SIGNAL ;
    PORT
      LAYER M5 ;
        RECT  18.192 25.836 18.216 25.92 ;
    END
  END o_x0[83]
  PIN o_x0[84]
    DIRECTION OUTPUT ;
    USE SIGNAL ;
    PORT
      LAYER M3 ;
        RECT  18.288 25.882 18.306 25.92 ;
    END
  END o_x0[84]
  PIN o_x0[85]
    DIRECTION OUTPUT ;
    USE SIGNAL ;
    PORT
      LAYER M5 ;
        RECT  18.384 25.836 18.408 25.92 ;
    END
  END o_x0[85]
  PIN o_x0[86]
    DIRECTION OUTPUT ;
    USE SIGNAL ;
    PORT
      LAYER M3 ;
        RECT  18.468 25.882 18.486 25.92 ;
    END
  END o_x0[86]
  PIN o_x0[87]
    DIRECTION OUTPUT ;
    USE SIGNAL ;
    PORT
      LAYER M5 ;
        RECT  18.576 25.836 18.6 25.92 ;
    END
  END o_x0[87]
  PIN o_x0[88]
    DIRECTION OUTPUT ;
    USE SIGNAL ;
    PORT
      LAYER M3 ;
        RECT  18.684 25.882 18.702 25.92 ;
    END
  END o_x0[88]
  PIN o_x0[89]
    DIRECTION OUTPUT ;
    USE SIGNAL ;
    PORT
      LAYER M5 ;
        RECT  18.768 25.836 18.792 25.92 ;
    END
  END o_x0[89]
  PIN o_x0[8]
    DIRECTION OUTPUT ;
    USE SIGNAL ;
    PORT
      LAYER M3 ;
        RECT  11.232 25.882 11.25 25.92 ;
    END
  END o_x0[8]
  PIN o_x0[90]
    DIRECTION OUTPUT ;
    USE SIGNAL ;
    PORT
      LAYER M3 ;
        RECT  18.828 25.882 18.846 25.92 ;
    END
  END o_x0[90]
  PIN o_x0[91]
    DIRECTION OUTPUT ;
    USE SIGNAL ;
    PORT
      LAYER M5 ;
        RECT  18.912 25.836 18.936 25.92 ;
    END
  END o_x0[91]
  PIN o_x0[92]
    DIRECTION OUTPUT ;
    USE SIGNAL ;
    PORT
      LAYER M3 ;
        RECT  19.008 25.882 19.026 25.92 ;
    END
  END o_x0[92]
  PIN o_x0[93]
    DIRECTION OUTPUT ;
    USE SIGNAL ;
    PORT
      LAYER M5 ;
        RECT  19.104 25.836 19.128 25.92 ;
    END
  END o_x0[93]
  PIN o_x0[94]
    DIRECTION OUTPUT ;
    USE SIGNAL ;
    PORT
      LAYER M3 ;
        RECT  19.188 25.882 19.206 25.92 ;
    END
  END o_x0[94]
  PIN o_x0[95]
    DIRECTION OUTPUT ;
    USE SIGNAL ;
    PORT
      LAYER M5 ;
        RECT  19.296 25.836 19.32 25.92 ;
    END
  END o_x0[95]
  PIN o_x0[96]
    DIRECTION OUTPUT ;
    USE SIGNAL ;
    PORT
      LAYER M3 ;
        RECT  19.404 25.882 19.422 25.92 ;
    END
  END o_x0[96]
  PIN o_x0[97]
    DIRECTION OUTPUT ;
    USE SIGNAL ;
    PORT
      LAYER M5 ;
        RECT  19.488 25.836 19.512 25.92 ;
    END
  END o_x0[97]
  PIN o_x0[98]
    DIRECTION OUTPUT ;
    USE SIGNAL ;
    PORT
      LAYER M3 ;
        RECT  19.584 25.882 19.602 25.92 ;
    END
  END o_x0[98]
  PIN o_x0[99]
    DIRECTION OUTPUT ;
    USE SIGNAL ;
    PORT
      LAYER M5 ;
        RECT  19.68 25.836 19.704 25.92 ;
    END
  END o_x0[99]
  PIN o_x0[9]
    DIRECTION OUTPUT ;
    USE SIGNAL ;
    PORT
      LAYER M5 ;
        RECT  11.328 25.836 11.352 25.92 ;
    END
  END o_x0[9]
  PIN o_x1[0]
    DIRECTION OUTPUT ;
    USE SIGNAL ;
    PORT
      LAYER M3 ;
        RECT  34.272 25.882 34.29 25.92 ;
    END
  END o_x1[0]
  PIN o_x1[100]
    DIRECTION OUTPUT ;
    USE SIGNAL ;
    PORT
      LAYER M3 ;
        RECT  43.596 25.882 43.614 25.92 ;
    END
  END o_x1[100]
  PIN o_x1[101]
    DIRECTION OUTPUT ;
    USE SIGNAL ;
    PORT
      LAYER M5 ;
        RECT  43.68 25.836 43.704 25.92 ;
    END
  END o_x1[101]
  PIN o_x1[102]
    DIRECTION OUTPUT ;
    USE SIGNAL ;
    PORT
      LAYER M3 ;
        RECT  43.776 25.882 43.794 25.92 ;
    END
  END o_x1[102]
  PIN o_x1[103]
    DIRECTION OUTPUT ;
    USE SIGNAL ;
    PORT
      LAYER M5 ;
        RECT  43.872 25.836 43.896 25.92 ;
    END
  END o_x1[103]
  PIN o_x1[104]
    DIRECTION OUTPUT ;
    USE SIGNAL ;
    PORT
      LAYER M3 ;
        RECT  43.92 25.882 43.938 25.92 ;
    END
  END o_x1[104]
  PIN o_x1[105]
    DIRECTION OUTPUT ;
    USE SIGNAL ;
    PORT
      LAYER M5 ;
        RECT  44.016 25.836 44.04 25.92 ;
    END
  END o_x1[105]
  PIN o_x1[106]
    DIRECTION OUTPUT ;
    USE SIGNAL ;
    PORT
      LAYER M3 ;
        RECT  44.1 25.882 44.118 25.92 ;
    END
  END o_x1[106]
  PIN o_x1[107]
    DIRECTION OUTPUT ;
    USE SIGNAL ;
    PORT
      LAYER M5 ;
        RECT  44.208 25.836 44.232 25.92 ;
    END
  END o_x1[107]
  PIN o_x1[108]
    DIRECTION OUTPUT ;
    USE SIGNAL ;
    PORT
      LAYER M3 ;
        RECT  44.316 25.882 44.334 25.92 ;
    END
  END o_x1[108]
  PIN o_x1[109]
    DIRECTION OUTPUT ;
    USE SIGNAL ;
    PORT
      LAYER M5 ;
        RECT  44.4 25.836 44.424 25.92 ;
    END
  END o_x1[109]
  PIN o_x1[10]
    DIRECTION OUTPUT ;
    USE SIGNAL ;
    PORT
      LAYER M3 ;
        RECT  35.172 25.882 35.19 25.92 ;
    END
  END o_x1[10]
  PIN o_x1[110]
    DIRECTION OUTPUT ;
    USE SIGNAL ;
    PORT
      LAYER M3 ;
        RECT  44.496 25.882 44.514 25.92 ;
    END
  END o_x1[110]
  PIN o_x1[111]
    DIRECTION OUTPUT ;
    USE SIGNAL ;
    PORT
      LAYER M5 ;
        RECT  44.592 25.836 44.616 25.92 ;
    END
  END o_x1[111]
  PIN o_x1[112]
    DIRECTION OUTPUT ;
    USE SIGNAL ;
    PORT
      LAYER M3 ;
        RECT  44.676 25.882 44.694 25.92 ;
    END
  END o_x1[112]
  PIN o_x1[113]
    DIRECTION OUTPUT ;
    USE SIGNAL ;
    PORT
      LAYER M5 ;
        RECT  44.784 25.836 44.808 25.92 ;
    END
  END o_x1[113]
  PIN o_x1[114]
    DIRECTION OUTPUT ;
    USE SIGNAL ;
    PORT
      LAYER M3 ;
        RECT  44.892 25.882 44.91 25.92 ;
    END
  END o_x1[114]
  PIN o_x1[115]
    DIRECTION OUTPUT ;
    USE SIGNAL ;
    PORT
      LAYER M5 ;
        RECT  44.976 25.836 45 25.92 ;
    END
  END o_x1[115]
  PIN o_x1[116]
    DIRECTION OUTPUT ;
    USE SIGNAL ;
    PORT
      LAYER M3 ;
        RECT  45.072 25.882 45.09 25.92 ;
    END
  END o_x1[116]
  PIN o_x1[117]
    DIRECTION OUTPUT ;
    USE SIGNAL ;
    PORT
      LAYER M5 ;
        RECT  45.168 25.836 45.192 25.92 ;
    END
  END o_x1[117]
  PIN o_x1[118]
    DIRECTION OUTPUT ;
    USE SIGNAL ;
    PORT
      LAYER M3 ;
        RECT  45.252 25.882 45.27 25.92 ;
    END
  END o_x1[118]
  PIN o_x1[119]
    DIRECTION OUTPUT ;
    USE SIGNAL ;
    PORT
      LAYER M5 ;
        RECT  45.36 25.836 45.384 25.92 ;
    END
  END o_x1[119]
  PIN o_x1[11]
    DIRECTION OUTPUT ;
    USE SIGNAL ;
    PORT
      LAYER M5 ;
        RECT  35.28 25.836 35.304 25.92 ;
    END
  END o_x1[11]
  PIN o_x1[120]
    DIRECTION OUTPUT ;
    USE SIGNAL ;
    PORT
      LAYER M3 ;
        RECT  45.396 25.882 45.414 25.92 ;
    END
  END o_x1[120]
  PIN o_x1[121]
    DIRECTION OUTPUT ;
    USE SIGNAL ;
    PORT
      LAYER M5 ;
        RECT  45.504 25.836 45.528 25.92 ;
    END
  END o_x1[121]
  PIN o_x1[122]
    DIRECTION OUTPUT ;
    USE SIGNAL ;
    PORT
      LAYER M3 ;
        RECT  45.612 25.882 45.63 25.92 ;
    END
  END o_x1[122]
  PIN o_x1[123]
    DIRECTION OUTPUT ;
    USE SIGNAL ;
    PORT
      LAYER M5 ;
        RECT  45.696 25.836 45.72 25.92 ;
    END
  END o_x1[123]
  PIN o_x1[124]
    DIRECTION OUTPUT ;
    USE SIGNAL ;
    PORT
      LAYER M3 ;
        RECT  45.792 25.882 45.81 25.92 ;
    END
  END o_x1[124]
  PIN o_x1[125]
    DIRECTION OUTPUT ;
    USE SIGNAL ;
    PORT
      LAYER M5 ;
        RECT  45.888 25.836 45.912 25.92 ;
    END
  END o_x1[125]
  PIN o_x1[126]
    DIRECTION OUTPUT ;
    USE SIGNAL ;
    PORT
      LAYER M3 ;
        RECT  45.972 25.882 45.99 25.92 ;
    END
  END o_x1[126]
  PIN o_x1[127]
    DIRECTION OUTPUT ;
    USE SIGNAL ;
    PORT
      LAYER M5 ;
        RECT  46.08 25.836 46.104 25.92 ;
    END
  END o_x1[127]
  PIN o_x1[128]
    DIRECTION OUTPUT ;
    USE SIGNAL ;
    PORT
      LAYER M3 ;
        RECT  46.188 25.882 46.206 25.92 ;
    END
  END o_x1[128]
  PIN o_x1[129]
    DIRECTION OUTPUT ;
    USE SIGNAL ;
    PORT
      LAYER M5 ;
        RECT  46.272 25.836 46.296 25.92 ;
    END
  END o_x1[129]
  PIN o_x1[12]
    DIRECTION OUTPUT ;
    USE SIGNAL ;
    PORT
      LAYER M3 ;
        RECT  35.388 25.882 35.406 25.92 ;
    END
  END o_x1[12]
  PIN o_x1[130]
    DIRECTION OUTPUT ;
    USE SIGNAL ;
    PORT
      LAYER M3 ;
        RECT  46.368 25.882 46.386 25.92 ;
    END
  END o_x1[130]
  PIN o_x1[131]
    DIRECTION OUTPUT ;
    USE SIGNAL ;
    PORT
      LAYER M5 ;
        RECT  46.464 25.836 46.488 25.92 ;
    END
  END o_x1[131]
  PIN o_x1[132]
    DIRECTION OUTPUT ;
    USE SIGNAL ;
    PORT
      LAYER M3 ;
        RECT  46.548 25.882 46.566 25.92 ;
    END
  END o_x1[132]
  PIN o_x1[133]
    DIRECTION OUTPUT ;
    USE SIGNAL ;
    PORT
      LAYER M5 ;
        RECT  46.656 25.836 46.68 25.92 ;
    END
  END o_x1[133]
  PIN o_x1[134]
    DIRECTION OUTPUT ;
    USE SIGNAL ;
    PORT
      LAYER M3 ;
        RECT  46.764 25.882 46.782 25.92 ;
    END
  END o_x1[134]
  PIN o_x1[135]
    DIRECTION OUTPUT ;
    USE SIGNAL ;
    PORT
      LAYER M5 ;
        RECT  46.848 25.836 46.872 25.92 ;
    END
  END o_x1[135]
  PIN o_x1[136]
    DIRECTION OUTPUT ;
    USE SIGNAL ;
    PORT
      LAYER M3 ;
        RECT  46.908 25.882 46.926 25.92 ;
    END
  END o_x1[136]
  PIN o_x1[137]
    DIRECTION OUTPUT ;
    USE SIGNAL ;
    PORT
      LAYER M5 ;
        RECT  46.992 25.836 47.016 25.92 ;
    END
  END o_x1[137]
  PIN o_x1[138]
    DIRECTION OUTPUT ;
    USE SIGNAL ;
    PORT
      LAYER M3 ;
        RECT  47.088 25.882 47.106 25.92 ;
    END
  END o_x1[138]
  PIN o_x1[139]
    DIRECTION OUTPUT ;
    USE SIGNAL ;
    PORT
      LAYER M5 ;
        RECT  47.184 25.836 47.208 25.92 ;
    END
  END o_x1[139]
  PIN o_x1[13]
    DIRECTION OUTPUT ;
    USE SIGNAL ;
    PORT
      LAYER M5 ;
        RECT  35.472 25.836 35.496 25.92 ;
    END
  END o_x1[13]
  PIN o_x1[140]
    DIRECTION OUTPUT ;
    USE SIGNAL ;
    PORT
      LAYER M3 ;
        RECT  47.268 25.882 47.286 25.92 ;
    END
  END o_x1[140]
  PIN o_x1[141]
    DIRECTION OUTPUT ;
    USE SIGNAL ;
    PORT
      LAYER M5 ;
        RECT  47.376 25.836 47.4 25.92 ;
    END
  END o_x1[141]
  PIN o_x1[142]
    DIRECTION OUTPUT ;
    USE SIGNAL ;
    PORT
      LAYER M3 ;
        RECT  47.484 25.882 47.502 25.92 ;
    END
  END o_x1[142]
  PIN o_x1[143]
    DIRECTION OUTPUT ;
    USE SIGNAL ;
    PORT
      LAYER M5 ;
        RECT  47.568 25.836 47.592 25.92 ;
    END
  END o_x1[143]
  PIN o_x1[144]
    DIRECTION OUTPUT ;
    USE SIGNAL ;
    PORT
      LAYER M3 ;
        RECT  47.664 25.882 47.682 25.92 ;
    END
  END o_x1[144]
  PIN o_x1[145]
    DIRECTION OUTPUT ;
    USE SIGNAL ;
    PORT
      LAYER M5 ;
        RECT  47.76 25.836 47.784 25.92 ;
    END
  END o_x1[145]
  PIN o_x1[146]
    DIRECTION OUTPUT ;
    USE SIGNAL ;
    PORT
      LAYER M3 ;
        RECT  47.844 25.882 47.862 25.92 ;
    END
  END o_x1[146]
  PIN o_x1[147]
    DIRECTION OUTPUT ;
    USE SIGNAL ;
    PORT
      LAYER M5 ;
        RECT  47.952 25.836 47.976 25.92 ;
    END
  END o_x1[147]
  PIN o_x1[148]
    DIRECTION OUTPUT ;
    USE SIGNAL ;
    PORT
      LAYER M3 ;
        RECT  48.06 25.882 48.078 25.92 ;
    END
  END o_x1[148]
  PIN o_x1[149]
    DIRECTION OUTPUT ;
    USE SIGNAL ;
    PORT
      LAYER M5 ;
        RECT  48.144 25.836 48.168 25.92 ;
    END
  END o_x1[149]
  PIN o_x1[14]
    DIRECTION OUTPUT ;
    USE SIGNAL ;
    PORT
      LAYER M3 ;
        RECT  35.568 25.882 35.586 25.92 ;
    END
  END o_x1[14]
  PIN o_x1[150]
    DIRECTION OUTPUT ;
    USE SIGNAL ;
    PORT
      LAYER M3 ;
        RECT  48.24 25.882 48.258 25.92 ;
    END
  END o_x1[150]
  PIN o_x1[151]
    DIRECTION OUTPUT ;
    USE SIGNAL ;
    PORT
      LAYER M5 ;
        RECT  48.336 25.836 48.36 25.92 ;
    END
  END o_x1[151]
  PIN o_x1[152]
    DIRECTION OUTPUT ;
    USE SIGNAL ;
    PORT
      LAYER M3 ;
        RECT  48.384 25.882 48.402 25.92 ;
    END
  END o_x1[152]
  PIN o_x1[153]
    DIRECTION OUTPUT ;
    USE SIGNAL ;
    PORT
      LAYER M5 ;
        RECT  48.48 25.836 48.504 25.92 ;
    END
  END o_x1[153]
  PIN o_x1[154]
    DIRECTION OUTPUT ;
    USE SIGNAL ;
    PORT
      LAYER M3 ;
        RECT  48.564 25.882 48.582 25.92 ;
    END
  END o_x1[154]
  PIN o_x1[155]
    DIRECTION OUTPUT ;
    USE SIGNAL ;
    PORT
      LAYER M5 ;
        RECT  48.672 25.836 48.696 25.92 ;
    END
  END o_x1[155]
  PIN o_x1[156]
    DIRECTION OUTPUT ;
    USE SIGNAL ;
    PORT
      LAYER M3 ;
        RECT  48.78 25.882 48.798 25.92 ;
    END
  END o_x1[156]
  PIN o_x1[157]
    DIRECTION OUTPUT ;
    USE SIGNAL ;
    PORT
      LAYER M5 ;
        RECT  48.864 25.836 48.888 25.92 ;
    END
  END o_x1[157]
  PIN o_x1[158]
    DIRECTION OUTPUT ;
    USE SIGNAL ;
    PORT
      LAYER M3 ;
        RECT  48.96 25.882 48.978 25.92 ;
    END
  END o_x1[158]
  PIN o_x1[159]
    DIRECTION OUTPUT ;
    USE SIGNAL ;
    PORT
      LAYER M5 ;
        RECT  49.056 25.836 49.08 25.92 ;
    END
  END o_x1[159]
  PIN o_x1[15]
    DIRECTION OUTPUT ;
    USE SIGNAL ;
    PORT
      LAYER M5 ;
        RECT  35.664 25.836 35.688 25.92 ;
    END
  END o_x1[15]
  PIN o_x1[160]
    DIRECTION OUTPUT ;
    USE SIGNAL ;
    PORT
      LAYER M3 ;
        RECT  49.14 25.882 49.158 25.92 ;
    END
  END o_x1[160]
  PIN o_x1[161]
    DIRECTION OUTPUT ;
    USE SIGNAL ;
    PORT
      LAYER M5 ;
        RECT  49.248 25.836 49.272 25.92 ;
    END
  END o_x1[161]
  PIN o_x1[162]
    DIRECTION OUTPUT ;
    USE SIGNAL ;
    PORT
      LAYER M3 ;
        RECT  49.356 25.882 49.374 25.92 ;
    END
  END o_x1[162]
  PIN o_x1[163]
    DIRECTION OUTPUT ;
    USE SIGNAL ;
    PORT
      LAYER M5 ;
        RECT  49.44 25.836 49.464 25.92 ;
    END
  END o_x1[163]
  PIN o_x1[164]
    DIRECTION OUTPUT ;
    USE SIGNAL ;
    PORT
      LAYER M3 ;
        RECT  49.536 25.882 49.554 25.92 ;
    END
  END o_x1[164]
  PIN o_x1[165]
    DIRECTION OUTPUT ;
    USE SIGNAL ;
    PORT
      LAYER M5 ;
        RECT  49.632 25.836 49.656 25.92 ;
    END
  END o_x1[165]
  PIN o_x1[166]
    DIRECTION OUTPUT ;
    USE SIGNAL ;
    PORT
      LAYER M3 ;
        RECT  49.716 25.882 49.734 25.92 ;
    END
  END o_x1[166]
  PIN o_x1[167]
    DIRECTION OUTPUT ;
    USE SIGNAL ;
    PORT
      LAYER M5 ;
        RECT  49.824 25.836 49.848 25.92 ;
    END
  END o_x1[167]
  PIN o_x1[168]
    DIRECTION OUTPUT ;
    USE SIGNAL ;
    PORT
      LAYER M3 ;
        RECT  49.86 25.882 49.878 25.92 ;
    END
  END o_x1[168]
  PIN o_x1[169]
    DIRECTION OUTPUT ;
    USE SIGNAL ;
    PORT
      LAYER M5 ;
        RECT  49.968 25.836 49.992 25.92 ;
    END
  END o_x1[169]
  PIN o_x1[16]
    DIRECTION OUTPUT ;
    USE SIGNAL ;
    PORT
      LAYER M3 ;
        RECT  35.748 25.882 35.766 25.92 ;
    END
  END o_x1[16]
  PIN o_x1[170]
    DIRECTION OUTPUT ;
    USE SIGNAL ;
    PORT
      LAYER M3 ;
        RECT  50.076 25.882 50.094 25.92 ;
    END
  END o_x1[170]
  PIN o_x1[171]
    DIRECTION OUTPUT ;
    USE SIGNAL ;
    PORT
      LAYER M5 ;
        RECT  50.16 25.836 50.184 25.92 ;
    END
  END o_x1[171]
  PIN o_x1[172]
    DIRECTION OUTPUT ;
    USE SIGNAL ;
    PORT
      LAYER M3 ;
        RECT  50.256 25.882 50.274 25.92 ;
    END
  END o_x1[172]
  PIN o_x1[173]
    DIRECTION OUTPUT ;
    USE SIGNAL ;
    PORT
      LAYER M5 ;
        RECT  50.352 25.836 50.376 25.92 ;
    END
  END o_x1[173]
  PIN o_x1[174]
    DIRECTION OUTPUT ;
    USE SIGNAL ;
    PORT
      LAYER M3 ;
        RECT  50.436 25.882 50.454 25.92 ;
    END
  END o_x1[174]
  PIN o_x1[175]
    DIRECTION OUTPUT ;
    USE SIGNAL ;
    PORT
      LAYER M5 ;
        RECT  50.544 25.836 50.568 25.92 ;
    END
  END o_x1[175]
  PIN o_x1[176]
    DIRECTION OUTPUT ;
    USE SIGNAL ;
    PORT
      LAYER M3 ;
        RECT  50.652 25.882 50.67 25.92 ;
    END
  END o_x1[176]
  PIN o_x1[177]
    DIRECTION OUTPUT ;
    USE SIGNAL ;
    PORT
      LAYER M5 ;
        RECT  50.736 25.836 50.76 25.92 ;
    END
  END o_x1[177]
  PIN o_x1[178]
    DIRECTION OUTPUT ;
    USE SIGNAL ;
    PORT
      LAYER M3 ;
        RECT  50.832 25.882 50.85 25.92 ;
    END
  END o_x1[178]
  PIN o_x1[179]
    DIRECTION OUTPUT ;
    USE SIGNAL ;
    PORT
      LAYER M5 ;
        RECT  50.928 25.836 50.952 25.92 ;
    END
  END o_x1[179]
  PIN o_x1[17]
    DIRECTION OUTPUT ;
    USE SIGNAL ;
    PORT
      LAYER M5 ;
        RECT  35.856 25.836 35.88 25.92 ;
    END
  END o_x1[17]
  PIN o_x1[180]
    DIRECTION OUTPUT ;
    USE SIGNAL ;
    PORT
      LAYER M3 ;
        RECT  51.012 25.882 51.03 25.92 ;
    END
  END o_x1[180]
  PIN o_x1[181]
    DIRECTION OUTPUT ;
    USE SIGNAL ;
    PORT
      LAYER M5 ;
        RECT  51.12 25.836 51.144 25.92 ;
    END
  END o_x1[181]
  PIN o_x1[182]
    DIRECTION OUTPUT ;
    USE SIGNAL ;
    PORT
      LAYER M3 ;
        RECT  51.228 25.882 51.246 25.92 ;
    END
  END o_x1[182]
  PIN o_x1[183]
    DIRECTION OUTPUT ;
    USE SIGNAL ;
    PORT
      LAYER M5 ;
        RECT  51.264 25.836 51.288 25.92 ;
    END
  END o_x1[183]
  PIN o_x1[184]
    DIRECTION OUTPUT ;
    USE SIGNAL ;
    PORT
      LAYER M3 ;
        RECT  51.372 25.882 51.39 25.92 ;
    END
  END o_x1[184]
  PIN o_x1[185]
    DIRECTION OUTPUT ;
    USE SIGNAL ;
    PORT
      LAYER M5 ;
        RECT  51.456 25.836 51.48 25.92 ;
    END
  END o_x1[185]
  PIN o_x1[186]
    DIRECTION OUTPUT ;
    USE SIGNAL ;
    PORT
      LAYER M3 ;
        RECT  51.552 25.882 51.57 25.92 ;
    END
  END o_x1[186]
  PIN o_x1[187]
    DIRECTION OUTPUT ;
    USE SIGNAL ;
    PORT
      LAYER M5 ;
        RECT  51.648 25.836 51.672 25.92 ;
    END
  END o_x1[187]
  PIN o_x1[188]
    DIRECTION OUTPUT ;
    USE SIGNAL ;
    PORT
      LAYER M3 ;
        RECT  51.732 25.882 51.75 25.92 ;
    END
  END o_x1[188]
  PIN o_x1[189]
    DIRECTION OUTPUT ;
    USE SIGNAL ;
    PORT
      LAYER M5 ;
        RECT  51.84 25.836 51.864 25.92 ;
    END
  END o_x1[189]
  PIN o_x1[18]
    DIRECTION OUTPUT ;
    USE SIGNAL ;
    PORT
      LAYER M3 ;
        RECT  35.964 25.882 35.982 25.92 ;
    END
  END o_x1[18]
  PIN o_x1[190]
    DIRECTION OUTPUT ;
    USE SIGNAL ;
    PORT
      LAYER M3 ;
        RECT  51.948 25.882 51.966 25.92 ;
    END
  END o_x1[190]
  PIN o_x1[191]
    DIRECTION OUTPUT ;
    USE SIGNAL ;
    PORT
      LAYER M5 ;
        RECT  52.032 25.836 52.056 25.92 ;
    END
  END o_x1[191]
  PIN o_x1[192]
    DIRECTION OUTPUT ;
    USE SIGNAL ;
    PORT
      LAYER M3 ;
        RECT  52.128 25.882 52.146 25.92 ;
    END
  END o_x1[192]
  PIN o_x1[193]
    DIRECTION OUTPUT ;
    USE SIGNAL ;
    PORT
      LAYER M5 ;
        RECT  52.224 25.836 52.248 25.92 ;
    END
  END o_x1[193]
  PIN o_x1[194]
    DIRECTION OUTPUT ;
    USE SIGNAL ;
    PORT
      LAYER M3 ;
        RECT  52.308 25.882 52.326 25.92 ;
    END
  END o_x1[194]
  PIN o_x1[195]
    DIRECTION OUTPUT ;
    USE SIGNAL ;
    PORT
      LAYER M5 ;
        RECT  52.416 25.836 52.44 25.92 ;
    END
  END o_x1[195]
  PIN o_x1[196]
    DIRECTION OUTPUT ;
    USE SIGNAL ;
    PORT
      LAYER M3 ;
        RECT  52.524 25.882 52.542 25.92 ;
    END
  END o_x1[196]
  PIN o_x1[197]
    DIRECTION OUTPUT ;
    USE SIGNAL ;
    PORT
      LAYER M5 ;
        RECT  52.608 25.836 52.632 25.92 ;
    END
  END o_x1[197]
  PIN o_x1[198]
    DIRECTION OUTPUT ;
    USE SIGNAL ;
    PORT
      LAYER M3 ;
        RECT  52.704 25.882 52.722 25.92 ;
    END
  END o_x1[198]
  PIN o_x1[199]
    DIRECTION OUTPUT ;
    USE SIGNAL ;
    PORT
      LAYER M5 ;
        RECT  52.752 25.836 52.776 25.92 ;
    END
  END o_x1[199]
  PIN o_x1[19]
    DIRECTION OUTPUT ;
    USE SIGNAL ;
    PORT
      LAYER M5 ;
        RECT  36.048 25.836 36.072 25.92 ;
    END
  END o_x1[19]
  PIN o_x1[1]
    DIRECTION OUTPUT ;
    USE SIGNAL ;
    PORT
      LAYER M5 ;
        RECT  34.368 25.836 34.392 25.92 ;
    END
  END o_x1[1]
  PIN o_x1[200]
    DIRECTION OUTPUT ;
    USE SIGNAL ;
    PORT
      LAYER M3 ;
        RECT  52.848 25.882 52.866 25.92 ;
    END
  END o_x1[200]
  PIN o_x1[201]
    DIRECTION OUTPUT ;
    USE SIGNAL ;
    PORT
      LAYER M5 ;
        RECT  52.944 25.836 52.968 25.92 ;
    END
  END o_x1[201]
  PIN o_x1[202]
    DIRECTION OUTPUT ;
    USE SIGNAL ;
    PORT
      LAYER M3 ;
        RECT  53.028 25.882 53.046 25.92 ;
    END
  END o_x1[202]
  PIN o_x1[203]
    DIRECTION OUTPUT ;
    USE SIGNAL ;
    PORT
      LAYER M5 ;
        RECT  53.136 25.836 53.16 25.92 ;
    END
  END o_x1[203]
  PIN o_x1[204]
    DIRECTION OUTPUT ;
    USE SIGNAL ;
    PORT
      LAYER M3 ;
        RECT  53.244 25.882 53.262 25.92 ;
    END
  END o_x1[204]
  PIN o_x1[205]
    DIRECTION OUTPUT ;
    USE SIGNAL ;
    PORT
      LAYER M5 ;
        RECT  53.328 25.836 53.352 25.92 ;
    END
  END o_x1[205]
  PIN o_x1[206]
    DIRECTION OUTPUT ;
    USE SIGNAL ;
    PORT
      LAYER M3 ;
        RECT  53.424 25.882 53.442 25.92 ;
    END
  END o_x1[206]
  PIN o_x1[207]
    DIRECTION OUTPUT ;
    USE SIGNAL ;
    PORT
      LAYER M5 ;
        RECT  53.52 25.836 53.544 25.92 ;
    END
  END o_x1[207]
  PIN o_x1[208]
    DIRECTION OUTPUT ;
    USE SIGNAL ;
    PORT
      LAYER M3 ;
        RECT  53.604 25.882 53.622 25.92 ;
    END
  END o_x1[208]
  PIN o_x1[209]
    DIRECTION OUTPUT ;
    USE SIGNAL ;
    PORT
      LAYER M5 ;
        RECT  53.712 25.836 53.736 25.92 ;
    END
  END o_x1[209]
  PIN o_x1[20]
    DIRECTION OUTPUT ;
    USE SIGNAL ;
    PORT
      LAYER M3 ;
        RECT  36.144 25.882 36.162 25.92 ;
    END
  END o_x1[20]
  PIN o_x1[210]
    DIRECTION OUTPUT ;
    USE SIGNAL ;
    PORT
      LAYER M3 ;
        RECT  53.82 25.882 53.838 25.92 ;
    END
  END o_x1[210]
  PIN o_x1[211]
    DIRECTION OUTPUT ;
    USE SIGNAL ;
    PORT
      LAYER M5 ;
        RECT  53.904 25.836 53.928 25.92 ;
    END
  END o_x1[211]
  PIN o_x1[212]
    DIRECTION OUTPUT ;
    USE SIGNAL ;
    PORT
      LAYER M3 ;
        RECT  54 25.882 54.018 25.92 ;
    END
  END o_x1[212]
  PIN o_x1[213]
    DIRECTION OUTPUT ;
    USE SIGNAL ;
    PORT
      LAYER M5 ;
        RECT  54.096 25.836 54.12 25.92 ;
    END
  END o_x1[213]
  PIN o_x1[214]
    DIRECTION OUTPUT ;
    USE SIGNAL ;
    PORT
      LAYER M3 ;
        RECT  54.18 25.882 54.198 25.92 ;
    END
  END o_x1[214]
  PIN o_x1[215]
    DIRECTION OUTPUT ;
    USE SIGNAL ;
    PORT
      LAYER M5 ;
        RECT  54.24 25.836 54.264 25.92 ;
    END
  END o_x1[215]
  PIN o_x1[216]
    DIRECTION OUTPUT ;
    USE SIGNAL ;
    PORT
      LAYER M3 ;
        RECT  54.324 25.882 54.342 25.92 ;
    END
  END o_x1[216]
  PIN o_x1[217]
    DIRECTION OUTPUT ;
    USE SIGNAL ;
    PORT
      LAYER M5 ;
        RECT  54.432 25.836 54.456 25.92 ;
    END
  END o_x1[217]
  PIN o_x1[218]
    DIRECTION OUTPUT ;
    USE SIGNAL ;
    PORT
      LAYER M3 ;
        RECT  54.54 25.882 54.558 25.92 ;
    END
  END o_x1[218]
  PIN o_x1[219]
    DIRECTION OUTPUT ;
    USE SIGNAL ;
    PORT
      LAYER M5 ;
        RECT  54.624 25.836 54.648 25.92 ;
    END
  END o_x1[219]
  PIN o_x1[21]
    DIRECTION OUTPUT ;
    USE SIGNAL ;
    PORT
      LAYER M5 ;
        RECT  36.24 25.836 36.264 25.92 ;
    END
  END o_x1[21]
  PIN o_x1[220]
    DIRECTION OUTPUT ;
    USE SIGNAL ;
    PORT
      LAYER M3 ;
        RECT  54.72 25.882 54.738 25.92 ;
    END
  END o_x1[220]
  PIN o_x1[221]
    DIRECTION OUTPUT ;
    USE SIGNAL ;
    PORT
      LAYER M5 ;
        RECT  54.816 25.836 54.84 25.92 ;
    END
  END o_x1[221]
  PIN o_x1[222]
    DIRECTION OUTPUT ;
    USE SIGNAL ;
    PORT
      LAYER M3 ;
        RECT  54.9 25.882 54.918 25.92 ;
    END
  END o_x1[222]
  PIN o_x1[223]
    DIRECTION OUTPUT ;
    USE SIGNAL ;
    PORT
      LAYER M5 ;
        RECT  55.008 25.836 55.032 25.92 ;
    END
  END o_x1[223]
  PIN o_x1[224]
    DIRECTION OUTPUT ;
    USE SIGNAL ;
    PORT
      LAYER M3 ;
        RECT  55.116 25.882 55.134 25.92 ;
    END
  END o_x1[224]
  PIN o_x1[225]
    DIRECTION OUTPUT ;
    USE SIGNAL ;
    PORT
      LAYER M5 ;
        RECT  55.2 25.836 55.224 25.92 ;
    END
  END o_x1[225]
  PIN o_x1[226]
    DIRECTION OUTPUT ;
    USE SIGNAL ;
    PORT
      LAYER M3 ;
        RECT  55.296 25.882 55.314 25.92 ;
    END
  END o_x1[226]
  PIN o_x1[227]
    DIRECTION OUTPUT ;
    USE SIGNAL ;
    PORT
      LAYER M5 ;
        RECT  55.392 25.836 55.416 25.92 ;
    END
  END o_x1[227]
  PIN o_x1[228]
    DIRECTION OUTPUT ;
    USE SIGNAL ;
    PORT
      LAYER M3 ;
        RECT  55.476 25.882 55.494 25.92 ;
    END
  END o_x1[228]
  PIN o_x1[229]
    DIRECTION OUTPUT ;
    USE SIGNAL ;
    PORT
      LAYER M5 ;
        RECT  55.584 25.836 55.608 25.92 ;
    END
  END o_x1[229]
  PIN o_x1[22]
    DIRECTION OUTPUT ;
    USE SIGNAL ;
    PORT
      LAYER M3 ;
        RECT  36.324 25.882 36.342 25.92 ;
    END
  END o_x1[22]
  PIN o_x1[230]
    DIRECTION OUTPUT ;
    USE SIGNAL ;
    PORT
      LAYER M3 ;
        RECT  55.692 25.882 55.71 25.92 ;
    END
  END o_x1[230]
  PIN o_x1[231]
    DIRECTION OUTPUT ;
    USE SIGNAL ;
    PORT
      LAYER M5 ;
        RECT  55.728 25.836 55.752 25.92 ;
    END
  END o_x1[231]
  PIN o_x1[232]
    DIRECTION OUTPUT ;
    USE SIGNAL ;
    PORT
      LAYER M3 ;
        RECT  55.836 25.882 55.854 25.92 ;
    END
  END o_x1[232]
  PIN o_x1[233]
    DIRECTION OUTPUT ;
    USE SIGNAL ;
    PORT
      LAYER M5 ;
        RECT  55.92 25.836 55.944 25.92 ;
    END
  END o_x1[233]
  PIN o_x1[234]
    DIRECTION OUTPUT ;
    USE SIGNAL ;
    PORT
      LAYER M3 ;
        RECT  56.016 25.882 56.034 25.92 ;
    END
  END o_x1[234]
  PIN o_x1[235]
    DIRECTION OUTPUT ;
    USE SIGNAL ;
    PORT
      LAYER M5 ;
        RECT  56.112 25.836 56.136 25.92 ;
    END
  END o_x1[235]
  PIN o_x1[236]
    DIRECTION OUTPUT ;
    USE SIGNAL ;
    PORT
      LAYER M3 ;
        RECT  56.196 25.882 56.214 25.92 ;
    END
  END o_x1[236]
  PIN o_x1[237]
    DIRECTION OUTPUT ;
    USE SIGNAL ;
    PORT
      LAYER M5 ;
        RECT  56.304 25.836 56.328 25.92 ;
    END
  END o_x1[237]
  PIN o_x1[238]
    DIRECTION OUTPUT ;
    USE SIGNAL ;
    PORT
      LAYER M3 ;
        RECT  56.412 25.882 56.43 25.92 ;
    END
  END o_x1[238]
  PIN o_x1[239]
    DIRECTION OUTPUT ;
    USE SIGNAL ;
    PORT
      LAYER M5 ;
        RECT  56.496 25.836 56.52 25.92 ;
    END
  END o_x1[239]
  PIN o_x1[23]
    DIRECTION OUTPUT ;
    USE SIGNAL ;
    PORT
      LAYER M5 ;
        RECT  36.432 25.836 36.456 25.92 ;
    END
  END o_x1[23]
  PIN o_x1[240]
    DIRECTION OUTPUT ;
    USE SIGNAL ;
    PORT
      LAYER M3 ;
        RECT  56.592 25.882 56.61 25.92 ;
    END
  END o_x1[240]
  PIN o_x1[241]
    DIRECTION OUTPUT ;
    USE SIGNAL ;
    PORT
      LAYER M5 ;
        RECT  56.688 25.836 56.712 25.92 ;
    END
  END o_x1[241]
  PIN o_x1[242]
    DIRECTION OUTPUT ;
    USE SIGNAL ;
    PORT
      LAYER M3 ;
        RECT  56.772 25.882 56.79 25.92 ;
    END
  END o_x1[242]
  PIN o_x1[243]
    DIRECTION OUTPUT ;
    USE SIGNAL ;
    PORT
      LAYER M5 ;
        RECT  56.88 25.836 56.904 25.92 ;
    END
  END o_x1[243]
  PIN o_x1[244]
    DIRECTION OUTPUT ;
    USE SIGNAL ;
    PORT
      LAYER M3 ;
        RECT  56.988 25.882 57.006 25.92 ;
    END
  END o_x1[244]
  PIN o_x1[245]
    DIRECTION OUTPUT ;
    USE SIGNAL ;
    PORT
      LAYER M5 ;
        RECT  57.072 25.836 57.096 25.92 ;
    END
  END o_x1[245]
  PIN o_x1[246]
    DIRECTION OUTPUT ;
    USE SIGNAL ;
    PORT
      LAYER M3 ;
        RECT  57.168 25.882 57.186 25.92 ;
    END
  END o_x1[246]
  PIN o_x1[247]
    DIRECTION OUTPUT ;
    USE SIGNAL ;
    PORT
      LAYER M5 ;
        RECT  57.216 25.836 57.24 25.92 ;
    END
  END o_x1[247]
  PIN o_x1[248]
    DIRECTION OUTPUT ;
    USE SIGNAL ;
    PORT
      LAYER M3 ;
        RECT  57.312 25.882 57.33 25.92 ;
    END
  END o_x1[248]
  PIN o_x1[249]
    DIRECTION OUTPUT ;
    USE SIGNAL ;
    PORT
      LAYER M5 ;
        RECT  57.408 25.836 57.432 25.92 ;
    END
  END o_x1[249]
  PIN o_x1[24]
    DIRECTION OUTPUT ;
    USE SIGNAL ;
    PORT
      LAYER M3 ;
        RECT  36.54 25.882 36.558 25.92 ;
    END
  END o_x1[24]
  PIN o_x1[250]
    DIRECTION OUTPUT ;
    USE SIGNAL ;
    PORT
      LAYER M3 ;
        RECT  57.492 25.882 57.51 25.92 ;
    END
  END o_x1[250]
  PIN o_x1[251]
    DIRECTION OUTPUT ;
    USE SIGNAL ;
    PORT
      LAYER M5 ;
        RECT  57.6 25.836 57.624 25.92 ;
    END
  END o_x1[251]
  PIN o_x1[252]
    DIRECTION OUTPUT ;
    USE SIGNAL ;
    PORT
      LAYER M3 ;
        RECT  57.708 25.882 57.726 25.92 ;
    END
  END o_x1[252]
  PIN o_x1[253]
    DIRECTION OUTPUT ;
    USE SIGNAL ;
    PORT
      LAYER M5 ;
        RECT  57.792 25.836 57.816 25.92 ;
    END
  END o_x1[253]
  PIN o_x1[254]
    DIRECTION OUTPUT ;
    USE SIGNAL ;
    PORT
      LAYER M3 ;
        RECT  57.888 25.882 57.906 25.92 ;
    END
  END o_x1[254]
  PIN o_x1[255]
    DIRECTION OUTPUT ;
    USE SIGNAL ;
    PORT
      LAYER M5 ;
        RECT  57.984 25.836 58.008 25.92 ;
    END
  END o_x1[255]
  PIN o_x1[256]
    DIRECTION OUTPUT ;
    USE SIGNAL ;
    PORT
      LAYER M5 ;
        RECT  8.496 25.836 8.52 25.92 ;
    END
  END o_x1[256]
  PIN o_x1[257]
    DIRECTION OUTPUT ;
    USE SIGNAL ;
    PORT
      LAYER M3 ;
        RECT  8.604 25.882 8.622 25.92 ;
    END
  END o_x1[257]
  PIN o_x1[258]
    DIRECTION OUTPUT ;
    USE SIGNAL ;
    PORT
      LAYER M5 ;
        RECT  8.688 25.836 8.712 25.92 ;
    END
  END o_x1[258]
  PIN o_x1[259]
    DIRECTION OUTPUT ;
    USE SIGNAL ;
    PORT
      LAYER M3 ;
        RECT  8.784 25.882 8.802 25.92 ;
    END
  END o_x1[259]
  PIN o_x1[25]
    DIRECTION OUTPUT ;
    USE SIGNAL ;
    PORT
      LAYER M5 ;
        RECT  36.576 25.836 36.6 25.92 ;
    END
  END o_x1[25]
  PIN o_x1[260]
    DIRECTION OUTPUT ;
    USE SIGNAL ;
    PORT
      LAYER M5 ;
        RECT  8.88 25.836 8.904 25.92 ;
    END
  END o_x1[260]
  PIN o_x1[261]
    DIRECTION OUTPUT ;
    USE SIGNAL ;
    PORT
      LAYER M3 ;
        RECT  8.964 25.882 8.982 25.92 ;
    END
  END o_x1[261]
  PIN o_x1[262]
    DIRECTION OUTPUT ;
    USE SIGNAL ;
    PORT
      LAYER M5 ;
        RECT  9.072 25.836 9.096 25.92 ;
    END
  END o_x1[262]
  PIN o_x1[263]
    DIRECTION OUTPUT ;
    USE SIGNAL ;
    PORT
      LAYER M3 ;
        RECT  9.18 25.882 9.198 25.92 ;
    END
  END o_x1[263]
  PIN o_x1[264]
    DIRECTION OUTPUT ;
    USE SIGNAL ;
    PORT
      LAYER M5 ;
        RECT  9.264 25.836 9.288 25.92 ;
    END
  END o_x1[264]
  PIN o_x1[265]
    DIRECTION OUTPUT ;
    USE SIGNAL ;
    PORT
      LAYER M3 ;
        RECT  9.36 25.882 9.378 25.92 ;
    END
  END o_x1[265]
  PIN o_x1[26]
    DIRECTION OUTPUT ;
    USE SIGNAL ;
    PORT
      LAYER M3 ;
        RECT  36.684 25.882 36.702 25.92 ;
    END
  END o_x1[26]
  PIN o_x1[27]
    DIRECTION OUTPUT ;
    USE SIGNAL ;
    PORT
      LAYER M5 ;
        RECT  36.768 25.836 36.792 25.92 ;
    END
  END o_x1[27]
  PIN o_x1[28]
    DIRECTION OUTPUT ;
    USE SIGNAL ;
    PORT
      LAYER M3 ;
        RECT  36.864 25.882 36.882 25.92 ;
    END
  END o_x1[28]
  PIN o_x1[29]
    DIRECTION OUTPUT ;
    USE SIGNAL ;
    PORT
      LAYER M5 ;
        RECT  36.96 25.836 36.984 25.92 ;
    END
  END o_x1[29]
  PIN o_x1[2]
    DIRECTION OUTPUT ;
    USE SIGNAL ;
    PORT
      LAYER M3 ;
        RECT  34.452 25.882 34.47 25.92 ;
    END
  END o_x1[2]
  PIN o_x1[30]
    DIRECTION OUTPUT ;
    USE SIGNAL ;
    PORT
      LAYER M3 ;
        RECT  37.044 25.882 37.062 25.92 ;
    END
  END o_x1[30]
  PIN o_x1[31]
    DIRECTION OUTPUT ;
    USE SIGNAL ;
    PORT
      LAYER M5 ;
        RECT  37.152 25.836 37.176 25.92 ;
    END
  END o_x1[31]
  PIN o_x1[32]
    DIRECTION OUTPUT ;
    USE SIGNAL ;
    PORT
      LAYER M3 ;
        RECT  37.26 25.882 37.278 25.92 ;
    END
  END o_x1[32]
  PIN o_x1[33]
    DIRECTION OUTPUT ;
    USE SIGNAL ;
    PORT
      LAYER M5 ;
        RECT  37.344 25.836 37.368 25.92 ;
    END
  END o_x1[33]
  PIN o_x1[34]
    DIRECTION OUTPUT ;
    USE SIGNAL ;
    PORT
      LAYER M3 ;
        RECT  37.44 25.882 37.458 25.92 ;
    END
  END o_x1[34]
  PIN o_x1[35]
    DIRECTION OUTPUT ;
    USE SIGNAL ;
    PORT
      LAYER M5 ;
        RECT  37.536 25.836 37.56 25.92 ;
    END
  END o_x1[35]
  PIN o_x1[36]
    DIRECTION OUTPUT ;
    USE SIGNAL ;
    PORT
      LAYER M3 ;
        RECT  37.62 25.882 37.638 25.92 ;
    END
  END o_x1[36]
  PIN o_x1[37]
    DIRECTION OUTPUT ;
    USE SIGNAL ;
    PORT
      LAYER M5 ;
        RECT  37.728 25.836 37.752 25.92 ;
    END
  END o_x1[37]
  PIN o_x1[38]
    DIRECTION OUTPUT ;
    USE SIGNAL ;
    PORT
      LAYER M3 ;
        RECT  37.836 25.882 37.854 25.92 ;
    END
  END o_x1[38]
  PIN o_x1[39]
    DIRECTION OUTPUT ;
    USE SIGNAL ;
    PORT
      LAYER M5 ;
        RECT  37.92 25.836 37.944 25.92 ;
    END
  END o_x1[39]
  PIN o_x1[3]
    DIRECTION OUTPUT ;
    USE SIGNAL ;
    PORT
      LAYER M5 ;
        RECT  34.56 25.836 34.584 25.92 ;
    END
  END o_x1[3]
  PIN o_x1[40]
    DIRECTION OUTPUT ;
    USE SIGNAL ;
    PORT
      LAYER M3 ;
        RECT  37.98 25.882 37.998 25.92 ;
    END
  END o_x1[40]
  PIN o_x1[41]
    DIRECTION OUTPUT ;
    USE SIGNAL ;
    PORT
      LAYER M5 ;
        RECT  38.064 25.836 38.088 25.92 ;
    END
  END o_x1[41]
  PIN o_x1[42]
    DIRECTION OUTPUT ;
    USE SIGNAL ;
    PORT
      LAYER M3 ;
        RECT  38.16 25.882 38.178 25.92 ;
    END
  END o_x1[42]
  PIN o_x1[43]
    DIRECTION OUTPUT ;
    USE SIGNAL ;
    PORT
      LAYER M5 ;
        RECT  38.256 25.836 38.28 25.92 ;
    END
  END o_x1[43]
  PIN o_x1[44]
    DIRECTION OUTPUT ;
    USE SIGNAL ;
    PORT
      LAYER M3 ;
        RECT  38.34 25.882 38.358 25.92 ;
    END
  END o_x1[44]
  PIN o_x1[45]
    DIRECTION OUTPUT ;
    USE SIGNAL ;
    PORT
      LAYER M5 ;
        RECT  38.448 25.836 38.472 25.92 ;
    END
  END o_x1[45]
  PIN o_x1[46]
    DIRECTION OUTPUT ;
    USE SIGNAL ;
    PORT
      LAYER M3 ;
        RECT  38.556 25.882 38.574 25.92 ;
    END
  END o_x1[46]
  PIN o_x1[47]
    DIRECTION OUTPUT ;
    USE SIGNAL ;
    PORT
      LAYER M5 ;
        RECT  38.64 25.836 38.664 25.92 ;
    END
  END o_x1[47]
  PIN o_x1[48]
    DIRECTION OUTPUT ;
    USE SIGNAL ;
    PORT
      LAYER M3 ;
        RECT  38.736 25.882 38.754 25.92 ;
    END
  END o_x1[48]
  PIN o_x1[49]
    DIRECTION OUTPUT ;
    USE SIGNAL ;
    PORT
      LAYER M5 ;
        RECT  38.832 25.836 38.856 25.92 ;
    END
  END o_x1[49]
  PIN o_x1[4]
    DIRECTION OUTPUT ;
    USE SIGNAL ;
    PORT
      LAYER M3 ;
        RECT  34.668 25.882 34.686 25.92 ;
    END
  END o_x1[4]
  PIN o_x1[50]
    DIRECTION OUTPUT ;
    USE SIGNAL ;
    PORT
      LAYER M3 ;
        RECT  38.916 25.882 38.934 25.92 ;
    END
  END o_x1[50]
  PIN o_x1[51]
    DIRECTION OUTPUT ;
    USE SIGNAL ;
    PORT
      LAYER M5 ;
        RECT  39.024 25.836 39.048 25.92 ;
    END
  END o_x1[51]
  PIN o_x1[52]
    DIRECTION OUTPUT ;
    USE SIGNAL ;
    PORT
      LAYER M3 ;
        RECT  39.132 25.882 39.15 25.92 ;
    END
  END o_x1[52]
  PIN o_x1[53]
    DIRECTION OUTPUT ;
    USE SIGNAL ;
    PORT
      LAYER M5 ;
        RECT  39.216 25.836 39.24 25.92 ;
    END
  END o_x1[53]
  PIN o_x1[54]
    DIRECTION OUTPUT ;
    USE SIGNAL ;
    PORT
      LAYER M3 ;
        RECT  39.312 25.882 39.33 25.92 ;
    END
  END o_x1[54]
  PIN o_x1[55]
    DIRECTION OUTPUT ;
    USE SIGNAL ;
    PORT
      LAYER M5 ;
        RECT  39.408 25.836 39.432 25.92 ;
    END
  END o_x1[55]
  PIN o_x1[56]
    DIRECTION OUTPUT ;
    USE SIGNAL ;
    PORT
      LAYER M3 ;
        RECT  39.456 25.882 39.474 25.92 ;
    END
  END o_x1[56]
  PIN o_x1[57]
    DIRECTION OUTPUT ;
    USE SIGNAL ;
    PORT
      LAYER M5 ;
        RECT  39.552 25.836 39.576 25.92 ;
    END
  END o_x1[57]
  PIN o_x1[58]
    DIRECTION OUTPUT ;
    USE SIGNAL ;
    PORT
      LAYER M3 ;
        RECT  39.636 25.882 39.654 25.92 ;
    END
  END o_x1[58]
  PIN o_x1[59]
    DIRECTION OUTPUT ;
    USE SIGNAL ;
    PORT
      LAYER M5 ;
        RECT  39.744 25.836 39.768 25.92 ;
    END
  END o_x1[59]
  PIN o_x1[5]
    DIRECTION OUTPUT ;
    USE SIGNAL ;
    PORT
      LAYER M5 ;
        RECT  34.752 25.836 34.776 25.92 ;
    END
  END o_x1[5]
  PIN o_x1[60]
    DIRECTION OUTPUT ;
    USE SIGNAL ;
    PORT
      LAYER M3 ;
        RECT  39.852 25.882 39.87 25.92 ;
    END
  END o_x1[60]
  PIN o_x1[61]
    DIRECTION OUTPUT ;
    USE SIGNAL ;
    PORT
      LAYER M5 ;
        RECT  39.936 25.836 39.96 25.92 ;
    END
  END o_x1[61]
  PIN o_x1[62]
    DIRECTION OUTPUT ;
    USE SIGNAL ;
    PORT
      LAYER M3 ;
        RECT  40.032 25.882 40.05 25.92 ;
    END
  END o_x1[62]
  PIN o_x1[63]
    DIRECTION OUTPUT ;
    USE SIGNAL ;
    PORT
      LAYER M5 ;
        RECT  40.128 25.836 40.152 25.92 ;
    END
  END o_x1[63]
  PIN o_x1[64]
    DIRECTION OUTPUT ;
    USE SIGNAL ;
    PORT
      LAYER M3 ;
        RECT  40.212 25.882 40.23 25.92 ;
    END
  END o_x1[64]
  PIN o_x1[65]
    DIRECTION OUTPUT ;
    USE SIGNAL ;
    PORT
      LAYER M5 ;
        RECT  40.32 25.836 40.344 25.92 ;
    END
  END o_x1[65]
  PIN o_x1[66]
    DIRECTION OUTPUT ;
    USE SIGNAL ;
    PORT
      LAYER M3 ;
        RECT  40.428 25.882 40.446 25.92 ;
    END
  END o_x1[66]
  PIN o_x1[67]
    DIRECTION OUTPUT ;
    USE SIGNAL ;
    PORT
      LAYER M5 ;
        RECT  40.512 25.836 40.536 25.92 ;
    END
  END o_x1[67]
  PIN o_x1[68]
    DIRECTION OUTPUT ;
    USE SIGNAL ;
    PORT
      LAYER M3 ;
        RECT  40.608 25.882 40.626 25.92 ;
    END
  END o_x1[68]
  PIN o_x1[69]
    DIRECTION OUTPUT ;
    USE SIGNAL ;
    PORT
      LAYER M5 ;
        RECT  40.704 25.836 40.728 25.92 ;
    END
  END o_x1[69]
  PIN o_x1[6]
    DIRECTION OUTPUT ;
    USE SIGNAL ;
    PORT
      LAYER M3 ;
        RECT  34.848 25.882 34.866 25.92 ;
    END
  END o_x1[6]
  PIN o_x1[70]
    DIRECTION OUTPUT ;
    USE SIGNAL ;
    PORT
      LAYER M3 ;
        RECT  40.788 25.882 40.806 25.92 ;
    END
  END o_x1[70]
  PIN o_x1[71]
    DIRECTION OUTPUT ;
    USE SIGNAL ;
    PORT
      LAYER M5 ;
        RECT  40.896 25.836 40.92 25.92 ;
    END
  END o_x1[71]
  PIN o_x1[72]
    DIRECTION OUTPUT ;
    USE SIGNAL ;
    PORT
      LAYER M3 ;
        RECT  40.932 25.882 40.95 25.92 ;
    END
  END o_x1[72]
  PIN o_x1[73]
    DIRECTION OUTPUT ;
    USE SIGNAL ;
    PORT
      LAYER M5 ;
        RECT  41.04 25.836 41.064 25.92 ;
    END
  END o_x1[73]
  PIN o_x1[74]
    DIRECTION OUTPUT ;
    USE SIGNAL ;
    PORT
      LAYER M3 ;
        RECT  41.148 25.882 41.166 25.92 ;
    END
  END o_x1[74]
  PIN o_x1[75]
    DIRECTION OUTPUT ;
    USE SIGNAL ;
    PORT
      LAYER M5 ;
        RECT  41.232 25.836 41.256 25.92 ;
    END
  END o_x1[75]
  PIN o_x1[76]
    DIRECTION OUTPUT ;
    USE SIGNAL ;
    PORT
      LAYER M3 ;
        RECT  41.328 25.882 41.346 25.92 ;
    END
  END o_x1[76]
  PIN o_x1[77]
    DIRECTION OUTPUT ;
    USE SIGNAL ;
    PORT
      LAYER M5 ;
        RECT  41.424 25.836 41.448 25.92 ;
    END
  END o_x1[77]
  PIN o_x1[78]
    DIRECTION OUTPUT ;
    USE SIGNAL ;
    PORT
      LAYER M3 ;
        RECT  41.508 25.882 41.526 25.92 ;
    END
  END o_x1[78]
  PIN o_x1[79]
    DIRECTION OUTPUT ;
    USE SIGNAL ;
    PORT
      LAYER M5 ;
        RECT  41.616 25.836 41.64 25.92 ;
    END
  END o_x1[79]
  PIN o_x1[7]
    DIRECTION OUTPUT ;
    USE SIGNAL ;
    PORT
      LAYER M5 ;
        RECT  34.944 25.836 34.968 25.92 ;
    END
  END o_x1[7]
  PIN o_x1[80]
    DIRECTION OUTPUT ;
    USE SIGNAL ;
    PORT
      LAYER M3 ;
        RECT  41.724 25.882 41.742 25.92 ;
    END
  END o_x1[80]
  PIN o_x1[81]
    DIRECTION OUTPUT ;
    USE SIGNAL ;
    PORT
      LAYER M5 ;
        RECT  41.808 25.836 41.832 25.92 ;
    END
  END o_x1[81]
  PIN o_x1[82]
    DIRECTION OUTPUT ;
    USE SIGNAL ;
    PORT
      LAYER M3 ;
        RECT  41.904 25.882 41.922 25.92 ;
    END
  END o_x1[82]
  PIN o_x1[83]
    DIRECTION OUTPUT ;
    USE SIGNAL ;
    PORT
      LAYER M5 ;
        RECT  42 25.836 42.024 25.92 ;
    END
  END o_x1[83]
  PIN o_x1[84]
    DIRECTION OUTPUT ;
    USE SIGNAL ;
    PORT
      LAYER M3 ;
        RECT  42.084 25.882 42.102 25.92 ;
    END
  END o_x1[84]
  PIN o_x1[85]
    DIRECTION OUTPUT ;
    USE SIGNAL ;
    PORT
      LAYER M5 ;
        RECT  42.192 25.836 42.216 25.92 ;
    END
  END o_x1[85]
  PIN o_x1[86]
    DIRECTION OUTPUT ;
    USE SIGNAL ;
    PORT
      LAYER M3 ;
        RECT  42.3 25.882 42.318 25.92 ;
    END
  END o_x1[86]
  PIN o_x1[87]
    DIRECTION OUTPUT ;
    USE SIGNAL ;
    PORT
      LAYER M5 ;
        RECT  42.384 25.836 42.408 25.92 ;
    END
  END o_x1[87]
  PIN o_x1[88]
    DIRECTION OUTPUT ;
    USE SIGNAL ;
    PORT
      LAYER M3 ;
        RECT  42.444 25.882 42.462 25.92 ;
    END
  END o_x1[88]
  PIN o_x1[89]
    DIRECTION OUTPUT ;
    USE SIGNAL ;
    PORT
      LAYER M5 ;
        RECT  42.528 25.836 42.552 25.92 ;
    END
  END o_x1[89]
  PIN o_x1[8]
    DIRECTION OUTPUT ;
    USE SIGNAL ;
    PORT
      LAYER M3 ;
        RECT  35.028 25.882 35.046 25.92 ;
    END
  END o_x1[8]
  PIN o_x1[90]
    DIRECTION OUTPUT ;
    USE SIGNAL ;
    PORT
      LAYER M3 ;
        RECT  42.624 25.882 42.642 25.92 ;
    END
  END o_x1[90]
  PIN o_x1[91]
    DIRECTION OUTPUT ;
    USE SIGNAL ;
    PORT
      LAYER M5 ;
        RECT  42.72 25.836 42.744 25.92 ;
    END
  END o_x1[91]
  PIN o_x1[92]
    DIRECTION OUTPUT ;
    USE SIGNAL ;
    PORT
      LAYER M3 ;
        RECT  42.804 25.882 42.822 25.92 ;
    END
  END o_x1[92]
  PIN o_x1[93]
    DIRECTION OUTPUT ;
    USE SIGNAL ;
    PORT
      LAYER M5 ;
        RECT  42.912 25.836 42.936 25.92 ;
    END
  END o_x1[93]
  PIN o_x1[94]
    DIRECTION OUTPUT ;
    USE SIGNAL ;
    PORT
      LAYER M3 ;
        RECT  43.02 25.882 43.038 25.92 ;
    END
  END o_x1[94]
  PIN o_x1[95]
    DIRECTION OUTPUT ;
    USE SIGNAL ;
    PORT
      LAYER M5 ;
        RECT  43.104 25.836 43.128 25.92 ;
    END
  END o_x1[95]
  PIN o_x1[96]
    DIRECTION OUTPUT ;
    USE SIGNAL ;
    PORT
      LAYER M3 ;
        RECT  43.2 25.882 43.218 25.92 ;
    END
  END o_x1[96]
  PIN o_x1[97]
    DIRECTION OUTPUT ;
    USE SIGNAL ;
    PORT
      LAYER M5 ;
        RECT  43.296 25.836 43.32 25.92 ;
    END
  END o_x1[97]
  PIN o_x1[98]
    DIRECTION OUTPUT ;
    USE SIGNAL ;
    PORT
      LAYER M3 ;
        RECT  43.38 25.882 43.398 25.92 ;
    END
  END o_x1[98]
  PIN o_x1[99]
    DIRECTION OUTPUT ;
    USE SIGNAL ;
    PORT
      LAYER M5 ;
        RECT  43.488 25.836 43.512 25.92 ;
    END
  END o_x1[99]
  PIN o_x1[9]
    DIRECTION OUTPUT ;
    USE SIGNAL ;
    PORT
      LAYER M5 ;
        RECT  35.088 25.836 35.112 25.92 ;
    END
  END o_x1[9]
  PIN rs[0]
    DIRECTION INPUT ;
    USE SIGNAL ;
    PORT
      LAYER M4 ;
        RECT  0 13.056 0.084 13.08 ;
    END
  END rs[0]
  PIN VDD
    DIRECTION INOUT ;
    USE POWER ;
    PORT
      LAYER M5 ;
        RECT  56.592 2.151 56.712 23.769 ;
        RECT  53.892 2.151 54.012 23.769 ;
        RECT  51.192 2.151 51.312 23.769 ;
        RECT  48.492 2.151 48.612 23.769 ;
        RECT  45.792 2.151 45.912 23.769 ;
        RECT  43.092 2.151 43.212 23.769 ;
        RECT  40.392 2.151 40.512 23.769 ;
        RECT  37.692 2.151 37.812 23.769 ;
        RECT  34.992 2.151 35.112 23.769 ;
        RECT  32.292 2.151 32.412 23.769 ;
        RECT  29.592 2.151 29.712 23.769 ;
        RECT  26.892 2.151 27.012 23.769 ;
        RECT  24.192 2.151 24.312 23.769 ;
        RECT  21.492 2.151 21.612 23.769 ;
        RECT  18.792 2.151 18.912 23.769 ;
        RECT  16.092 2.151 16.212 23.769 ;
        RECT  13.392 2.151 13.512 23.769 ;
        RECT  10.692 2.151 10.812 23.769 ;
        RECT  7.992 2.151 8.112 23.769 ;
        RECT  5.292 2.151 5.412 23.769 ;
        RECT  2.592 2.151 2.712 23.769 ;
    END
  END VDD
  PIN VSS
    DIRECTION INOUT ;
    USE GROUND ;
    PORT
      LAYER M5 ;
        RECT  56.4 2.137 56.52 23.783 ;
        RECT  53.7 2.137 53.82 23.783 ;
        RECT  51 2.137 51.12 23.783 ;
        RECT  48.3 2.137 48.42 23.783 ;
        RECT  45.6 2.137 45.72 23.783 ;
        RECT  42.9 2.137 43.02 23.783 ;
        RECT  40.2 2.137 40.32 23.783 ;
        RECT  37.5 2.137 37.62 23.783 ;
        RECT  34.8 2.137 34.92 23.783 ;
        RECT  32.1 2.137 32.22 23.783 ;
        RECT  29.4 2.137 29.52 23.783 ;
        RECT  26.7 2.137 26.82 23.783 ;
        RECT  24 2.137 24.12 23.783 ;
        RECT  21.3 2.137 21.42 23.783 ;
        RECT  18.6 2.137 18.72 23.783 ;
        RECT  15.9 2.137 16.02 23.783 ;
        RECT  13.2 2.137 13.32 23.783 ;
        RECT  10.5 2.137 10.62 23.783 ;
        RECT  7.8 2.137 7.92 23.783 ;
        RECT  5.1 2.137 5.22 23.783 ;
        RECT  2.4 2.137 2.52 23.783 ;
    END
  END VSS
  # OT_OBS_CLOSED layer=M5 d_um=1.536 added=0
  OBS
    LAYER RVTN ;
     RECT  2.16 2.16 58.32 2.295 ;
     RECT  2.16 2.565 58.32 2.835 ;
     RECT  2.16 3.105 58.32 3.375 ;
     RECT  2.16 3.645 58.32 3.915 ;
     RECT  2.16 4.185 58.32 4.455 ;
     RECT  2.16 4.725 58.32 4.995 ;
     RECT  2.16 5.265 58.32 5.535 ;
     RECT  2.16 5.805 58.32 6.075 ;
     RECT  2.16 6.345 58.32 6.615 ;
     RECT  2.16 6.885 58.32 7.155 ;
     RECT  2.16 7.425 58.32 7.695 ;
     RECT  2.16 7.965 58.32 8.235 ;
     RECT  2.16 8.505 58.32 8.775 ;
     RECT  2.16 9.045 58.32 9.315 ;
     RECT  2.16 9.585 58.32 9.855 ;
     RECT  2.16 10.125 58.32 10.395 ;
     RECT  2.16 10.665 58.32 10.935 ;
     RECT  2.16 11.205 58.32 11.475 ;
     RECT  2.16 11.745 58.32 12.015 ;
     RECT  2.16 12.285 58.32 12.555 ;
     RECT  2.16 12.825 58.32 13.095 ;
     RECT  2.16 13.365 58.32 13.635 ;
     RECT  2.16 13.905 58.32 14.175 ;
     RECT  2.16 14.445 58.32 14.715 ;
     RECT  2.16 14.985 58.32 15.255 ;
     RECT  2.16 15.525 58.32 15.795 ;
     RECT  2.16 16.065 58.32 16.335 ;
     RECT  2.16 16.605 58.32 16.875 ;
     RECT  2.16 17.145 58.32 17.415 ;
     RECT  2.16 17.685 58.32 17.955 ;
     RECT  2.16 18.225 58.32 18.495 ;
     RECT  2.16 18.765 58.32 19.035 ;
     RECT  2.16 19.305 58.32 19.575 ;
     RECT  2.16 19.845 58.32 20.115 ;
     RECT  2.16 20.385 58.32 20.655 ;
     RECT  2.16 20.925 58.32 21.195 ;
     RECT  2.16 21.465 58.32 21.735 ;
     RECT  2.16 22.005 58.32 22.275 ;
     RECT  2.16 22.545 58.32 22.815 ;
     RECT  2.16 23.085 58.32 23.355 ;
     RECT  2.16 23.625 58.32 23.76 ;
    LAYER RVTP ;
     RECT  2.16 2.295 58.32 2.565 ;
     RECT  2.16 2.835 58.32 3.105 ;
     RECT  2.16 3.375 58.32 3.645 ;
     RECT  2.16 3.915 58.32 4.185 ;
     RECT  2.16 4.455 58.32 4.725 ;
     RECT  2.16 4.995 58.32 5.265 ;
     RECT  2.16 5.535 58.32 5.805 ;
     RECT  2.16 6.075 58.32 6.345 ;
     RECT  2.16 6.615 58.32 6.885 ;
     RECT  2.16 7.155 58.32 7.425 ;
     RECT  2.16 7.695 58.32 7.965 ;
     RECT  2.16 8.235 58.32 8.505 ;
     RECT  2.16 8.775 58.32 9.045 ;
     RECT  2.16 9.315 58.32 9.585 ;
     RECT  2.16 9.855 58.32 10.125 ;
     RECT  2.16 10.395 58.32 10.665 ;
     RECT  2.16 10.935 58.32 11.205 ;
     RECT  2.16 11.475 58.32 11.745 ;
     RECT  2.16 12.015 58.32 12.285 ;
     RECT  2.16 12.555 58.32 12.825 ;
     RECT  2.16 13.095 58.32 13.365 ;
     RECT  2.16 13.635 58.32 13.905 ;
     RECT  2.16 14.175 58.32 14.445 ;
     RECT  2.16 14.715 58.32 14.985 ;
     RECT  2.16 15.255 58.32 15.525 ;
     RECT  2.16 15.795 58.32 16.065 ;
     RECT  2.16 16.335 58.32 16.605 ;
     RECT  2.16 16.875 58.32 17.145 ;
     RECT  2.16 17.415 58.32 17.685 ;
     RECT  2.16 17.955 58.32 18.225 ;
     RECT  2.16 18.495 58.32 18.765 ;
     RECT  2.16 19.035 58.32 19.305 ;
     RECT  2.16 19.575 58.32 19.845 ;
     RECT  2.16 20.115 58.32 20.385 ;
     RECT  2.16 20.655 58.32 20.925 ;
     RECT  2.16 21.195 58.32 21.465 ;
     RECT  2.16 21.735 58.32 22.005 ;
     RECT  2.16 22.275 58.32 22.545 ;
     RECT  2.16 22.815 58.32 23.085 ;
     RECT  2.16 23.355 58.32 23.625 ;
    LAYER M1 ;
     RECT  2.16 2.151 58.32 23.769 ;
    LAYER M2 ;
     RECT  0.535 12.222 2.16 12.24 ;
     RECT  2.299 0.036 2.399 0.054 ;
     RECT  2.479 25.101 3.019 25.119 ;
     RECT  3.019 25.101 3.263 25.164 ;
     RECT  3.263 25.146 3.479 25.164 ;
     RECT  3.991 0.036 4.091 0.054 ;
     RECT  2.16 2.151 5.071 23.769 ;
     RECT  4.999 25.866 5.099 25.884 ;
     RECT  5.071 1.728 5.279 23.769 ;
     RECT  5.467 25.101 5.611 25.119 ;
     RECT  5.287 0.036 5.819 0.054 ;
     RECT  5.611 25.101 6.007 25.164 ;
     RECT  6.007 25.101 6.179 25.236 ;
     RECT  5.279 2.151 6.187 23.769 ;
     RECT  6.179 25.218 6.503 25.236 ;
     RECT  6.187 1.728 7.663 23.769 ;
     RECT  7.771 0.036 7.907 0.054 ;
     RECT  7.663 1.728 8.159 24.228 ;
     RECT  8.159 2.151 8.239 24.228 ;
     RECT  8.599 25.866 8.699 25.884 ;
     RECT  9.355 0.036 9.455 0.054 ;
     RECT  10.831 0.036 10.967 0.054 ;
     RECT  8.239 2.151 12.227 24.264 ;
     RECT  12.227 2.151 13.423 24.228 ;
     RECT  12.307 25.101 13.451 25.119 ;
     RECT  13.423 1.728 15.395 24.228 ;
     RECT  15.395 1.764 15.539 24.228 ;
     RECT  15.539 1.881 15.575 24.228 ;
     RECT  16.411 0.036 16.511 0.054 ;
     RECT  16.231 25.056 17.015 25.074 ;
     RECT  17.239 25.866 17.339 25.884 ;
     RECT  18.175 25.101 18.311 25.119 ;
     RECT  15.575 2.151 18.319 24.228 ;
     RECT  18.571 0.036 18.707 0.054 ;
     RECT  18.319 2.106 20.327 24.228 ;
     RECT  20.327 2.151 21.055 24.228 ;
     RECT  21.055 1.728 21.803 24.228 ;
     RECT  21.775 0.036 21.875 0.054 ;
     RECT  22.819 25.758 22.955 25.776 ;
     RECT  21.803 2.151 22.963 24.228 ;
     RECT  22.963 2.106 23.143 24.228 ;
     RECT  23.143 1.728 23.747 24.228 ;
     RECT  23.747 2.106 23.783 24.228 ;
     RECT  23.791 1.152 23.891 1.17 ;
     RECT  23.791 0.036 24.071 0.054 ;
     RECT  23.783 2.151 24.755 24.228 ;
     RECT  24.755 2.151 25.339 23.769 ;
     RECT  25.339 1.728 25.979 23.769 ;
     RECT  25.979 2.151 26.491 23.769 ;
     RECT  26.491 2.151 26.843 23.958 ;
     RECT  26.815 0.036 27.167 0.054 ;
     RECT  26.843 2.151 27.211 23.769 ;
     RECT  27.211 1.728 27.527 23.769 ;
     RECT  27.527 2.151 29.299 23.769 ;
     RECT  29.371 0.108 29.407 0.126 ;
     RECT  29.299 2.151 29.435 23.85 ;
     RECT  29.407 0.036 29.579 0.126 ;
     RECT  29.579 0.108 29.651 0.126 ;
     RECT  29.435 2.151 30.703 23.769 ;
     RECT  30.703 1.728 30.983 23.769 ;
     RECT  31.495 0.036 31.595 0.054 ;
     RECT  30.983 2.151 31.639 23.769 ;
     RECT  31.639 2.151 32.099 23.958 ;
     RECT  32.099 2.151 32.395 23.769 ;
     RECT  32.395 1.728 33.755 23.769 ;
     RECT  35.023 25.866 35.267 25.884 ;
     RECT  33.755 2.151 37.615 23.769 ;
     RECT  37.615 0.108 37.831 0.126 ;
     RECT  37.615 2.151 37.831 23.85 ;
     RECT  37.831 0.036 37.859 0.126 ;
     RECT  37.859 0.036 37.931 0.054 ;
     RECT  37.831 2.151 37.967 23.886 ;
     RECT  38.875 0.036 39.335 0.054 ;
     RECT  37.967 2.151 39.631 23.769 ;
     RECT  38.731 25.101 39.731 25.119 ;
     RECT  39.775 25.866 39.875 25.884 ;
     RECT  39.631 1.728 40.207 23.769 ;
     RECT  40.207 1.728 40.379 23.85 ;
     RECT  40.379 1.728 40.595 23.769 ;
     RECT  40.595 1.8 41.323 23.769 ;
     RECT  41.251 25.866 42.035 25.884 ;
     RECT  41.323 1.728 42.791 23.769 ;
     RECT  42.791 2.151 43.015 23.769 ;
     RECT  42.043 0.036 43.295 0.054 ;
     RECT  43.015 2.151 43.331 23.85 ;
     RECT  43.331 2.151 44.887 23.769 ;
     RECT  44.887 25.101 45.247 25.119 ;
     RECT  45.247 25.101 45.391 25.2 ;
     RECT  45.391 24.561 45.455 25.2 ;
     RECT  45.455 24.561 45.599 24.579 ;
     RECT  44.887 1.728 45.607 23.769 ;
     RECT  45.607 1.728 46.103 23.922 ;
     RECT  46.103 1.728 46.211 23.769 ;
     RECT  46.211 2.151 47.083 23.769 ;
     RECT  47.551 25.866 47.687 25.884 ;
     RECT  47.083 1.728 47.831 23.769 ;
     RECT  47.831 1.8 48.011 23.769 ;
     RECT  48.163 0.036 48.263 0.054 ;
     RECT  48.271 0.108 48.407 0.126 ;
     RECT  48.011 1.836 48.775 23.769 ;
     RECT  48.775 1.728 49.343 23.769 ;
     RECT  49.531 25.101 49.703 25.119 ;
     RECT  50.251 1.152 50.351 1.17 ;
     RECT  50.935 0.036 51.035 0.054 ;
     RECT  49.343 2.151 51.223 23.769 ;
     RECT  51.223 1.728 51.611 23.769 ;
     RECT  52.303 25.101 52.511 25.119 ;
     RECT  51.611 2.151 53.239 23.769 ;
     RECT  53.239 2.151 53.627 23.958 ;
     RECT  53.635 0.036 53.843 0.054 ;
     RECT  54.535 25.101 54.815 25.119 ;
     RECT  56.587 0.108 56.767 0.126 ;
     RECT  56.767 0.036 56.795 0.126 ;
     RECT  56.795 0.036 56.867 0.054 ;
     RECT  57.703 0.036 58.091 0.054 ;
     RECT  53.627 2.151 58.32 23.769 ;
    LAYER M3 ;
     RECT  2.304 0.012 58.302 0.059 ;
     RECT  2.376 0.059 58.302 0.077 ;
     RECT  2.376 0.077 58.122 0.125 ;
     RECT  2.376 0.125 27.954 0.173 ;
     RECT  28.692 0.125 58.122 0.173 ;
     RECT  55.116 0.173 56.79 0.221 ;
     RECT  11.772 0.173 27.954 0.269 ;
     RECT  34.452 0.173 37.998 0.269 ;
     RECT  38.736 0.173 54.342 0.317 ;
     RECT  35.964 0.269 37.998 0.365 ;
     RECT  34.452 0.269 35.19 0.413 ;
     RECT  16.344 0.269 27.954 0.461 ;
     RECT  2.376 0.173 10.962 0.557 ;
     RECT  11.772 0.269 15.534 0.557 ;
     RECT  16.524 0.461 27.954 0.557 ;
     RECT  28.692 0.173 33.57 0.557 ;
     RECT  35.964 0.365 37.062 0.557 ;
     RECT  38.736 0.317 44.118 0.557 ;
     RECT  44.892 0.317 54.342 0.557 ;
     RECT  55.116 0.221 55.494 0.557 ;
     RECT  56.412 0.221 56.79 0.557 ;
     RECT  2.376 0.557 7.794 0.653 ;
     RECT  3.204 0.653 7.794 1.723 ;
     RECT  8.964 0.557 10.962 1.723 ;
     RECT  13.428 0.557 15.534 1.723 ;
     RECT  19.98 0.557 19.998 1.723 ;
     RECT  20.88 0.557 21.87 1.723 ;
     RECT  30.564 0.557 33.57 1.723 ;
     RECT  34.452 0.413 34.47 1.723 ;
     RECT  35.964 0.557 36.882 1.723 ;
     RECT  37.836 0.365 37.998 1.723 ;
     RECT  38.88 0.557 44.118 1.723 ;
     RECT  44.892 0.557 51.57 1.723 ;
     RECT  55.116 0.557 55.314 1.723 ;
     RECT  56.772 0.557 56.79 1.723 ;
     RECT  2.376 0.653 2.394 2.011 ;
     RECT  13.356 1.723 15.678 2.059 ;
     RECT  16.524 0.557 16.83 2.059 ;
     RECT  23.148 0.557 27.954 2.101 ;
     RECT  52.524 0.557 54.342 2.107 ;
     RECT  2.34 2.011 2.394 2.143 ;
     RECT  3.204 1.723 10.962 2.143 ;
     RECT  13.356 2.059 16.83 2.143 ;
     RECT  30.564 1.723 34.614 2.143 ;
     RECT  35.892 1.723 36.882 2.143 ;
     RECT  37.656 1.723 37.998 2.143 ;
     RECT  22.968 2.101 27.954 2.155 ;
     RECT  28.692 0.557 29.826 2.155 ;
     RECT  30.564 2.143 34.905 2.155 ;
     RECT  55.116 1.723 55.422 2.155 ;
     RECT  56.34 1.723 56.79 2.155 ;
     RECT  2.34 2.143 10.962 2.191 ;
     RECT  12.348 0.557 12.366 2.191 ;
     RECT  13.215 2.143 16.83 2.191 ;
     RECT  17.712 0.557 19.026 2.191 ;
     RECT  19.98 1.723 21.87 2.191 ;
     RECT  22.968 2.155 29.826 2.191 ;
     RECT  30.564 2.155 35.046 2.191 ;
     RECT  35.892 2.143 37.998 2.191 ;
     RECT  38.88 1.723 51.606 2.191 ;
     RECT  52.452 2.107 54.342 2.191 ;
     RECT  55.116 2.155 56.79 2.191 ;
     RECT  57.78 0.173 58.122 2.191 ;
     RECT  2.34 2.191 35.046 2.203 ;
     RECT  35.892 2.191 38.034 2.203 ;
     RECT  2.34 2.203 38.034 2.251 ;
     RECT  38.88 2.191 58.122 2.251 ;
     RECT  2.34 2.251 58.122 2.263 ;
     RECT  2.34 2.263 58.266 2.641 ;
     RECT  2.304 2.641 58.266 4.145 ;
     RECT  2.34 4.145 58.266 7.187 ;
     RECT  2.415 7.187 58.266 9.259 ;
     RECT  2.376 9.259 58.266 9.509 ;
     RECT  2.415 9.509 58.266 9.533 ;
     RECT  2.415 9.533 58.194 10.253 ;
     RECT  2.415 10.253 58.158 11.365 ;
     RECT  2.415 11.365 58.23 11.405 ;
     RECT  2.415 11.405 58.158 11.981 ;
     RECT  0.54 12.217 0.558 13.085 ;
     RECT  2.415 11.981 58.086 13.195 ;
     RECT  2.415 13.195 58.158 13.981 ;
     RECT  2.415 13.981 58.194 14.639 ;
     RECT  21.06 14.639 58.194 14.747 ;
     RECT  2.415 14.639 20.286 14.783 ;
     RECT  21.132 14.747 58.194 14.819 ;
     RECT  2.415 14.783 19.674 14.909 ;
     RECT  21.132 14.819 58.158 14.945 ;
     RECT  21.132 14.945 38.79 15.215 ;
     RECT  21.132 15.215 38.754 15.449 ;
     RECT  39.564 14.945 58.158 16.303 ;
     RECT  2.415 14.909 18.897 17.077 ;
     RECT  19.656 14.909 19.674 17.077 ;
     RECT  39.564 16.303 58.302 17.077 ;
     RECT  2.415 17.077 19.674 17.105 ;
     RECT  2.415 17.105 19.566 18.797 ;
     RECT  2.415 18.797 19.494 22.219 ;
     RECT  2.415 22.219 19.602 22.711 ;
     RECT  21.132 15.449 38.574 22.811 ;
     RECT  2.415 22.711 19.71 22.819 ;
     RECT  21.168 22.811 38.574 22.829 ;
     RECT  2.415 22.819 19.782 22.847 ;
     RECT  39.528 17.077 58.302 22.847 ;
     RECT  2.415 22.847 18.897 23.507 ;
     RECT  39.564 22.847 58.302 23.507 ;
     RECT  2.415 23.507 18.705 23.777 ;
     RECT  25.704 22.829 38.574 23.777 ;
     RECT  39.564 23.507 53.805 23.777 ;
     RECT  54.54 23.507 58.302 23.777 ;
     RECT  5.868 23.777 12.582 23.885 ;
     RECT  21.168 22.829 24.966 23.885 ;
     RECT  21.24 23.885 24.966 23.933 ;
     RECT  54.54 23.777 55.998 23.933 ;
     RECT  39.564 23.777 53.622 23.963 ;
     RECT  13.824 23.777 18.702 23.981 ;
     RECT  10.836 23.885 12.582 25.051 ;
     RECT  13.824 23.981 14.85 25.051 ;
     RECT  2.628 23.777 5.094 25.096 ;
     RECT  5.868 23.885 9.918 25.096 ;
     RECT  30.204 23.777 38.574 25.096 ;
     RECT  2.484 25.096 9.918 25.099 ;
     RECT  10.836 25.051 14.85 25.099 ;
     RECT  15.84 23.981 18.702 25.099 ;
     RECT  19.764 22.847 19.782 25.099 ;
     RECT  21.636 23.933 24.966 25.099 ;
     RECT  25.704 23.777 29.43 25.099 ;
     RECT  30.204 25.096 38.754 25.099 ;
     RECT  39.564 23.963 52.866 25.099 ;
     RECT  53.604 23.963 53.622 25.099 ;
     RECT  54.54 23.933 55.854 25.099 ;
     RECT  57.06 23.777 58.302 25.099 ;
     RECT  2.484 25.099 53.622 25.483 ;
     RECT  54.54 25.099 58.302 25.483 ;
     RECT  2.484 25.483 58.302 25.819 ;
     RECT  2.304 25.819 58.302 25.901 ;
    LAYER M4 ;
     RECT  0.06 12.96 0.133 13.08 ;
     RECT  0.133 12.96 0.179 13.944 ;
     RECT  0.179 13.056 0.569 13.944 ;
     RECT  2.197 6.24 2.293 6.264 ;
     RECT  2.197 2.88 2.329 2.904 ;
     RECT  2.293 3.984 2.329 4.104 ;
     RECT  2.252 25.824 2.389 25.848 ;
     RECT  2.329 3.984 2.401 4.488 ;
     RECT  2.293 5.76 2.401 6.264 ;
     RECT  2.329 2.016 2.408 2.904 ;
     RECT  2.401 3.984 2.408 6.264 ;
     RECT  2.293 7.248 2.408 7.272 ;
     RECT  2.365 9.264 2.408 9.288 ;
     RECT  0.569 13.92 2.408 13.944 ;
     RECT  2.408 2.016 2.435 23.772 ;
     RECT  2.435 2.148 2.512 23.772 ;
     RECT  2.293 0.528 2.533 0.552 ;
     RECT  2.389 25.776 2.533 25.848 ;
     RECT  2.533 0.144 2.629 0.552 ;
     RECT  2.512 2.418 2.704 23.502 ;
     RECT  2.629 0.048 2.732 0.552 ;
     RECT  2.732 0.048 2.819 0.648 ;
     RECT  2.533 25.68 2.869 25.848 ;
     RECT  2.819 0.048 2.905 0.552 ;
     RECT  2.869 25.104 2.963 25.848 ;
     RECT  2.963 25.584 3.251 25.848 ;
     RECT  2.704 2.418 3.493 11.88 ;
     RECT  3.493 1.728 3.685 11.88 ;
     RECT  2.704 13.92 3.733 13.944 ;
     RECT  3.685 1.728 3.877 12.552 ;
     RECT  3.733 13.632 3.877 13.944 ;
     RECT  3.877 1.728 3.925 13.944 ;
     RECT  2.905 0.048 3.971 0.312 ;
     RECT  3.925 1.728 3.98 14.28 ;
     RECT  3.98 1.104 4.067 14.28 ;
     RECT  3.251 25.584 4.165 25.8 ;
     RECT  4.067 1.728 4.259 14.28 ;
     RECT  4.165 25.152 4.405 25.8 ;
     RECT  4.405 25.104 5.033 25.8 ;
     RECT  4.259 2.064 5.108 14.28 ;
     RECT  4.021 19.344 5.108 19.368 ;
     RECT  3.971 0.048 5.173 0.072 ;
     RECT  5.033 25.584 5.281 25.8 ;
     RECT  5.108 2.064 5.365 23.772 ;
     RECT  5.365 2.064 5.404 24.504 ;
     RECT  5.404 2.064 5.413 14.808 ;
     RECT  5.281 25.584 5.555 25.848 ;
     RECT  5.173 0.048 5.605 0.36 ;
     RECT  5.605 0.048 5.651 0.552 ;
     RECT  5.404 23.904 5.897 24.504 ;
     RECT  5.897 23.904 5.969 23.928 ;
     RECT  5.404 15.936 6.221 15.96 ;
     RECT  5.413 1.728 6.365 14.808 ;
     RECT  6.365 2.16 6.373 14.808 ;
     RECT  5.651 0.528 6.757 0.552 ;
     RECT  6.757 0.48 6.829 0.552 ;
     RECT  6.829 0.48 6.901 0.504 ;
     RECT  6.901 0.144 6.937 0.504 ;
     RECT  5.555 25.728 6.997 25.848 ;
     RECT  6.997 25.632 7.139 25.848 ;
     RECT  6.373 2.16 7.573 15.384 ;
     RECT  7.139 25.632 7.669 25.8 ;
     RECT  7.573 2.064 7.808 15.384 ;
     RECT  6.469 17.088 7.808 17.112 ;
     RECT  7.381 22.752 7.808 22.776 ;
     RECT  7.808 2.064 7.912 23.772 ;
     RECT  7.669 25.104 7.913 25.8 ;
     RECT  7.912 2.064 8.104 23.502 ;
     RECT  6.937 0.048 8.189 0.504 ;
     RECT  8.189 0.048 8.273 0.552 ;
     RECT  8.104 2.064 8.333 14.808 ;
     RECT  8.333 1.728 8.417 14.808 ;
     RECT  7.913 25.536 8.489 25.8 ;
     RECT  8.273 0.048 8.531 0.36 ;
     RECT  8.531 0.048 8.819 0.168 ;
     RECT  8.417 2.112 8.819 14.808 ;
     RECT  8.489 25.632 8.924 25.8 ;
     RECT  8.924 25.632 9.011 25.848 ;
     RECT  8.819 2.112 9.637 14.184 ;
     RECT  9.011 25.632 9.809 25.704 ;
     RECT  8.104 22.752 9.829 22.776 ;
     RECT  9.809 25.152 9.836 25.704 ;
     RECT  9.637 1.728 9.877 14.184 ;
     RECT  9.836 25.008 9.923 25.704 ;
     RECT  9.877 1.728 10.217 14.664 ;
     RECT  8.819 0.144 10.22 0.168 ;
     RECT  9.923 25.104 10.261 25.704 ;
     RECT  10.217 2.016 10.309 14.664 ;
     RECT  10.22 0.048 10.405 0.168 ;
     RECT  10.309 2.016 10.508 14.952 ;
     RECT  9.637 16.272 10.508 16.296 ;
     RECT  9.445 18.144 10.508 18.168 ;
     RECT  9.829 22.752 10.508 22.824 ;
     RECT  10.285 23.856 10.508 23.88 ;
     RECT  10.261 25.104 10.595 25.8 ;
     RECT  10.508 2.016 10.787 23.88 ;
     RECT  10.787 2.016 10.804 23.502 ;
     RECT  10.804 2.016 10.865 14.808 ;
     RECT  10.405 0.048 11.029 0.216 ;
     RECT  11.029 0.048 11.267 0.264 ;
     RECT  11.267 0.144 11.557 0.264 ;
     RECT  11.557 0.144 11.717 0.504 ;
     RECT  10.595 25.104 11.747 25.752 ;
     RECT  11.747 25.104 11.909 25.656 ;
     RECT  11.717 0.144 12.037 0.552 ;
     RECT  12.037 0.144 12.179 1.176 ;
     RECT  10.865 2.208 12.373 14.808 ;
     RECT  12.179 0.144 12.668 0.552 ;
     RECT  12.668 0.048 12.755 0.552 ;
     RECT  11.909 25.104 12.757 25.368 ;
     RECT  12.757 25.008 12.947 25.368 ;
     RECT  12.947 25.056 13.205 25.368 ;
     RECT  12.373 1.728 13.208 14.808 ;
     RECT  10.804 16.272 13.208 16.296 ;
     RECT  10.804 18.144 13.208 18.168 ;
     RECT  10.804 22.752 13.208 22.776 ;
     RECT  13.208 1.728 13.312 23.772 ;
     RECT  13.205 25.104 13.333 25.368 ;
     RECT  13.312 1.728 13.385 23.502 ;
     RECT  13.385 2.064 13.504 23.502 ;
     RECT  13.504 2.064 13.709 14.808 ;
     RECT  12.755 0.144 14.033 0.552 ;
     RECT  13.333 25.104 14.293 25.752 ;
     RECT  13.709 2.208 14.965 14.808 ;
     RECT  14.293 25.104 15.149 25.8 ;
     RECT  14.492 0.048 15.205 0.072 ;
     RECT  15.149 25.152 15.26 25.8 ;
     RECT  15.26 25.152 15.347 25.848 ;
     RECT  14.965 2.064 15.397 14.808 ;
     RECT  15.217 23.952 15.443 23.976 ;
     RECT  15.397 1.728 15.689 14.808 ;
     RECT  15.689 2.064 15.908 14.808 ;
     RECT  13.504 16.272 15.908 16.296 ;
     RECT  13.504 18.144 15.908 18.168 ;
     RECT  14.821 21.12 15.908 21.144 ;
     RECT  13.504 22.752 15.908 22.776 ;
     RECT  15.205 0.048 15.925 0.168 ;
     RECT  15.908 2.064 16.085 23.88 ;
     RECT  16.085 2.256 16.204 23.88 ;
     RECT  16.204 23.856 16.301 23.88 ;
     RECT  15.925 0.048 16.333 0.408 ;
     RECT  15.347 25.152 16.364 25.464 ;
     RECT  16.364 25.152 16.451 25.848 ;
     RECT  16.451 25.152 16.652 25.8 ;
     RECT  16.204 16.272 16.931 17.112 ;
     RECT  16.333 0.048 16.933 0.456 ;
     RECT  16.204 2.256 17.1 14.808 ;
     RECT  17.1 2.208 17.461 14.808 ;
     RECT  17.461 2.16 17.509 14.808 ;
     RECT  16.652 25.104 17.842 25.8 ;
     RECT  17.845 23.952 18.133 23.976 ;
     RECT  17.842 25.104 18.133 25.848 ;
     RECT  16.204 22.752 18.373 22.776 ;
     RECT  16.204 18.144 18.421 18.168 ;
     RECT  18.133 23.952 18.515 25.848 ;
     RECT  17.509 2.16 18.608 14.904 ;
     RECT  16.931 16.272 18.608 17.064 ;
     RECT  18.421 18.144 18.608 18.84 ;
     RECT  18.373 22.752 18.608 22.824 ;
     RECT  18.515 23.952 18.608 25.8 ;
     RECT  18.608 2.148 18.712 25.8 ;
     RECT  18.712 2.208 18.904 23.502 ;
     RECT  18.712 24.48 18.947 25.8 ;
     RECT  18.904 18.144 19.043 18.84 ;
     RECT  18.947 25.104 19.139 25.8 ;
     RECT  19.139 25.104 19.475 25.752 ;
     RECT  18.904 2.208 19.619 14.856 ;
     RECT  18.904 22.224 19.721 22.776 ;
     RECT  19.721 22.224 19.955 22.248 ;
     RECT  19.619 2.208 20.149 14.712 ;
     RECT  16.933 0.048 20.195 0.552 ;
     RECT  20.195 0.096 20.435 0.552 ;
     RECT  20.149 1.728 20.677 14.712 ;
     RECT  19.475 25.104 20.684 25.704 ;
     RECT  18.904 16.272 20.821 16.296 ;
     RECT  20.684 25.104 21.02 25.752 ;
     RECT  21.02 25.104 21.107 25.848 ;
     RECT  21.157 23.856 21.229 23.88 ;
     RECT  20.677 1.728 21.233 15.048 ;
     RECT  21.233 2.016 21.308 15.048 ;
     RECT  20.821 16.272 21.308 17.064 ;
     RECT  19.043 18.144 21.308 18.168 ;
     RECT  19.909 19.248 21.308 19.272 ;
     RECT  21.229 23.856 21.308 23.928 ;
     RECT  21.308 2.016 21.485 23.928 ;
     RECT  21.485 2.208 21.587 23.928 ;
     RECT  21.587 2.208 21.604 23.502 ;
     RECT  20.435 0.144 22.124 0.552 ;
     RECT  22.124 0.048 22.549 0.552 ;
     RECT  21.604 2.208 22.549 14.808 ;
     RECT  22.549 0.048 22.691 14.808 ;
     RECT  22.691 0.048 22.787 1.176 ;
     RECT  22.691 2.208 22.889 14.808 ;
     RECT  22.889 2.208 23.741 14.712 ;
     RECT  23.741 1.728 24.008 14.712 ;
     RECT  21.604 16.272 24.008 16.296 ;
     RECT  21.604 18.144 24.008 18.168 ;
     RECT  21.604 19.248 24.008 19.272 ;
     RECT  24.008 1.728 24.185 23.772 ;
     RECT  24.185 2.016 24.229 23.772 ;
     RECT  24.229 2.016 24.304 23.976 ;
     RECT  22.787 0.048 24.325 0.264 ;
     RECT  24.304 23.856 24.401 23.976 ;
     RECT  24.304 2.016 24.409 14.712 ;
     RECT  24.325 0.048 24.467 0.36 ;
     RECT  21.107 25.104 24.467 25.8 ;
     RECT  24.401 23.856 24.473 23.88 ;
     RECT  24.467 0.24 24.515 0.36 ;
     RECT  24.467 25.104 24.851 25.752 ;
     RECT  24.304 16.272 25.379 16.632 ;
     RECT  24.409 2.208 25.477 14.712 ;
     RECT  25.429 0.096 25.513 0.12 ;
     RECT  25.477 2.208 25.619 14.808 ;
     RECT  25.189 1.152 25.769 1.224 ;
     RECT  24.851 25.104 25.769 25.368 ;
     RECT  25.769 1.2 25.859 1.224 ;
     RECT  25.619 2.208 26.005 14.712 ;
     RECT  25.513 0.096 26.204 0.168 ;
     RECT  26.204 0.048 26.291 0.168 ;
     RECT  26.005 1.728 26.453 14.712 ;
     RECT  26.453 2.148 26.708 14.712 ;
     RECT  25.379 16.272 26.708 16.296 ;
     RECT  24.304 18.144 26.708 18.168 ;
     RECT  24.304 19.248 26.708 19.272 ;
     RECT  25.657 22.8 26.708 22.824 ;
     RECT  26.708 2.148 26.812 23.772 ;
     RECT  26.291 0.096 26.917 0.168 ;
     RECT  25.769 25.104 26.917 25.32 ;
     RECT  26.812 2.16 27.004 23.502 ;
     RECT  26.917 0.096 27.155 0.312 ;
     RECT  26.917 25.104 27.164 25.752 ;
     RECT  27.004 2.16 27.251 14.808 ;
     RECT  27.155 0.096 27.356 0.216 ;
     RECT  27.356 0.048 27.395 0.216 ;
     RECT  27.164 25.104 27.673 25.848 ;
     RECT  27.673 24.528 27.971 25.848 ;
     RECT  27.395 0.048 28.405 0.12 ;
     RECT  27.251 2.16 28.421 14.712 ;
     RECT  27.971 24.528 28.451 25.8 ;
     RECT  28.405 0.048 28.882 0.168 ;
     RECT  28.882 0.048 28.931 0.216 ;
     RECT  28.931 0.096 29.029 0.216 ;
     RECT  28.421 2.16 29.408 14.808 ;
     RECT  27.004 16.272 29.408 16.296 ;
     RECT  27.004 18.144 29.408 18.168 ;
     RECT  27.004 19.248 29.408 19.272 ;
     RECT  28.213 20.544 29.408 20.568 ;
     RECT  28.609 23.952 29.408 23.976 ;
     RECT  29.408 2.148 29.512 23.976 ;
     RECT  29.512 2.256 29.555 23.976 ;
     RECT  29.555 2.256 29.704 23.502 ;
     RECT  28.451 25.104 29.843 25.8 ;
     RECT  29.029 0.096 29.948 0.552 ;
     RECT  29.948 0.048 30.035 0.552 ;
     RECT  29.843 25.104 30.565 25.752 ;
     RECT  30.565 25.008 30.652 25.752 ;
     RECT  30.035 0.096 30.757 0.552 ;
     RECT  29.704 2.256 30.757 14.808 ;
     RECT  30.757 0.096 30.844 1.176 ;
     RECT  30.757 22.608 30.899 22.824 ;
     RECT  29.704 18.144 31.139 19.272 ;
     RECT  30.899 22.704 31.139 22.824 ;
     RECT  30.757 2.256 31.237 14.856 ;
     RECT  30.844 0.096 31.628 0.216 ;
     RECT  30.652 25.104 31.765 25.752 ;
     RECT  29.704 16.272 31.777 16.296 ;
     RECT  31.237 2.112 31.861 14.856 ;
     RECT  31.777 16.272 31.861 17.112 ;
     RECT  31.628 0.048 31.909 0.216 ;
     RECT  31.765 25.104 31.925 25.8 ;
     RECT  31.957 23.856 32.012 23.88 ;
     RECT  32.012 23.856 32.099 23.928 ;
     RECT  31.861 2.112 32.108 17.112 ;
     RECT  31.139 18.144 32.108 18.264 ;
     RECT  31.139 19.248 32.108 19.272 ;
     RECT  31.139 22.8 32.108 22.824 ;
     RECT  32.099 23.856 32.108 23.88 ;
     RECT  31.909 0.048 32.249 0.552 ;
     RECT  32.108 2.112 32.293 23.88 ;
     RECT  32.293 2.016 32.339 23.88 ;
     RECT  32.339 2.016 32.404 23.502 ;
     RECT  32.404 18.144 32.681 18.264 ;
     RECT  32.681 18.24 32.771 18.264 ;
     RECT  32.249 0.048 32.819 0.36 ;
     RECT  32.404 2.016 33.157 14.856 ;
     RECT  31.925 25.104 33.299 25.752 ;
     RECT  33.157 1.728 33.445 14.856 ;
     RECT  32.404 15.984 33.445 16.584 ;
     RECT  33.445 1.728 33.491 16.584 ;
     RECT  33.299 25.152 33.491 25.752 ;
     RECT  33.491 25.248 33.581 25.752 ;
     RECT  32.819 0.048 33.635 0.264 ;
     RECT  33.491 1.728 33.653 16.296 ;
     RECT  33.581 25.536 33.749 25.752 ;
     RECT  33.649 17.664 33.925 17.688 ;
     RECT  33.749 25.536 34.643 25.8 ;
     RECT  33.635 0.048 34.741 0.168 ;
     RECT  33.653 1.728 34.808 15.96 ;
     RECT  33.925 17.664 34.808 17.784 ;
     RECT  34.643 25.68 34.827 25.8 ;
     RECT  34.808 1.728 34.912 23.772 ;
     RECT  34.912 1.728 35.104 23.502 ;
     RECT  34.827 25.68 35.219 25.848 ;
     RECT  34.741 0.048 35.267 0.552 ;
     RECT  35.219 25.68 35.267 25.752 ;
     RECT  35.104 22.8 35.309 22.824 ;
     RECT  35.267 0.048 35.315 0.408 ;
     RECT  35.104 17.04 35.363 18.168 ;
     RECT  35.363 17.088 35.891 18.168 ;
     RECT  35.891 17.088 35.932 17.112 ;
     RECT  35.701 25.104 36.037 25.128 ;
     RECT  35.891 18.144 36.101 18.168 ;
     RECT  35.104 1.728 36.181 15.96 ;
     RECT  36.181 15.936 36.245 15.96 ;
     RECT  36.229 21.648 36.317 21.672 ;
     RECT  36.037 24.48 36.389 25.128 ;
     RECT  35.315 0.048 36.421 0.312 ;
     RECT  36.181 1.728 36.467 14.952 ;
     RECT  36.389 25.104 36.601 25.128 ;
     RECT  36.601 25.104 36.668 25.176 ;
     RECT  36.421 0.048 37.073 0.552 ;
     RECT  36.668 25.104 37.073 25.752 ;
     RECT  37.073 25.536 37.333 25.752 ;
     RECT  37.333 25.536 37.505 25.8 ;
     RECT  36.467 1.728 37.508 14.904 ;
     RECT  36.601 18.768 37.508 18.792 ;
     RECT  37.508 1.728 37.612 23.772 ;
     RECT  37.612 1.728 37.685 23.502 ;
     RECT  37.685 2.064 37.804 23.502 ;
     RECT  37.804 2.064 37.901 15.672 ;
     RECT  37.505 25.536 38.101 25.752 ;
     RECT  37.901 2.208 38.261 15.672 ;
     RECT  37.804 22.176 38.369 22.2 ;
     RECT  37.073 0.048 38.677 0.456 ;
     RECT  38.261 2.208 38.729 15.384 ;
     RECT  38.677 0.048 38.765 0.552 ;
     RECT  38.765 0.048 38.963 0.312 ;
     RECT  38.101 25.104 39.121 25.752 ;
     RECT  39.121 25.104 39.347 25.848 ;
     RECT  38.963 0.096 39.797 0.312 ;
     RECT  39.797 0.096 39.881 0.552 ;
     RECT  38.729 2.208 39.925 14.856 ;
     RECT  39.877 16.08 39.973 16.104 ;
     RECT  39.925 2.208 40.021 15.048 ;
     RECT  39.973 16.08 40.021 16.2 ;
     RECT  40.021 2.208 40.208 16.2 ;
     RECT  40.208 2.148 40.312 23.772 ;
     RECT  39.881 0.096 40.417 0.312 ;
     RECT  39.347 25.104 40.501 25.8 ;
     RECT  40.312 2.16 40.504 23.502 ;
     RECT  40.501 25.056 40.597 25.8 ;
     RECT  40.504 2.16 40.835 15.384 ;
     RECT  40.417 0.048 40.892 0.312 ;
     RECT  40.892 0.048 40.979 0.36 ;
     RECT  40.597 25.056 40.997 25.848 ;
     RECT  40.997 25.728 41.027 25.848 ;
     RECT  40.504 19.392 41.075 19.416 ;
     RECT  41.027 25.776 41.363 25.848 ;
     RECT  40.835 2.688 41.509 15.384 ;
     RECT  40.979 0.048 41.555 0.264 ;
     RECT  40.504 16.56 41.603 16.584 ;
     RECT  41.555 0.096 41.699 0.264 ;
     RECT  41.509 2.688 41.857 15.576 ;
     RECT  41.363 25.776 41.989 25.8 ;
     RECT  41.857 2.256 42.181 15.576 ;
     RECT  41.989 25.104 42.185 25.8 ;
     RECT  41.699 0.096 42.613 0.168 ;
     RECT  42.181 1.728 42.668 15.576 ;
     RECT  42.613 0.048 42.709 0.168 ;
     RECT  42.709 0.048 42.793 0.216 ;
     RECT  42.185 25.104 42.844 25.56 ;
     RECT  42.668 1.728 42.908 16.536 ;
     RECT  41.989 18.768 42.908 18.792 ;
     RECT  42.908 1.728 42.947 23.772 ;
     RECT  42.947 2.016 43.093 23.772 ;
     RECT  43.093 2.016 43.139 23.88 ;
     RECT  43.139 2.208 43.189 23.88 ;
     RECT  42.844 25.536 43.189 25.56 ;
     RECT  43.189 2.208 43.204 24.024 ;
     RECT  43.204 23.856 43.301 24.024 ;
     RECT  43.301 23.856 43.373 23.928 ;
     RECT  42.793 0.048 43.409 0.6 ;
     RECT  43.204 18.816 43.427 18.84 ;
     RECT  43.373 23.904 43.427 23.928 ;
     RECT  43.204 2.208 43.481 15.96 ;
     RECT  43.189 25.536 43.724 25.752 ;
     RECT  43.724 25.536 43.811 25.848 ;
     RECT  43.811 25.536 44.261 25.8 ;
     RECT  43.481 2.208 44.341 15.576 ;
     RECT  44.261 25.104 44.345 25.8 ;
     RECT  44.345 25.68 44.453 25.8 ;
     RECT  44.453 25.68 44.819 25.752 ;
     RECT  43.409 0.048 44.917 0.312 ;
     RECT  45.341 24.48 45.425 24.504 ;
     RECT  44.341 1.728 45.608 15.576 ;
     RECT  45.157 20.496 45.608 20.52 ;
     RECT  45.608 1.728 45.712 23.772 ;
     RECT  44.819 25.728 45.781 25.752 ;
     RECT  45.781 25.68 45.877 25.752 ;
     RECT  45.712 1.728 45.904 23.502 ;
     RECT  44.917 0.048 45.925 0.552 ;
     RECT  45.904 1.728 45.925 15.912 ;
     RECT  45.877 25.632 46.213 25.752 ;
     RECT  45.925 0.048 46.253 15.912 ;
     RECT  46.213 25.104 46.261 25.752 ;
     RECT  46.261 25.104 46.397 25.8 ;
     RECT  46.253 0.048 46.499 15.576 ;
     RECT  46.397 25.152 46.537 25.8 ;
     RECT  46.499 0.048 46.595 1.176 ;
     RECT  46.537 25.152 46.649 25.848 ;
     RECT  46.595 0.048 46.787 0.552 ;
     RECT  46.649 25.152 46.937 25.8 ;
     RECT  46.937 25.632 46.979 25.8 ;
     RECT  46.979 25.68 48.049 25.8 ;
     RECT  48.049 25.488 48.181 25.8 ;
     RECT  46.499 2.208 48.308 15.576 ;
     RECT  47.749 17.616 48.308 17.64 ;
     RECT  48.037 19.344 48.308 19.368 ;
     RECT  47.365 22.176 48.308 22.2 ;
     RECT  48.308 2.148 48.412 23.772 ;
     RECT  48.181 25.104 48.413 25.8 ;
     RECT  46.787 0.144 48.469 0.552 ;
     RECT  48.469 0.096 48.593 0.552 ;
     RECT  48.412 2.256 48.604 23.502 ;
     RECT  48.413 25.584 48.769 25.8 ;
     RECT  48.593 0.096 48.908 0.36 ;
     RECT  48.908 0.048 48.995 0.36 ;
     RECT  48.769 25.584 49.091 25.848 ;
     RECT  48.995 0.144 49.661 0.36 ;
     RECT  49.661 0.144 49.745 0.552 ;
     RECT  49.091 25.68 49.763 25.848 ;
     RECT  49.763 25.68 49.925 25.8 ;
     RECT  49.813 23.904 49.961 23.928 ;
     RECT  48.604 2.256 50.005 15.576 ;
     RECT  49.925 25.68 50.101 25.704 ;
     RECT  49.745 0.144 50.149 0.36 ;
     RECT  50.149 0.096 50.195 0.36 ;
     RECT  50.101 25.152 50.197 25.704 ;
     RECT  50.195 0.096 50.396 0.312 ;
     RECT  50.149 18.768 50.453 18.792 ;
     RECT  50.005 2.256 51.008 15.624 ;
     RECT  50.453 18.768 51.008 19.368 ;
     RECT  51.008 2.148 51.112 23.772 ;
     RECT  51.112 2.148 51.145 23.502 ;
     RECT  50.396 0.048 51.157 0.312 ;
     RECT  50.197 25.104 51.217 25.704 ;
     RECT  51.145 2.016 51.229 23.502 ;
     RECT  51.229 2.112 51.304 23.502 ;
     RECT  51.217 25.104 51.779 25.848 ;
     RECT  51.157 0.048 51.877 0.36 ;
     RECT  51.877 0.048 51.977 0.552 ;
     RECT  51.977 0.048 52.211 0.216 ;
     RECT  51.304 18.768 52.259 18.792 ;
     RECT  51.304 2.112 52.621 15.576 ;
     RECT  52.211 0.048 52.883 0.168 ;
     RECT  52.621 1.728 52.979 15.576 ;
     RECT  51.779 25.104 52.988 25.8 ;
     RECT  52.988 25.104 53.273 25.848 ;
     RECT  52.883 0.096 53.365 0.168 ;
     RECT  53.365 0.096 53.701 0.216 ;
     RECT  52.979 2.016 53.708 15.576 ;
     RECT  53.708 2.016 53.812 23.772 ;
     RECT  53.701 0.096 53.989 0.264 ;
     RECT  53.812 2.016 53.989 23.502 ;
     RECT  53.989 1.968 54.004 23.502 ;
     RECT  54.004 1.968 54.101 16.536 ;
     RECT  53.989 0.048 54.13 0.264 ;
     RECT  54.101 2.016 54.173 16.536 ;
     RECT  53.893 24.48 54.569 24.504 ;
     RECT  54.13 0.048 54.755 0.312 ;
     RECT  53.273 25.488 54.793 25.848 ;
     RECT  54.793 25.488 54.893 25.8 ;
     RECT  54.173 2.208 54.929 16.536 ;
     RECT  54.893 25.488 54.949 25.752 ;
     RECT  54.004 21.072 55.181 21.096 ;
     RECT  54.929 2.208 55.253 15.96 ;
     RECT  55.253 2.208 55.283 15.912 ;
     RECT  54.755 0.096 55.285 0.312 ;
     RECT  55.283 2.208 55.349 15.576 ;
     RECT  54.949 25.104 55.709 25.752 ;
     RECT  55.381 22.176 55.717 22.2 ;
     RECT  55.709 24.96 55.724 25.752 ;
     RECT  55.724 24.816 55.811 25.752 ;
     RECT  55.285 0.096 55.813 0.552 ;
     RECT  55.909 23.904 56.009 23.928 ;
     RECT  55.349 1.728 56.369 15.576 ;
     RECT  56.369 2.064 56.408 15.576 ;
     RECT  55.717 22.176 56.408 22.824 ;
     RECT  55.813 0.048 56.441 0.552 ;
     RECT  55.811 25.008 56.485 25.752 ;
     RECT  56.408 2.064 56.512 23.772 ;
     RECT  56.512 2.064 56.704 23.502 ;
     RECT  56.704 2.064 56.729 15.576 ;
     RECT  56.485 25.008 57.02 25.8 ;
     RECT  57.02 24.528 57.107 25.8 ;
     RECT  57.107 25.104 57.484 25.8 ;
     RECT  56.704 22.752 57.485 22.776 ;
     RECT  56.704 16.56 57.557 17.16 ;
     RECT  56.704 18.576 57.587 19.416 ;
     RECT  56.441 0.048 57.589 0.264 ;
     RECT  56.729 2.256 57.635 15.576 ;
     RECT  57.587 18.576 57.701 18.6 ;
     RECT  57.484 25.104 57.737 25.752 ;
     RECT  57.635 2.592 57.805 15.576 ;
     RECT  57.557 16.56 57.805 17.112 ;
     RECT  56.704 21.648 57.809 21.672 ;
     RECT  57.737 25.728 57.827 25.752 ;
     RECT  57.805 2.592 57.845 17.112 ;
     RECT  57.845 2.592 57.989 16.584 ;
     RECT  57.989 2.592 58.097 15.48 ;
     RECT  58.097 13.056 58.105 15.48 ;
     RECT  57.589 0.048 58.133 0.6 ;
     RECT  58.097 2.592 58.163 12.024 ;
     RECT  58.163 2.592 58.169 11.976 ;
     RECT  58.105 13.2 58.169 15.48 ;
     RECT  57.989 16.56 58.177 16.584 ;
     RECT  58.169 2.592 58.205 10.296 ;
     RECT  58.169 13.488 58.205 15.48 ;
     RECT  58.205 8.352 58.211 10.296 ;
     RECT  58.205 13.488 58.211 13.512 ;
     RECT  58.169 11.376 58.241 11.4 ;
     RECT  58.211 8.352 58.259 9.912 ;
     RECT  58.259 9.504 58.277 9.912 ;
     RECT  58.205 2.592 58.307 6.936 ;
     RECT  58.259 8.352 58.307 8.376 ;
     RECT  58.277 9.888 58.307 9.912 ;
     RECT  58.133 0.048 58.355 0.072 ;
     RECT  58.307 2.592 58.355 6.888 ;
     RECT  58.205 15.456 58.403 15.48 ;
     RECT  58.355 2.592 58.451 5.16 ;
     RECT  58.355 6.768 58.451 6.888 ;
     RECT  58.451 3.936 58.499 3.96 ;
     RECT  58.451 6.864 58.499 6.888 ;
     RECT  58.451 2.88 58.547 2.904 ;
     RECT  58.451 5.136 58.547 5.16 ;
    LAYER M5 ;
     RECT  2.208 0.016 58.2 0.037 ;
     RECT  2.208 0.037 58.344 2.581 ;
     RECT  2.208 2.581 58.44 2.869 ;
     RECT  2.208 2.869 58.536 2.915 ;
     RECT  2.304 2.915 58.536 5.171 ;
     RECT  2.304 5.171 58.488 6.229 ;
     RECT  2.208 6.229 58.488 6.899 ;
     RECT  0.144 12.949 0.168 13.955 ;
     RECT  2.208 6.899 58.392 15.491 ;
     RECT  2.208 15.491 58.2 25.872 ;
  END
END dsfd_qbank_S
END LIBRARY
